VERSION 5.8 ;
BUSBITCHARS "[]" ;
DIVIDERCHAR "/" ;
UNITS
    DATABASE MICRONS 1000 ;
END UNITS

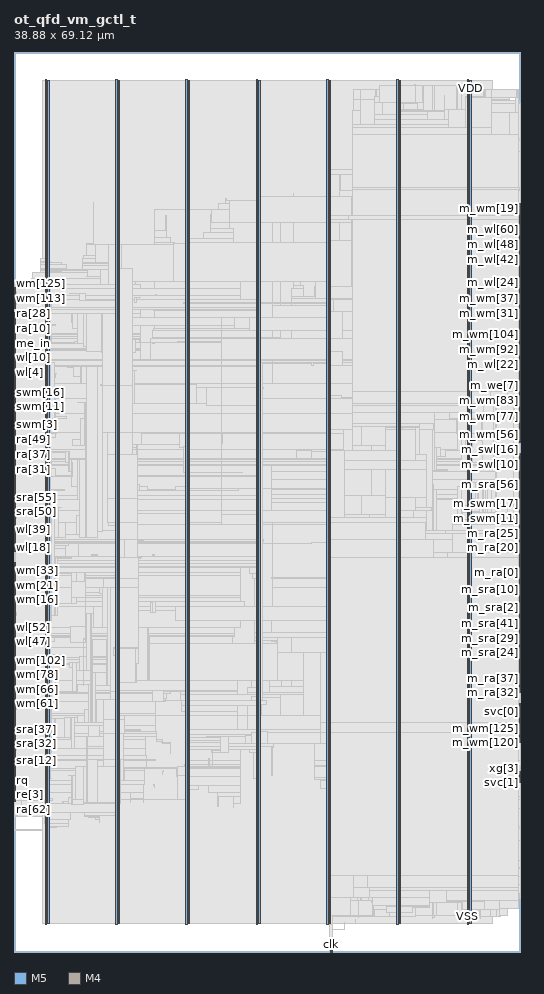
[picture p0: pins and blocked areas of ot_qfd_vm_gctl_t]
MACRO ot_qfd_vm_gctl_t
  FOREIGN ot_qfd_vm_gctl_t 0 0 ;
  CLASS BLOCK ;
  SIZE 38.88 BY 69.12 ;
  PIN clk
    DIRECTION INPUT ;
    USE SIGNAL ;
    PORT
      LAYER M5 ;
        RECT  24.336 0 24.36 0.084 ;
    END
  END clk
  PIN m_ra[0]
    DIRECTION OUTPUT ;
    USE SIGNAL ;
    PORT
      LAYER M4 ;
        RECT  38.796 29.136 38.88 29.16 ;
    END
  END m_ra[0]
  PIN m_ra[10]
    DIRECTION OUTPUT ;
    USE SIGNAL ;
    PORT
      LAYER M4 ;
        RECT  38.796 30.096 38.88 30.12 ;
    END
  END m_ra[10]
  PIN m_ra[11]
    DIRECTION OUTPUT ;
    USE SIGNAL ;
    PORT
      LAYER M4 ;
        RECT  38.796 30.192 38.88 30.216 ;
    END
  END m_ra[11]
  PIN m_ra[12]
    DIRECTION OUTPUT ;
    USE SIGNAL ;
    PORT
      LAYER M4 ;
        RECT  38.796 30.288 38.88 30.312 ;
    END
  END m_ra[12]
  PIN m_ra[13]
    DIRECTION OUTPUT ;
    USE SIGNAL ;
    PORT
      LAYER M4 ;
        RECT  38.796 30.384 38.88 30.408 ;
    END
  END m_ra[13]
  PIN m_ra[14]
    DIRECTION OUTPUT ;
    USE SIGNAL ;
    PORT
      LAYER M4 ;
        RECT  38.796 30.48 38.88 30.504 ;
    END
  END m_ra[14]
  PIN m_ra[15]
    DIRECTION OUTPUT ;
    USE SIGNAL ;
    PORT
      LAYER M4 ;
        RECT  38.796 30.576 38.88 30.6 ;
    END
  END m_ra[15]
  PIN m_ra[16]
    DIRECTION OUTPUT ;
    USE SIGNAL ;
    PORT
      LAYER M4 ;
        RECT  38.796 30.672 38.88 30.696 ;
    END
  END m_ra[16]
  PIN m_ra[17]
    DIRECTION OUTPUT ;
    USE SIGNAL ;
    PORT
      LAYER M4 ;
        RECT  38.796 30.768 38.88 30.792 ;
    END
  END m_ra[17]
  PIN m_ra[18]
    DIRECTION OUTPUT ;
    USE SIGNAL ;
    PORT
      LAYER M4 ;
        RECT  38.796 30.864 38.88 30.888 ;
    END
  END m_ra[18]
  PIN m_ra[19]
    DIRECTION OUTPUT ;
    USE SIGNAL ;
    PORT
      LAYER M4 ;
        RECT  38.796 30.96 38.88 30.984 ;
    END
  END m_ra[19]
  PIN m_ra[1]
    DIRECTION OUTPUT ;
    USE SIGNAL ;
    PORT
      LAYER M4 ;
        RECT  38.796 29.232 38.88 29.256 ;
    END
  END m_ra[1]
  PIN m_ra[20]
    DIRECTION OUTPUT ;
    USE SIGNAL ;
    PORT
      LAYER M4 ;
        RECT  38.796 31.056 38.88 31.08 ;
    END
  END m_ra[20]
  PIN m_ra[21]
    DIRECTION OUTPUT ;
    USE SIGNAL ;
    PORT
      LAYER M4 ;
        RECT  38.796 31.152 38.88 31.176 ;
    END
  END m_ra[21]
  PIN m_ra[22]
    DIRECTION OUTPUT ;
    USE SIGNAL ;
    PORT
      LAYER M4 ;
        RECT  38.796 31.248 38.88 31.272 ;
    END
  END m_ra[22]
  PIN m_ra[23]
    DIRECTION OUTPUT ;
    USE SIGNAL ;
    PORT
      LAYER M4 ;
        RECT  38.796 31.344 38.88 31.368 ;
    END
  END m_ra[23]
  PIN m_ra[24]
    DIRECTION OUTPUT ;
    USE SIGNAL ;
    PORT
      LAYER M4 ;
        RECT  38.796 31.44 38.88 31.464 ;
    END
  END m_ra[24]
  PIN m_ra[25]
    DIRECTION OUTPUT ;
    USE SIGNAL ;
    PORT
      LAYER M4 ;
        RECT  38.796 31.536 38.88 31.56 ;
    END
  END m_ra[25]
  PIN m_ra[26]
    DIRECTION OUTPUT ;
    USE SIGNAL ;
    PORT
      LAYER M4 ;
        RECT  38.796 31.632 38.88 31.656 ;
    END
  END m_ra[26]
  PIN m_ra[27]
    DIRECTION OUTPUT ;
    USE SIGNAL ;
    PORT
      LAYER M4 ;
        RECT  38.796 31.728 38.88 31.752 ;
    END
  END m_ra[27]
  PIN m_ra[28]
    DIRECTION OUTPUT ;
    USE SIGNAL ;
    PORT
      LAYER M4 ;
        RECT  38.796 31.824 38.88 31.848 ;
    END
  END m_ra[28]
  PIN m_ra[29]
    DIRECTION OUTPUT ;
    USE SIGNAL ;
    PORT
      LAYER M4 ;
        RECT  38.796 31.92 38.88 31.944 ;
    END
  END m_ra[29]
  PIN m_ra[2]
    DIRECTION OUTPUT ;
    USE SIGNAL ;
    PORT
      LAYER M4 ;
        RECT  38.796 29.328 38.88 29.352 ;
    END
  END m_ra[2]
  PIN m_ra[30]
    DIRECTION OUTPUT ;
    USE SIGNAL ;
    PORT
      LAYER M4 ;
        RECT  38.796 32.016 38.88 32.04 ;
    END
  END m_ra[30]
  PIN m_ra[31]
    DIRECTION OUTPUT ;
    USE SIGNAL ;
    PORT
      LAYER M4 ;
        RECT  38.796 32.112 38.88 32.136 ;
    END
  END m_ra[31]
  PIN m_ra[32]
    DIRECTION OUTPUT ;
    USE SIGNAL ;
    PORT
      LAYER M4 ;
        RECT  38.796 19.92 38.88 19.944 ;
    END
  END m_ra[32]
  PIN m_ra[33]
    DIRECTION OUTPUT ;
    USE SIGNAL ;
    PORT
      LAYER M4 ;
        RECT  38.796 20.016 38.88 20.04 ;
    END
  END m_ra[33]
  PIN m_ra[34]
    DIRECTION OUTPUT ;
    USE SIGNAL ;
    PORT
      LAYER M4 ;
        RECT  38.796 20.112 38.88 20.136 ;
    END
  END m_ra[34]
  PIN m_ra[35]
    DIRECTION OUTPUT ;
    USE SIGNAL ;
    PORT
      LAYER M4 ;
        RECT  38.796 20.208 38.88 20.232 ;
    END
  END m_ra[35]
  PIN m_ra[36]
    DIRECTION OUTPUT ;
    USE SIGNAL ;
    PORT
      LAYER M4 ;
        RECT  38.796 20.304 38.88 20.328 ;
    END
  END m_ra[36]
  PIN m_ra[37]
    DIRECTION OUTPUT ;
    USE SIGNAL ;
    PORT
      LAYER M4 ;
        RECT  38.796 20.4 38.88 20.424 ;
    END
  END m_ra[37]
  PIN m_ra[38]
    DIRECTION OUTPUT ;
    USE SIGNAL ;
    PORT
      LAYER M4 ;
        RECT  38.796 20.496 38.88 20.52 ;
    END
  END m_ra[38]
  PIN m_ra[39]
    DIRECTION OUTPUT ;
    USE SIGNAL ;
    PORT
      LAYER M4 ;
        RECT  38.796 20.592 38.88 20.616 ;
    END
  END m_ra[39]
  PIN m_ra[3]
    DIRECTION OUTPUT ;
    USE SIGNAL ;
    PORT
      LAYER M4 ;
        RECT  38.796 29.424 38.88 29.448 ;
    END
  END m_ra[3]
  PIN m_ra[40]
    DIRECTION OUTPUT ;
    USE SIGNAL ;
    PORT
      LAYER M4 ;
        RECT  38.796 20.688 38.88 20.712 ;
    END
  END m_ra[40]
  PIN m_ra[41]
    DIRECTION OUTPUT ;
    USE SIGNAL ;
    PORT
      LAYER M4 ;
        RECT  38.796 20.784 38.88 20.808 ;
    END
  END m_ra[41]
  PIN m_ra[42]
    DIRECTION OUTPUT ;
    USE SIGNAL ;
    PORT
      LAYER M4 ;
        RECT  38.796 20.88 38.88 20.904 ;
    END
  END m_ra[42]
  PIN m_ra[43]
    DIRECTION OUTPUT ;
    USE SIGNAL ;
    PORT
      LAYER M4 ;
        RECT  38.796 20.976 38.88 21 ;
    END
  END m_ra[43]
  PIN m_ra[44]
    DIRECTION OUTPUT ;
    USE SIGNAL ;
    PORT
      LAYER M4 ;
        RECT  38.796 21.072 38.88 21.096 ;
    END
  END m_ra[44]
  PIN m_ra[45]
    DIRECTION OUTPUT ;
    USE SIGNAL ;
    PORT
      LAYER M4 ;
        RECT  38.796 21.168 38.88 21.192 ;
    END
  END m_ra[45]
  PIN m_ra[46]
    DIRECTION OUTPUT ;
    USE SIGNAL ;
    PORT
      LAYER M4 ;
        RECT  38.796 21.264 38.88 21.288 ;
    END
  END m_ra[46]
  PIN m_ra[47]
    DIRECTION OUTPUT ;
    USE SIGNAL ;
    PORT
      LAYER M4 ;
        RECT  38.796 21.36 38.88 21.384 ;
    END
  END m_ra[47]
  PIN m_ra[48]
    DIRECTION OUTPUT ;
    USE SIGNAL ;
    PORT
      LAYER M4 ;
        RECT  38.796 21.456 38.88 21.48 ;
    END
  END m_ra[48]
  PIN m_ra[49]
    DIRECTION OUTPUT ;
    USE SIGNAL ;
    PORT
      LAYER M4 ;
        RECT  38.796 21.552 38.88 21.576 ;
    END
  END m_ra[49]
  PIN m_ra[4]
    DIRECTION OUTPUT ;
    USE SIGNAL ;
    PORT
      LAYER M4 ;
        RECT  38.796 29.52 38.88 29.544 ;
    END
  END m_ra[4]
  PIN m_ra[50]
    DIRECTION OUTPUT ;
    USE SIGNAL ;
    PORT
      LAYER M4 ;
        RECT  38.796 21.648 38.88 21.672 ;
    END
  END m_ra[50]
  PIN m_ra[51]
    DIRECTION OUTPUT ;
    USE SIGNAL ;
    PORT
      LAYER M4 ;
        RECT  38.796 21.744 38.88 21.768 ;
    END
  END m_ra[51]
  PIN m_ra[52]
    DIRECTION OUTPUT ;
    USE SIGNAL ;
    PORT
      LAYER M4 ;
        RECT  38.796 21.84 38.88 21.864 ;
    END
  END m_ra[52]
  PIN m_ra[53]
    DIRECTION OUTPUT ;
    USE SIGNAL ;
    PORT
      LAYER M4 ;
        RECT  38.796 21.936 38.88 21.96 ;
    END
  END m_ra[53]
  PIN m_ra[54]
    DIRECTION OUTPUT ;
    USE SIGNAL ;
    PORT
      LAYER M4 ;
        RECT  38.796 22.032 38.88 22.056 ;
    END
  END m_ra[54]
  PIN m_ra[55]
    DIRECTION OUTPUT ;
    USE SIGNAL ;
    PORT
      LAYER M4 ;
        RECT  38.796 22.128 38.88 22.152 ;
    END
  END m_ra[55]
  PIN m_ra[56]
    DIRECTION OUTPUT ;
    USE SIGNAL ;
    PORT
      LAYER M4 ;
        RECT  38.796 22.224 38.88 22.248 ;
    END
  END m_ra[56]
  PIN m_ra[57]
    DIRECTION OUTPUT ;
    USE SIGNAL ;
    PORT
      LAYER M4 ;
        RECT  38.796 22.32 38.88 22.344 ;
    END
  END m_ra[57]
  PIN m_ra[58]
    DIRECTION OUTPUT ;
    USE SIGNAL ;
    PORT
      LAYER M4 ;
        RECT  38.796 22.416 38.88 22.44 ;
    END
  END m_ra[58]
  PIN m_ra[59]
    DIRECTION OUTPUT ;
    USE SIGNAL ;
    PORT
      LAYER M4 ;
        RECT  38.796 22.512 38.88 22.536 ;
    END
  END m_ra[59]
  PIN m_ra[5]
    DIRECTION OUTPUT ;
    USE SIGNAL ;
    PORT
      LAYER M4 ;
        RECT  38.796 29.616 38.88 29.64 ;
    END
  END m_ra[5]
  PIN m_ra[60]
    DIRECTION OUTPUT ;
    USE SIGNAL ;
    PORT
      LAYER M4 ;
        RECT  38.796 22.608 38.88 22.632 ;
    END
  END m_ra[60]
  PIN m_ra[61]
    DIRECTION OUTPUT ;
    USE SIGNAL ;
    PORT
      LAYER M4 ;
        RECT  38.796 22.704 38.88 22.728 ;
    END
  END m_ra[61]
  PIN m_ra[62]
    DIRECTION OUTPUT ;
    USE SIGNAL ;
    PORT
      LAYER M4 ;
        RECT  38.796 22.8 38.88 22.824 ;
    END
  END m_ra[62]
  PIN m_ra[63]
    DIRECTION OUTPUT ;
    USE SIGNAL ;
    PORT
      LAYER M4 ;
        RECT  38.796 22.896 38.88 22.92 ;
    END
  END m_ra[63]
  PIN m_ra[6]
    DIRECTION OUTPUT ;
    USE SIGNAL ;
    PORT
      LAYER M4 ;
        RECT  38.796 29.712 38.88 29.736 ;
    END
  END m_ra[6]
  PIN m_ra[7]
    DIRECTION OUTPUT ;
    USE SIGNAL ;
    PORT
      LAYER M4 ;
        RECT  38.796 29.808 38.88 29.832 ;
    END
  END m_ra[7]
  PIN m_ra[8]
    DIRECTION OUTPUT ;
    USE SIGNAL ;
    PORT
      LAYER M4 ;
        RECT  38.796 29.904 38.88 29.928 ;
    END
  END m_ra[8]
  PIN m_ra[9]
    DIRECTION OUTPUT ;
    USE SIGNAL ;
    PORT
      LAYER M4 ;
        RECT  38.796 30 38.88 30.024 ;
    END
  END m_ra[9]
  PIN m_re[0]
    DIRECTION OUTPUT ;
    USE SIGNAL ;
    PORT
      LAYER M4 ;
        RECT  38.796 26.064 38.88 26.088 ;
    END
  END m_re[0]
  PIN m_re[1]
    DIRECTION OUTPUT ;
    USE SIGNAL ;
    PORT
      LAYER M4 ;
        RECT  38.796 26.16 38.88 26.184 ;
    END
  END m_re[1]
  PIN m_re[2]
    DIRECTION OUTPUT ;
    USE SIGNAL ;
    PORT
      LAYER M4 ;
        RECT  38.796 26.256 38.88 26.28 ;
    END
  END m_re[2]
  PIN m_re[3]
    DIRECTION OUTPUT ;
    USE SIGNAL ;
    PORT
      LAYER M4 ;
        RECT  38.796 26.352 38.88 26.376 ;
    END
  END m_re[3]
  PIN m_re[4]
    DIRECTION OUTPUT ;
    USE SIGNAL ;
    PORT
      LAYER M4 ;
        RECT  38.796 26.448 38.88 26.472 ;
    END
  END m_re[4]
  PIN m_re[5]
    DIRECTION OUTPUT ;
    USE SIGNAL ;
    PORT
      LAYER M4 ;
        RECT  38.796 26.544 38.88 26.568 ;
    END
  END m_re[5]
  PIN m_re[6]
    DIRECTION OUTPUT ;
    USE SIGNAL ;
    PORT
      LAYER M4 ;
        RECT  38.796 26.64 38.88 26.664 ;
    END
  END m_re[6]
  PIN m_re[7]
    DIRECTION OUTPUT ;
    USE SIGNAL ;
    PORT
      LAYER M4 ;
        RECT  38.796 26.736 38.88 26.76 ;
    END
  END m_re[7]
  PIN m_sra[0]
    DIRECTION OUTPUT ;
    USE SIGNAL ;
    PORT
      LAYER M4 ;
        RECT  38.796 26.832 38.88 26.856 ;
    END
  END m_sra[0]
  PIN m_sra[10]
    DIRECTION OUTPUT ;
    USE SIGNAL ;
    PORT
      LAYER M4 ;
        RECT  38.796 27.792 38.88 27.816 ;
    END
  END m_sra[10]
  PIN m_sra[11]
    DIRECTION OUTPUT ;
    USE SIGNAL ;
    PORT
      LAYER M4 ;
        RECT  38.796 27.888 38.88 27.912 ;
    END
  END m_sra[11]
  PIN m_sra[12]
    DIRECTION OUTPUT ;
    USE SIGNAL ;
    PORT
      LAYER M4 ;
        RECT  38.796 27.984 38.88 28.008 ;
    END
  END m_sra[12]
  PIN m_sra[13]
    DIRECTION OUTPUT ;
    USE SIGNAL ;
    PORT
      LAYER M4 ;
        RECT  38.796 28.08 38.88 28.104 ;
    END
  END m_sra[13]
  PIN m_sra[14]
    DIRECTION OUTPUT ;
    USE SIGNAL ;
    PORT
      LAYER M4 ;
        RECT  38.796 28.176 38.88 28.2 ;
    END
  END m_sra[14]
  PIN m_sra[15]
    DIRECTION OUTPUT ;
    USE SIGNAL ;
    PORT
      LAYER M4 ;
        RECT  38.796 28.272 38.88 28.296 ;
    END
  END m_sra[15]
  PIN m_sra[16]
    DIRECTION OUTPUT ;
    USE SIGNAL ;
    PORT
      LAYER M4 ;
        RECT  38.796 28.368 38.88 28.392 ;
    END
  END m_sra[16]
  PIN m_sra[17]
    DIRECTION OUTPUT ;
    USE SIGNAL ;
    PORT
      LAYER M4 ;
        RECT  38.796 28.464 38.88 28.488 ;
    END
  END m_sra[17]
  PIN m_sra[18]
    DIRECTION OUTPUT ;
    USE SIGNAL ;
    PORT
      LAYER M4 ;
        RECT  38.796 28.56 38.88 28.584 ;
    END
  END m_sra[18]
  PIN m_sra[19]
    DIRECTION OUTPUT ;
    USE SIGNAL ;
    PORT
      LAYER M4 ;
        RECT  38.796 28.656 38.88 28.68 ;
    END
  END m_sra[19]
  PIN m_sra[1]
    DIRECTION OUTPUT ;
    USE SIGNAL ;
    PORT
      LAYER M4 ;
        RECT  38.796 26.928 38.88 26.952 ;
    END
  END m_sra[1]
  PIN m_sra[20]
    DIRECTION OUTPUT ;
    USE SIGNAL ;
    PORT
      LAYER M4 ;
        RECT  38.796 28.752 38.88 28.776 ;
    END
  END m_sra[20]
  PIN m_sra[21]
    DIRECTION OUTPUT ;
    USE SIGNAL ;
    PORT
      LAYER M4 ;
        RECT  38.796 28.848 38.88 28.872 ;
    END
  END m_sra[21]
  PIN m_sra[22]
    DIRECTION OUTPUT ;
    USE SIGNAL ;
    PORT
      LAYER M4 ;
        RECT  38.796 28.944 38.88 28.968 ;
    END
  END m_sra[22]
  PIN m_sra[23]
    DIRECTION OUTPUT ;
    USE SIGNAL ;
    PORT
      LAYER M4 ;
        RECT  38.796 29.04 38.88 29.064 ;
    END
  END m_sra[23]
  PIN m_sra[24]
    DIRECTION OUTPUT ;
    USE SIGNAL ;
    PORT
      LAYER M4 ;
        RECT  38.796 22.992 38.88 23.016 ;
    END
  END m_sra[24]
  PIN m_sra[25]
    DIRECTION OUTPUT ;
    USE SIGNAL ;
    PORT
      LAYER M4 ;
        RECT  38.796 23.088 38.88 23.112 ;
    END
  END m_sra[25]
  PIN m_sra[26]
    DIRECTION OUTPUT ;
    USE SIGNAL ;
    PORT
      LAYER M4 ;
        RECT  38.796 23.184 38.88 23.208 ;
    END
  END m_sra[26]
  PIN m_sra[27]
    DIRECTION OUTPUT ;
    USE SIGNAL ;
    PORT
      LAYER M4 ;
        RECT  38.796 23.28 38.88 23.304 ;
    END
  END m_sra[27]
  PIN m_sra[28]
    DIRECTION OUTPUT ;
    USE SIGNAL ;
    PORT
      LAYER M4 ;
        RECT  38.796 23.376 38.88 23.4 ;
    END
  END m_sra[28]
  PIN m_sra[29]
    DIRECTION OUTPUT ;
    USE SIGNAL ;
    PORT
      LAYER M4 ;
        RECT  38.796 23.472 38.88 23.496 ;
    END
  END m_sra[29]
  PIN m_sra[2]
    DIRECTION OUTPUT ;
    USE SIGNAL ;
    PORT
      LAYER M4 ;
        RECT  38.796 27.024 38.88 27.048 ;
    END
  END m_sra[2]
  PIN m_sra[30]
    DIRECTION OUTPUT ;
    USE SIGNAL ;
    PORT
      LAYER M4 ;
        RECT  38.796 23.568 38.88 23.592 ;
    END
  END m_sra[30]
  PIN m_sra[31]
    DIRECTION OUTPUT ;
    USE SIGNAL ;
    PORT
      LAYER M4 ;
        RECT  38.796 23.664 38.88 23.688 ;
    END
  END m_sra[31]
  PIN m_sra[32]
    DIRECTION OUTPUT ;
    USE SIGNAL ;
    PORT
      LAYER M4 ;
        RECT  38.796 23.76 38.88 23.784 ;
    END
  END m_sra[32]
  PIN m_sra[33]
    DIRECTION OUTPUT ;
    USE SIGNAL ;
    PORT
      LAYER M4 ;
        RECT  38.796 23.856 38.88 23.88 ;
    END
  END m_sra[33]
  PIN m_sra[34]
    DIRECTION OUTPUT ;
    USE SIGNAL ;
    PORT
      LAYER M4 ;
        RECT  38.796 23.952 38.88 23.976 ;
    END
  END m_sra[34]
  PIN m_sra[35]
    DIRECTION OUTPUT ;
    USE SIGNAL ;
    PORT
      LAYER M4 ;
        RECT  38.796 24.048 38.88 24.072 ;
    END
  END m_sra[35]
  PIN m_sra[36]
    DIRECTION OUTPUT ;
    USE SIGNAL ;
    PORT
      LAYER M4 ;
        RECT  38.796 24.144 38.88 24.168 ;
    END
  END m_sra[36]
  PIN m_sra[37]
    DIRECTION OUTPUT ;
    USE SIGNAL ;
    PORT
      LAYER M4 ;
        RECT  38.796 24.24 38.88 24.264 ;
    END
  END m_sra[37]
  PIN m_sra[38]
    DIRECTION OUTPUT ;
    USE SIGNAL ;
    PORT
      LAYER M4 ;
        RECT  38.796 24.336 38.88 24.36 ;
    END
  END m_sra[38]
  PIN m_sra[39]
    DIRECTION OUTPUT ;
    USE SIGNAL ;
    PORT
      LAYER M4 ;
        RECT  38.796 24.432 38.88 24.456 ;
    END
  END m_sra[39]
  PIN m_sra[3]
    DIRECTION OUTPUT ;
    USE SIGNAL ;
    PORT
      LAYER M4 ;
        RECT  38.796 27.12 38.88 27.144 ;
    END
  END m_sra[3]
  PIN m_sra[40]
    DIRECTION OUTPUT ;
    USE SIGNAL ;
    PORT
      LAYER M4 ;
        RECT  38.796 24.528 38.88 24.552 ;
    END
  END m_sra[40]
  PIN m_sra[41]
    DIRECTION OUTPUT ;
    USE SIGNAL ;
    PORT
      LAYER M4 ;
        RECT  38.796 24.624 38.88 24.648 ;
    END
  END m_sra[41]
  PIN m_sra[42]
    DIRECTION OUTPUT ;
    USE SIGNAL ;
    PORT
      LAYER M4 ;
        RECT  38.796 24.72 38.88 24.744 ;
    END
  END m_sra[42]
  PIN m_sra[43]
    DIRECTION OUTPUT ;
    USE SIGNAL ;
    PORT
      LAYER M4 ;
        RECT  38.796 24.816 38.88 24.84 ;
    END
  END m_sra[43]
  PIN m_sra[44]
    DIRECTION OUTPUT ;
    USE SIGNAL ;
    PORT
      LAYER M4 ;
        RECT  38.796 24.912 38.88 24.936 ;
    END
  END m_sra[44]
  PIN m_sra[45]
    DIRECTION OUTPUT ;
    USE SIGNAL ;
    PORT
      LAYER M4 ;
        RECT  38.796 25.008 38.88 25.032 ;
    END
  END m_sra[45]
  PIN m_sra[46]
    DIRECTION OUTPUT ;
    USE SIGNAL ;
    PORT
      LAYER M4 ;
        RECT  38.796 25.104 38.88 25.128 ;
    END
  END m_sra[46]
  PIN m_sra[47]
    DIRECTION OUTPUT ;
    USE SIGNAL ;
    PORT
      LAYER M4 ;
        RECT  38.796 25.2 38.88 25.224 ;
    END
  END m_sra[47]
  PIN m_sra[48]
    DIRECTION OUTPUT ;
    USE SIGNAL ;
    PORT
      LAYER M4 ;
        RECT  38.796 25.296 38.88 25.32 ;
    END
  END m_sra[48]
  PIN m_sra[49]
    DIRECTION OUTPUT ;
    USE SIGNAL ;
    PORT
      LAYER M4 ;
        RECT  38.796 25.392 38.88 25.416 ;
    END
  END m_sra[49]
  PIN m_sra[4]
    DIRECTION OUTPUT ;
    USE SIGNAL ;
    PORT
      LAYER M4 ;
        RECT  38.796 27.216 38.88 27.24 ;
    END
  END m_sra[4]
  PIN m_sra[50]
    DIRECTION OUTPUT ;
    USE SIGNAL ;
    PORT
      LAYER M4 ;
        RECT  38.796 25.488 38.88 25.512 ;
    END
  END m_sra[50]
  PIN m_sra[51]
    DIRECTION OUTPUT ;
    USE SIGNAL ;
    PORT
      LAYER M4 ;
        RECT  38.796 25.584 38.88 25.608 ;
    END
  END m_sra[51]
  PIN m_sra[52]
    DIRECTION OUTPUT ;
    USE SIGNAL ;
    PORT
      LAYER M4 ;
        RECT  38.796 25.68 38.88 25.704 ;
    END
  END m_sra[52]
  PIN m_sra[53]
    DIRECTION OUTPUT ;
    USE SIGNAL ;
    PORT
      LAYER M4 ;
        RECT  38.796 25.776 38.88 25.8 ;
    END
  END m_sra[53]
  PIN m_sra[54]
    DIRECTION OUTPUT ;
    USE SIGNAL ;
    PORT
      LAYER M4 ;
        RECT  38.796 25.872 38.88 25.896 ;
    END
  END m_sra[54]
  PIN m_sra[55]
    DIRECTION OUTPUT ;
    USE SIGNAL ;
    PORT
      LAYER M4 ;
        RECT  38.796 25.968 38.88 25.992 ;
    END
  END m_sra[55]
  PIN m_sra[56]
    DIRECTION OUTPUT ;
    USE SIGNAL ;
    PORT
      LAYER M4 ;
        RECT  38.796 35.28 38.88 35.304 ;
    END
  END m_sra[56]
  PIN m_sra[57]
    DIRECTION OUTPUT ;
    USE SIGNAL ;
    PORT
      LAYER M4 ;
        RECT  38.796 35.376 38.88 35.4 ;
    END
  END m_sra[57]
  PIN m_sra[58]
    DIRECTION OUTPUT ;
    USE SIGNAL ;
    PORT
      LAYER M4 ;
        RECT  38.796 35.472 38.88 35.496 ;
    END
  END m_sra[58]
  PIN m_sra[59]
    DIRECTION OUTPUT ;
    USE SIGNAL ;
    PORT
      LAYER M4 ;
        RECT  38.796 35.568 38.88 35.592 ;
    END
  END m_sra[59]
  PIN m_sra[5]
    DIRECTION OUTPUT ;
    USE SIGNAL ;
    PORT
      LAYER M4 ;
        RECT  38.796 27.312 38.88 27.336 ;
    END
  END m_sra[5]
  PIN m_sra[6]
    DIRECTION OUTPUT ;
    USE SIGNAL ;
    PORT
      LAYER M4 ;
        RECT  38.796 27.408 38.88 27.432 ;
    END
  END m_sra[6]
  PIN m_sra[7]
    DIRECTION OUTPUT ;
    USE SIGNAL ;
    PORT
      LAYER M4 ;
        RECT  38.796 27.504 38.88 27.528 ;
    END
  END m_sra[7]
  PIN m_sra[8]
    DIRECTION OUTPUT ;
    USE SIGNAL ;
    PORT
      LAYER M4 ;
        RECT  38.796 27.6 38.88 27.624 ;
    END
  END m_sra[8]
  PIN m_sra[9]
    DIRECTION OUTPUT ;
    USE SIGNAL ;
    PORT
      LAYER M4 ;
        RECT  38.796 27.696 38.88 27.72 ;
    END
  END m_sra[9]
  PIN m_sre[0]
    DIRECTION OUTPUT ;
    USE SIGNAL ;
    PORT
      LAYER M4 ;
        RECT  38.796 35.664 38.88 35.688 ;
    END
  END m_sre[0]
  PIN m_sre[1]
    DIRECTION OUTPUT ;
    USE SIGNAL ;
    PORT
      LAYER M4 ;
        RECT  38.796 35.76 38.88 35.784 ;
    END
  END m_sre[1]
  PIN m_sre[2]
    DIRECTION OUTPUT ;
    USE SIGNAL ;
    PORT
      LAYER M4 ;
        RECT  38.796 35.856 38.88 35.88 ;
    END
  END m_sre[2]
  PIN m_sre[3]
    DIRECTION OUTPUT ;
    USE SIGNAL ;
    PORT
      LAYER M4 ;
        RECT  38.796 35.952 38.88 35.976 ;
    END
  END m_sre[3]
  PIN m_sre[4]
    DIRECTION OUTPUT ;
    USE SIGNAL ;
    PORT
      LAYER M4 ;
        RECT  38.796 36.048 38.88 36.072 ;
    END
  END m_sre[4]
  PIN m_sre[5]
    DIRECTION OUTPUT ;
    USE SIGNAL ;
    PORT
      LAYER M4 ;
        RECT  38.796 36.144 38.88 36.168 ;
    END
  END m_sre[5]
  PIN m_swe[0]
    DIRECTION OUTPUT ;
    USE SIGNAL ;
    PORT
      LAYER M4 ;
        RECT  38.796 36.24 38.88 36.264 ;
    END
  END m_swe[0]
  PIN m_swe[1]
    DIRECTION OUTPUT ;
    USE SIGNAL ;
    PORT
      LAYER M4 ;
        RECT  38.796 36.336 38.88 36.36 ;
    END
  END m_swe[1]
  PIN m_swl[0]
    DIRECTION OUTPUT ;
    USE SIGNAL ;
    PORT
      LAYER M4 ;
        RECT  38.796 36.432 38.88 36.456 ;
    END
  END m_swl[0]
  PIN m_swl[10]
    DIRECTION OUTPUT ;
    USE SIGNAL ;
    PORT
      LAYER M4 ;
        RECT  38.796 37.392 38.88 37.416 ;
    END
  END m_swl[10]
  PIN m_swl[11]
    DIRECTION OUTPUT ;
    USE SIGNAL ;
    PORT
      LAYER M4 ;
        RECT  38.796 37.488 38.88 37.512 ;
    END
  END m_swl[11]
  PIN m_swl[12]
    DIRECTION OUTPUT ;
    USE SIGNAL ;
    PORT
      LAYER M4 ;
        RECT  38.796 37.584 38.88 37.608 ;
    END
  END m_swl[12]
  PIN m_swl[13]
    DIRECTION OUTPUT ;
    USE SIGNAL ;
    PORT
      LAYER M4 ;
        RECT  38.796 37.68 38.88 37.704 ;
    END
  END m_swl[13]
  PIN m_swl[14]
    DIRECTION OUTPUT ;
    USE SIGNAL ;
    PORT
      LAYER M4 ;
        RECT  38.796 37.776 38.88 37.8 ;
    END
  END m_swl[14]
  PIN m_swl[15]
    DIRECTION OUTPUT ;
    USE SIGNAL ;
    PORT
      LAYER M4 ;
        RECT  38.796 37.872 38.88 37.896 ;
    END
  END m_swl[15]
  PIN m_swl[16]
    DIRECTION OUTPUT ;
    USE SIGNAL ;
    PORT
      LAYER M4 ;
        RECT  38.796 37.968 38.88 37.992 ;
    END
  END m_swl[16]
  PIN m_swl[17]
    DIRECTION OUTPUT ;
    USE SIGNAL ;
    PORT
      LAYER M4 ;
        RECT  38.796 38.064 38.88 38.088 ;
    END
  END m_swl[17]
  PIN m_swl[18]
    DIRECTION OUTPUT ;
    USE SIGNAL ;
    PORT
      LAYER M4 ;
        RECT  38.796 38.16 38.88 38.184 ;
    END
  END m_swl[18]
  PIN m_swl[19]
    DIRECTION OUTPUT ;
    USE SIGNAL ;
    PORT
      LAYER M4 ;
        RECT  38.796 38.256 38.88 38.28 ;
    END
  END m_swl[19]
  PIN m_swl[1]
    DIRECTION OUTPUT ;
    USE SIGNAL ;
    PORT
      LAYER M4 ;
        RECT  38.796 36.528 38.88 36.552 ;
    END
  END m_swl[1]
  PIN m_swl[2]
    DIRECTION OUTPUT ;
    USE SIGNAL ;
    PORT
      LAYER M4 ;
        RECT  38.796 36.624 38.88 36.648 ;
    END
  END m_swl[2]
  PIN m_swl[3]
    DIRECTION OUTPUT ;
    USE SIGNAL ;
    PORT
      LAYER M4 ;
        RECT  38.796 36.72 38.88 36.744 ;
    END
  END m_swl[3]
  PIN m_swl[4]
    DIRECTION OUTPUT ;
    USE SIGNAL ;
    PORT
      LAYER M4 ;
        RECT  38.796 36.816 38.88 36.84 ;
    END
  END m_swl[4]
  PIN m_swl[5]
    DIRECTION OUTPUT ;
    USE SIGNAL ;
    PORT
      LAYER M4 ;
        RECT  38.796 36.912 38.88 36.936 ;
    END
  END m_swl[5]
  PIN m_swl[6]
    DIRECTION OUTPUT ;
    USE SIGNAL ;
    PORT
      LAYER M4 ;
        RECT  38.796 37.008 38.88 37.032 ;
    END
  END m_swl[6]
  PIN m_swl[7]
    DIRECTION OUTPUT ;
    USE SIGNAL ;
    PORT
      LAYER M4 ;
        RECT  38.796 37.104 38.88 37.128 ;
    END
  END m_swl[7]
  PIN m_swl[8]
    DIRECTION OUTPUT ;
    USE SIGNAL ;
    PORT
      LAYER M4 ;
        RECT  38.796 37.2 38.88 37.224 ;
    END
  END m_swl[8]
  PIN m_swl[9]
    DIRECTION OUTPUT ;
    USE SIGNAL ;
    PORT
      LAYER M4 ;
        RECT  38.796 37.296 38.88 37.32 ;
    END
  END m_swl[9]
  PIN m_swm[0]
    DIRECTION OUTPUT ;
    USE SIGNAL ;
    PORT
      LAYER M4 ;
        RECT  38.796 32.208 38.88 32.232 ;
    END
  END m_swm[0]
  PIN m_swm[10]
    DIRECTION OUTPUT ;
    USE SIGNAL ;
    PORT
      LAYER M4 ;
        RECT  38.796 33.168 38.88 33.192 ;
    END
  END m_swm[10]
  PIN m_swm[11]
    DIRECTION OUTPUT ;
    USE SIGNAL ;
    PORT
      LAYER M4 ;
        RECT  38.796 33.264 38.88 33.288 ;
    END
  END m_swm[11]
  PIN m_swm[12]
    DIRECTION OUTPUT ;
    USE SIGNAL ;
    PORT
      LAYER M4 ;
        RECT  38.796 33.36 38.88 33.384 ;
    END
  END m_swm[12]
  PIN m_swm[13]
    DIRECTION OUTPUT ;
    USE SIGNAL ;
    PORT
      LAYER M4 ;
        RECT  38.796 33.456 38.88 33.48 ;
    END
  END m_swm[13]
  PIN m_swm[14]
    DIRECTION OUTPUT ;
    USE SIGNAL ;
    PORT
      LAYER M4 ;
        RECT  38.796 33.552 38.88 33.576 ;
    END
  END m_swm[14]
  PIN m_swm[15]
    DIRECTION OUTPUT ;
    USE SIGNAL ;
    PORT
      LAYER M4 ;
        RECT  38.796 33.648 38.88 33.672 ;
    END
  END m_swm[15]
  PIN m_swm[16]
    DIRECTION OUTPUT ;
    USE SIGNAL ;
    PORT
      LAYER M4 ;
        RECT  38.796 33.744 38.88 33.768 ;
    END
  END m_swm[16]
  PIN m_swm[17]
    DIRECTION OUTPUT ;
    USE SIGNAL ;
    PORT
      LAYER M4 ;
        RECT  38.796 33.84 38.88 33.864 ;
    END
  END m_swm[17]
  PIN m_swm[18]
    DIRECTION OUTPUT ;
    USE SIGNAL ;
    PORT
      LAYER M4 ;
        RECT  38.796 33.936 38.88 33.96 ;
    END
  END m_swm[18]
  PIN m_swm[19]
    DIRECTION OUTPUT ;
    USE SIGNAL ;
    PORT
      LAYER M4 ;
        RECT  38.796 34.032 38.88 34.056 ;
    END
  END m_swm[19]
  PIN m_swm[1]
    DIRECTION OUTPUT ;
    USE SIGNAL ;
    PORT
      LAYER M4 ;
        RECT  38.796 32.304 38.88 32.328 ;
    END
  END m_swm[1]
  PIN m_swm[20]
    DIRECTION OUTPUT ;
    USE SIGNAL ;
    PORT
      LAYER M4 ;
        RECT  38.796 34.128 38.88 34.152 ;
    END
  END m_swm[20]
  PIN m_swm[21]
    DIRECTION OUTPUT ;
    USE SIGNAL ;
    PORT
      LAYER M4 ;
        RECT  38.796 34.224 38.88 34.248 ;
    END
  END m_swm[21]
  PIN m_swm[22]
    DIRECTION OUTPUT ;
    USE SIGNAL ;
    PORT
      LAYER M4 ;
        RECT  38.796 34.32 38.88 34.344 ;
    END
  END m_swm[22]
  PIN m_swm[23]
    DIRECTION OUTPUT ;
    USE SIGNAL ;
    PORT
      LAYER M4 ;
        RECT  38.796 34.416 38.88 34.44 ;
    END
  END m_swm[23]
  PIN m_swm[24]
    DIRECTION OUTPUT ;
    USE SIGNAL ;
    PORT
      LAYER M4 ;
        RECT  38.796 34.512 38.88 34.536 ;
    END
  END m_swm[24]
  PIN m_swm[25]
    DIRECTION OUTPUT ;
    USE SIGNAL ;
    PORT
      LAYER M4 ;
        RECT  38.796 34.608 38.88 34.632 ;
    END
  END m_swm[25]
  PIN m_swm[26]
    DIRECTION OUTPUT ;
    USE SIGNAL ;
    PORT
      LAYER M4 ;
        RECT  38.796 34.704 38.88 34.728 ;
    END
  END m_swm[26]
  PIN m_swm[27]
    DIRECTION OUTPUT ;
    USE SIGNAL ;
    PORT
      LAYER M4 ;
        RECT  38.796 34.8 38.88 34.824 ;
    END
  END m_swm[27]
  PIN m_swm[28]
    DIRECTION OUTPUT ;
    USE SIGNAL ;
    PORT
      LAYER M4 ;
        RECT  38.796 34.896 38.88 34.92 ;
    END
  END m_swm[28]
  PIN m_swm[29]
    DIRECTION OUTPUT ;
    USE SIGNAL ;
    PORT
      LAYER M4 ;
        RECT  38.796 34.992 38.88 35.016 ;
    END
  END m_swm[29]
  PIN m_swm[2]
    DIRECTION OUTPUT ;
    USE SIGNAL ;
    PORT
      LAYER M4 ;
        RECT  38.796 32.4 38.88 32.424 ;
    END
  END m_swm[2]
  PIN m_swm[30]
    DIRECTION OUTPUT ;
    USE SIGNAL ;
    PORT
      LAYER M4 ;
        RECT  38.796 35.088 38.88 35.112 ;
    END
  END m_swm[30]
  PIN m_swm[31]
    DIRECTION OUTPUT ;
    USE SIGNAL ;
    PORT
      LAYER M4 ;
        RECT  38.796 35.184 38.88 35.208 ;
    END
  END m_swm[31]
  PIN m_swm[3]
    DIRECTION OUTPUT ;
    USE SIGNAL ;
    PORT
      LAYER M4 ;
        RECT  38.796 32.496 38.88 32.52 ;
    END
  END m_swm[3]
  PIN m_swm[4]
    DIRECTION OUTPUT ;
    USE SIGNAL ;
    PORT
      LAYER M4 ;
        RECT  38.796 32.592 38.88 32.616 ;
    END
  END m_swm[4]
  PIN m_swm[5]
    DIRECTION OUTPUT ;
    USE SIGNAL ;
    PORT
      LAYER M4 ;
        RECT  38.796 32.688 38.88 32.712 ;
    END
  END m_swm[5]
  PIN m_swm[6]
    DIRECTION OUTPUT ;
    USE SIGNAL ;
    PORT
      LAYER M4 ;
        RECT  38.796 32.784 38.88 32.808 ;
    END
  END m_swm[6]
  PIN m_swm[7]
    DIRECTION OUTPUT ;
    USE SIGNAL ;
    PORT
      LAYER M4 ;
        RECT  38.796 32.88 38.88 32.904 ;
    END
  END m_swm[7]
  PIN m_swm[8]
    DIRECTION OUTPUT ;
    USE SIGNAL ;
    PORT
      LAYER M4 ;
        RECT  38.796 32.976 38.88 33 ;
    END
  END m_swm[8]
  PIN m_swm[9]
    DIRECTION OUTPUT ;
    USE SIGNAL ;
    PORT
      LAYER M4 ;
        RECT  38.796 33.072 38.88 33.096 ;
    END
  END m_swm[9]
  PIN m_we[0]
    DIRECTION OUTPUT ;
    USE SIGNAL ;
    PORT
      LAYER M4 ;
        RECT  38.796 42.192 38.88 42.216 ;
    END
  END m_we[0]
  PIN m_we[1]
    DIRECTION OUTPUT ;
    USE SIGNAL ;
    PORT
      LAYER M4 ;
        RECT  38.796 42.288 38.88 42.312 ;
    END
  END m_we[1]
  PIN m_we[2]
    DIRECTION OUTPUT ;
    USE SIGNAL ;
    PORT
      LAYER M4 ;
        RECT  38.796 42.384 38.88 42.408 ;
    END
  END m_we[2]
  PIN m_we[3]
    DIRECTION OUTPUT ;
    USE SIGNAL ;
    PORT
      LAYER M4 ;
        RECT  38.796 42.48 38.88 42.504 ;
    END
  END m_we[3]
  PIN m_we[4]
    DIRECTION OUTPUT ;
    USE SIGNAL ;
    PORT
      LAYER M4 ;
        RECT  38.796 42.576 38.88 42.6 ;
    END
  END m_we[4]
  PIN m_we[5]
    DIRECTION OUTPUT ;
    USE SIGNAL ;
    PORT
      LAYER M4 ;
        RECT  38.796 42.672 38.88 42.696 ;
    END
  END m_we[5]
  PIN m_we[6]
    DIRECTION OUTPUT ;
    USE SIGNAL ;
    PORT
      LAYER M4 ;
        RECT  38.796 42.768 38.88 42.792 ;
    END
  END m_we[6]
  PIN m_we[7]
    DIRECTION OUTPUT ;
    USE SIGNAL ;
    PORT
      LAYER M4 ;
        RECT  38.796 42.864 38.88 42.888 ;
    END
  END m_we[7]
  PIN m_wl[0]
    DIRECTION OUTPUT ;
    USE SIGNAL ;
    PORT
      LAYER M4 ;
        RECT  38.796 42.96 38.88 42.984 ;
    END
  END m_wl[0]
  PIN m_wl[10]
    DIRECTION OUTPUT ;
    USE SIGNAL ;
    PORT
      LAYER M4 ;
        RECT  38.796 43.92 38.88 43.944 ;
    END
  END m_wl[10]
  PIN m_wl[11]
    DIRECTION OUTPUT ;
    USE SIGNAL ;
    PORT
      LAYER M4 ;
        RECT  38.796 44.016 38.88 44.04 ;
    END
  END m_wl[11]
  PIN m_wl[12]
    DIRECTION OUTPUT ;
    USE SIGNAL ;
    PORT
      LAYER M4 ;
        RECT  38.796 44.112 38.88 44.136 ;
    END
  END m_wl[12]
  PIN m_wl[13]
    DIRECTION OUTPUT ;
    USE SIGNAL ;
    PORT
      LAYER M4 ;
        RECT  38.796 44.208 38.88 44.232 ;
    END
  END m_wl[13]
  PIN m_wl[14]
    DIRECTION OUTPUT ;
    USE SIGNAL ;
    PORT
      LAYER M4 ;
        RECT  38.796 44.304 38.88 44.328 ;
    END
  END m_wl[14]
  PIN m_wl[15]
    DIRECTION OUTPUT ;
    USE SIGNAL ;
    PORT
      LAYER M4 ;
        RECT  38.796 44.4 38.88 44.424 ;
    END
  END m_wl[15]
  PIN m_wl[16]
    DIRECTION OUTPUT ;
    USE SIGNAL ;
    PORT
      LAYER M4 ;
        RECT  38.796 44.496 38.88 44.52 ;
    END
  END m_wl[16]
  PIN m_wl[17]
    DIRECTION OUTPUT ;
    USE SIGNAL ;
    PORT
      LAYER M4 ;
        RECT  38.796 44.592 38.88 44.616 ;
    END
  END m_wl[17]
  PIN m_wl[18]
    DIRECTION OUTPUT ;
    USE SIGNAL ;
    PORT
      LAYER M4 ;
        RECT  38.796 44.688 38.88 44.712 ;
    END
  END m_wl[18]
  PIN m_wl[19]
    DIRECTION OUTPUT ;
    USE SIGNAL ;
    PORT
      LAYER M4 ;
        RECT  38.796 44.784 38.88 44.808 ;
    END
  END m_wl[19]
  PIN m_wl[1]
    DIRECTION OUTPUT ;
    USE SIGNAL ;
    PORT
      LAYER M4 ;
        RECT  38.796 43.056 38.88 43.08 ;
    END
  END m_wl[1]
  PIN m_wl[20]
    DIRECTION OUTPUT ;
    USE SIGNAL ;
    PORT
      LAYER M4 ;
        RECT  38.796 44.88 38.88 44.904 ;
    END
  END m_wl[20]
  PIN m_wl[21]
    DIRECTION OUTPUT ;
    USE SIGNAL ;
    PORT
      LAYER M4 ;
        RECT  38.796 44.976 38.88 45 ;
    END
  END m_wl[21]
  PIN m_wl[22]
    DIRECTION OUTPUT ;
    USE SIGNAL ;
    PORT
      LAYER M4 ;
        RECT  38.796 45.072 38.88 45.096 ;
    END
  END m_wl[22]
  PIN m_wl[23]
    DIRECTION OUTPUT ;
    USE SIGNAL ;
    PORT
      LAYER M4 ;
        RECT  38.796 45.168 38.88 45.192 ;
    END
  END m_wl[23]
  PIN m_wl[24]
    DIRECTION OUTPUT ;
    USE SIGNAL ;
    PORT
      LAYER M4 ;
        RECT  38.796 51.408 38.88 51.432 ;
    END
  END m_wl[24]
  PIN m_wl[25]
    DIRECTION OUTPUT ;
    USE SIGNAL ;
    PORT
      LAYER M4 ;
        RECT  38.796 51.504 38.88 51.528 ;
    END
  END m_wl[25]
  PIN m_wl[26]
    DIRECTION OUTPUT ;
    USE SIGNAL ;
    PORT
      LAYER M4 ;
        RECT  38.796 51.6 38.88 51.624 ;
    END
  END m_wl[26]
  PIN m_wl[27]
    DIRECTION OUTPUT ;
    USE SIGNAL ;
    PORT
      LAYER M4 ;
        RECT  38.796 51.696 38.88 51.72 ;
    END
  END m_wl[27]
  PIN m_wl[28]
    DIRECTION OUTPUT ;
    USE SIGNAL ;
    PORT
      LAYER M4 ;
        RECT  38.796 51.792 38.88 51.816 ;
    END
  END m_wl[28]
  PIN m_wl[29]
    DIRECTION OUTPUT ;
    USE SIGNAL ;
    PORT
      LAYER M4 ;
        RECT  38.796 51.888 38.88 51.912 ;
    END
  END m_wl[29]
  PIN m_wl[2]
    DIRECTION OUTPUT ;
    USE SIGNAL ;
    PORT
      LAYER M4 ;
        RECT  38.796 43.152 38.88 43.176 ;
    END
  END m_wl[2]
  PIN m_wl[30]
    DIRECTION OUTPUT ;
    USE SIGNAL ;
    PORT
      LAYER M4 ;
        RECT  38.796 51.984 38.88 52.008 ;
    END
  END m_wl[30]
  PIN m_wl[31]
    DIRECTION OUTPUT ;
    USE SIGNAL ;
    PORT
      LAYER M4 ;
        RECT  38.796 52.08 38.88 52.104 ;
    END
  END m_wl[31]
  PIN m_wl[32]
    DIRECTION OUTPUT ;
    USE SIGNAL ;
    PORT
      LAYER M4 ;
        RECT  38.796 52.176 38.88 52.2 ;
    END
  END m_wl[32]
  PIN m_wl[33]
    DIRECTION OUTPUT ;
    USE SIGNAL ;
    PORT
      LAYER M4 ;
        RECT  38.796 52.272 38.88 52.296 ;
    END
  END m_wl[33]
  PIN m_wl[34]
    DIRECTION OUTPUT ;
    USE SIGNAL ;
    PORT
      LAYER M4 ;
        RECT  38.796 52.368 38.88 52.392 ;
    END
  END m_wl[34]
  PIN m_wl[35]
    DIRECTION OUTPUT ;
    USE SIGNAL ;
    PORT
      LAYER M4 ;
        RECT  38.796 52.464 38.88 52.488 ;
    END
  END m_wl[35]
  PIN m_wl[36]
    DIRECTION OUTPUT ;
    USE SIGNAL ;
    PORT
      LAYER M4 ;
        RECT  38.796 52.56 38.88 52.584 ;
    END
  END m_wl[36]
  PIN m_wl[37]
    DIRECTION OUTPUT ;
    USE SIGNAL ;
    PORT
      LAYER M4 ;
        RECT  38.796 52.656 38.88 52.68 ;
    END
  END m_wl[37]
  PIN m_wl[38]
    DIRECTION OUTPUT ;
    USE SIGNAL ;
    PORT
      LAYER M4 ;
        RECT  38.796 52.752 38.88 52.776 ;
    END
  END m_wl[38]
  PIN m_wl[39]
    DIRECTION OUTPUT ;
    USE SIGNAL ;
    PORT
      LAYER M4 ;
        RECT  38.796 52.848 38.88 52.872 ;
    END
  END m_wl[39]
  PIN m_wl[3]
    DIRECTION OUTPUT ;
    USE SIGNAL ;
    PORT
      LAYER M4 ;
        RECT  38.796 43.248 38.88 43.272 ;
    END
  END m_wl[3]
  PIN m_wl[40]
    DIRECTION OUTPUT ;
    USE SIGNAL ;
    PORT
      LAYER M4 ;
        RECT  38.796 52.944 38.88 52.968 ;
    END
  END m_wl[40]
  PIN m_wl[41]
    DIRECTION OUTPUT ;
    USE SIGNAL ;
    PORT
      LAYER M4 ;
        RECT  38.796 53.04 38.88 53.064 ;
    END
  END m_wl[41]
  PIN m_wl[42]
    DIRECTION OUTPUT ;
    USE SIGNAL ;
    PORT
      LAYER M4 ;
        RECT  38.796 53.136 38.88 53.16 ;
    END
  END m_wl[42]
  PIN m_wl[43]
    DIRECTION OUTPUT ;
    USE SIGNAL ;
    PORT
      LAYER M4 ;
        RECT  38.796 53.232 38.88 53.256 ;
    END
  END m_wl[43]
  PIN m_wl[44]
    DIRECTION OUTPUT ;
    USE SIGNAL ;
    PORT
      LAYER M4 ;
        RECT  38.796 53.328 38.88 53.352 ;
    END
  END m_wl[44]
  PIN m_wl[45]
    DIRECTION OUTPUT ;
    USE SIGNAL ;
    PORT
      LAYER M4 ;
        RECT  38.796 53.424 38.88 53.448 ;
    END
  END m_wl[45]
  PIN m_wl[46]
    DIRECTION OUTPUT ;
    USE SIGNAL ;
    PORT
      LAYER M4 ;
        RECT  38.796 53.52 38.88 53.544 ;
    END
  END m_wl[46]
  PIN m_wl[47]
    DIRECTION OUTPUT ;
    USE SIGNAL ;
    PORT
      LAYER M4 ;
        RECT  38.796 53.616 38.88 53.64 ;
    END
  END m_wl[47]
  PIN m_wl[48]
    DIRECTION OUTPUT ;
    USE SIGNAL ;
    PORT
      LAYER M4 ;
        RECT  38.796 53.712 38.88 53.736 ;
    END
  END m_wl[48]
  PIN m_wl[49]
    DIRECTION OUTPUT ;
    USE SIGNAL ;
    PORT
      LAYER M4 ;
        RECT  38.796 53.808 38.88 53.832 ;
    END
  END m_wl[49]
  PIN m_wl[4]
    DIRECTION OUTPUT ;
    USE SIGNAL ;
    PORT
      LAYER M4 ;
        RECT  38.796 43.344 38.88 43.368 ;
    END
  END m_wl[4]
  PIN m_wl[50]
    DIRECTION OUTPUT ;
    USE SIGNAL ;
    PORT
      LAYER M4 ;
        RECT  38.796 53.904 38.88 53.928 ;
    END
  END m_wl[50]
  PIN m_wl[51]
    DIRECTION OUTPUT ;
    USE SIGNAL ;
    PORT
      LAYER M4 ;
        RECT  38.796 54 38.88 54.024 ;
    END
  END m_wl[51]
  PIN m_wl[52]
    DIRECTION OUTPUT ;
    USE SIGNAL ;
    PORT
      LAYER M4 ;
        RECT  38.796 54.096 38.88 54.12 ;
    END
  END m_wl[52]
  PIN m_wl[53]
    DIRECTION OUTPUT ;
    USE SIGNAL ;
    PORT
      LAYER M4 ;
        RECT  38.796 54.192 38.88 54.216 ;
    END
  END m_wl[53]
  PIN m_wl[54]
    DIRECTION OUTPUT ;
    USE SIGNAL ;
    PORT
      LAYER M4 ;
        RECT  38.796 54.288 38.88 54.312 ;
    END
  END m_wl[54]
  PIN m_wl[55]
    DIRECTION OUTPUT ;
    USE SIGNAL ;
    PORT
      LAYER M4 ;
        RECT  38.796 54.384 38.88 54.408 ;
    END
  END m_wl[55]
  PIN m_wl[56]
    DIRECTION OUTPUT ;
    USE SIGNAL ;
    PORT
      LAYER M4 ;
        RECT  38.796 54.48 38.88 54.504 ;
    END
  END m_wl[56]
  PIN m_wl[57]
    DIRECTION OUTPUT ;
    USE SIGNAL ;
    PORT
      LAYER M4 ;
        RECT  38.796 54.576 38.88 54.6 ;
    END
  END m_wl[57]
  PIN m_wl[58]
    DIRECTION OUTPUT ;
    USE SIGNAL ;
    PORT
      LAYER M4 ;
        RECT  38.796 54.672 38.88 54.696 ;
    END
  END m_wl[58]
  PIN m_wl[59]
    DIRECTION OUTPUT ;
    USE SIGNAL ;
    PORT
      LAYER M4 ;
        RECT  38.796 54.768 38.88 54.792 ;
    END
  END m_wl[59]
  PIN m_wl[5]
    DIRECTION OUTPUT ;
    USE SIGNAL ;
    PORT
      LAYER M4 ;
        RECT  38.796 43.44 38.88 43.464 ;
    END
  END m_wl[5]
  PIN m_wl[60]
    DIRECTION OUTPUT ;
    USE SIGNAL ;
    PORT
      LAYER M4 ;
        RECT  38.796 54.864 38.88 54.888 ;
    END
  END m_wl[60]
  PIN m_wl[61]
    DIRECTION OUTPUT ;
    USE SIGNAL ;
    PORT
      LAYER M4 ;
        RECT  38.796 54.96 38.88 54.984 ;
    END
  END m_wl[61]
  PIN m_wl[62]
    DIRECTION OUTPUT ;
    USE SIGNAL ;
    PORT
      LAYER M4 ;
        RECT  38.796 55.056 38.88 55.08 ;
    END
  END m_wl[62]
  PIN m_wl[63]
    DIRECTION OUTPUT ;
    USE SIGNAL ;
    PORT
      LAYER M4 ;
        RECT  38.796 55.152 38.88 55.176 ;
    END
  END m_wl[63]
  PIN m_wl[6]
    DIRECTION OUTPUT ;
    USE SIGNAL ;
    PORT
      LAYER M4 ;
        RECT  38.796 43.536 38.88 43.56 ;
    END
  END m_wl[6]
  PIN m_wl[7]
    DIRECTION OUTPUT ;
    USE SIGNAL ;
    PORT
      LAYER M4 ;
        RECT  38.796 43.632 38.88 43.656 ;
    END
  END m_wl[7]
  PIN m_wl[8]
    DIRECTION OUTPUT ;
    USE SIGNAL ;
    PORT
      LAYER M4 ;
        RECT  38.796 43.728 38.88 43.752 ;
    END
  END m_wl[8]
  PIN m_wl[9]
    DIRECTION OUTPUT ;
    USE SIGNAL ;
    PORT
      LAYER M4 ;
        RECT  38.796 43.824 38.88 43.848 ;
    END
  END m_wl[9]
  PIN m_wm[0]
    DIRECTION OUTPUT ;
    USE SIGNAL ;
    PORT
      LAYER M4 ;
        RECT  38.796 55.248 38.88 55.272 ;
    END
  END m_wm[0]
  PIN m_wm[100]
    DIRECTION OUTPUT ;
    USE SIGNAL ;
    PORT
      LAYER M4 ;
        RECT  38.796 46.416 38.88 46.44 ;
    END
  END m_wm[100]
  PIN m_wm[101]
    DIRECTION OUTPUT ;
    USE SIGNAL ;
    PORT
      LAYER M4 ;
        RECT  38.796 46.512 38.88 46.536 ;
    END
  END m_wm[101]
  PIN m_wm[102]
    DIRECTION OUTPUT ;
    USE SIGNAL ;
    PORT
      LAYER M4 ;
        RECT  38.796 46.608 38.88 46.632 ;
    END
  END m_wm[102]
  PIN m_wm[103]
    DIRECTION OUTPUT ;
    USE SIGNAL ;
    PORT
      LAYER M4 ;
        RECT  38.796 46.704 38.88 46.728 ;
    END
  END m_wm[103]
  PIN m_wm[104]
    DIRECTION OUTPUT ;
    USE SIGNAL ;
    PORT
      LAYER M4 ;
        RECT  38.796 46.8 38.88 46.824 ;
    END
  END m_wm[104]
  PIN m_wm[105]
    DIRECTION OUTPUT ;
    USE SIGNAL ;
    PORT
      LAYER M4 ;
        RECT  38.796 46.896 38.88 46.92 ;
    END
  END m_wm[105]
  PIN m_wm[106]
    DIRECTION OUTPUT ;
    USE SIGNAL ;
    PORT
      LAYER M4 ;
        RECT  38.796 46.992 38.88 47.016 ;
    END
  END m_wm[106]
  PIN m_wm[107]
    DIRECTION OUTPUT ;
    USE SIGNAL ;
    PORT
      LAYER M4 ;
        RECT  38.796 47.088 38.88 47.112 ;
    END
  END m_wm[107]
  PIN m_wm[108]
    DIRECTION OUTPUT ;
    USE SIGNAL ;
    PORT
      LAYER M4 ;
        RECT  38.796 47.184 38.88 47.208 ;
    END
  END m_wm[108]
  PIN m_wm[109]
    DIRECTION OUTPUT ;
    USE SIGNAL ;
    PORT
      LAYER M4 ;
        RECT  38.796 47.28 38.88 47.304 ;
    END
  END m_wm[109]
  PIN m_wm[10]
    DIRECTION OUTPUT ;
    USE SIGNAL ;
    PORT
      LAYER M4 ;
        RECT  38.796 56.208 38.88 56.232 ;
    END
  END m_wm[10]
  PIN m_wm[110]
    DIRECTION OUTPUT ;
    USE SIGNAL ;
    PORT
      LAYER M4 ;
        RECT  38.796 47.376 38.88 47.4 ;
    END
  END m_wm[110]
  PIN m_wm[111]
    DIRECTION OUTPUT ;
    USE SIGNAL ;
    PORT
      LAYER M4 ;
        RECT  38.796 47.472 38.88 47.496 ;
    END
  END m_wm[111]
  PIN m_wm[112]
    DIRECTION OUTPUT ;
    USE SIGNAL ;
    PORT
      LAYER M4 ;
        RECT  38.796 47.568 38.88 47.592 ;
    END
  END m_wm[112]
  PIN m_wm[113]
    DIRECTION OUTPUT ;
    USE SIGNAL ;
    PORT
      LAYER M4 ;
        RECT  38.796 47.664 38.88 47.688 ;
    END
  END m_wm[113]
  PIN m_wm[114]
    DIRECTION OUTPUT ;
    USE SIGNAL ;
    PORT
      LAYER M4 ;
        RECT  38.796 47.76 38.88 47.784 ;
    END
  END m_wm[114]
  PIN m_wm[115]
    DIRECTION OUTPUT ;
    USE SIGNAL ;
    PORT
      LAYER M4 ;
        RECT  38.796 47.856 38.88 47.88 ;
    END
  END m_wm[115]
  PIN m_wm[116]
    DIRECTION OUTPUT ;
    USE SIGNAL ;
    PORT
      LAYER M4 ;
        RECT  38.796 47.952 38.88 47.976 ;
    END
  END m_wm[116]
  PIN m_wm[117]
    DIRECTION OUTPUT ;
    USE SIGNAL ;
    PORT
      LAYER M4 ;
        RECT  38.796 48.048 38.88 48.072 ;
    END
  END m_wm[117]
  PIN m_wm[118]
    DIRECTION OUTPUT ;
    USE SIGNAL ;
    PORT
      LAYER M4 ;
        RECT  38.796 48.144 38.88 48.168 ;
    END
  END m_wm[118]
  PIN m_wm[119]
    DIRECTION OUTPUT ;
    USE SIGNAL ;
    PORT
      LAYER M4 ;
        RECT  38.796 48.24 38.88 48.264 ;
    END
  END m_wm[119]
  PIN m_wm[11]
    DIRECTION OUTPUT ;
    USE SIGNAL ;
    PORT
      LAYER M4 ;
        RECT  38.796 56.304 38.88 56.328 ;
    END
  END m_wm[11]
  PIN m_wm[120]
    DIRECTION OUTPUT ;
    USE SIGNAL ;
    PORT
      LAYER M4 ;
        RECT  38.796 16.08 38.88 16.104 ;
    END
  END m_wm[120]
  PIN m_wm[121]
    DIRECTION OUTPUT ;
    USE SIGNAL ;
    PORT
      LAYER M4 ;
        RECT  38.796 16.176 38.88 16.2 ;
    END
  END m_wm[121]
  PIN m_wm[122]
    DIRECTION OUTPUT ;
    USE SIGNAL ;
    PORT
      LAYER M4 ;
        RECT  38.796 16.272 38.88 16.296 ;
    END
  END m_wm[122]
  PIN m_wm[123]
    DIRECTION OUTPUT ;
    USE SIGNAL ;
    PORT
      LAYER M4 ;
        RECT  38.796 16.368 38.88 16.392 ;
    END
  END m_wm[123]
  PIN m_wm[124]
    DIRECTION OUTPUT ;
    USE SIGNAL ;
    PORT
      LAYER M4 ;
        RECT  38.796 16.464 38.88 16.488 ;
    END
  END m_wm[124]
  PIN m_wm[125]
    DIRECTION OUTPUT ;
    USE SIGNAL ;
    PORT
      LAYER M4 ;
        RECT  38.796 16.56 38.88 16.584 ;
    END
  END m_wm[125]
  PIN m_wm[126]
    DIRECTION OUTPUT ;
    USE SIGNAL ;
    PORT
      LAYER M4 ;
        RECT  38.796 16.656 38.88 16.68 ;
    END
  END m_wm[126]
  PIN m_wm[127]
    DIRECTION OUTPUT ;
    USE SIGNAL ;
    PORT
      LAYER M4 ;
        RECT  38.796 16.752 38.88 16.776 ;
    END
  END m_wm[127]
  PIN m_wm[12]
    DIRECTION OUTPUT ;
    USE SIGNAL ;
    PORT
      LAYER M4 ;
        RECT  38.796 56.4 38.88 56.424 ;
    END
  END m_wm[12]
  PIN m_wm[13]
    DIRECTION OUTPUT ;
    USE SIGNAL ;
    PORT
      LAYER M4 ;
        RECT  38.796 56.496 38.88 56.52 ;
    END
  END m_wm[13]
  PIN m_wm[14]
    DIRECTION OUTPUT ;
    USE SIGNAL ;
    PORT
      LAYER M4 ;
        RECT  38.796 56.592 38.88 56.616 ;
    END
  END m_wm[14]
  PIN m_wm[15]
    DIRECTION OUTPUT ;
    USE SIGNAL ;
    PORT
      LAYER M4 ;
        RECT  38.796 56.688 38.88 56.712 ;
    END
  END m_wm[15]
  PIN m_wm[16]
    DIRECTION OUTPUT ;
    USE SIGNAL ;
    PORT
      LAYER M4 ;
        RECT  38.796 56.784 38.88 56.808 ;
    END
  END m_wm[16]
  PIN m_wm[17]
    DIRECTION OUTPUT ;
    USE SIGNAL ;
    PORT
      LAYER M4 ;
        RECT  38.796 56.88 38.88 56.904 ;
    END
  END m_wm[17]
  PIN m_wm[18]
    DIRECTION OUTPUT ;
    USE SIGNAL ;
    PORT
      LAYER M4 ;
        RECT  38.796 56.976 38.88 57 ;
    END
  END m_wm[18]
  PIN m_wm[19]
    DIRECTION OUTPUT ;
    USE SIGNAL ;
    PORT
      LAYER M4 ;
        RECT  38.796 57.072 38.88 57.096 ;
    END
  END m_wm[19]
  PIN m_wm[1]
    DIRECTION OUTPUT ;
    USE SIGNAL ;
    PORT
      LAYER M4 ;
        RECT  38.796 55.344 38.88 55.368 ;
    END
  END m_wm[1]
  PIN m_wm[20]
    DIRECTION OUTPUT ;
    USE SIGNAL ;
    PORT
      LAYER M4 ;
        RECT  38.796 57.168 38.88 57.192 ;
    END
  END m_wm[20]
  PIN m_wm[21]
    DIRECTION OUTPUT ;
    USE SIGNAL ;
    PORT
      LAYER M4 ;
        RECT  38.796 57.264 38.88 57.288 ;
    END
  END m_wm[21]
  PIN m_wm[22]
    DIRECTION OUTPUT ;
    USE SIGNAL ;
    PORT
      LAYER M4 ;
        RECT  38.796 57.36 38.88 57.384 ;
    END
  END m_wm[22]
  PIN m_wm[23]
    DIRECTION OUTPUT ;
    USE SIGNAL ;
    PORT
      LAYER M4 ;
        RECT  38.796 57.456 38.88 57.48 ;
    END
  END m_wm[23]
  PIN m_wm[24]
    DIRECTION OUTPUT ;
    USE SIGNAL ;
    PORT
      LAYER M4 ;
        RECT  38.796 48.336 38.88 48.36 ;
    END
  END m_wm[24]
  PIN m_wm[25]
    DIRECTION OUTPUT ;
    USE SIGNAL ;
    PORT
      LAYER M4 ;
        RECT  38.796 48.432 38.88 48.456 ;
    END
  END m_wm[25]
  PIN m_wm[26]
    DIRECTION OUTPUT ;
    USE SIGNAL ;
    PORT
      LAYER M4 ;
        RECT  38.796 48.528 38.88 48.552 ;
    END
  END m_wm[26]
  PIN m_wm[27]
    DIRECTION OUTPUT ;
    USE SIGNAL ;
    PORT
      LAYER M4 ;
        RECT  38.796 48.624 38.88 48.648 ;
    END
  END m_wm[27]
  PIN m_wm[28]
    DIRECTION OUTPUT ;
    USE SIGNAL ;
    PORT
      LAYER M4 ;
        RECT  38.796 48.72 38.88 48.744 ;
    END
  END m_wm[28]
  PIN m_wm[29]
    DIRECTION OUTPUT ;
    USE SIGNAL ;
    PORT
      LAYER M4 ;
        RECT  38.796 48.816 38.88 48.84 ;
    END
  END m_wm[29]
  PIN m_wm[2]
    DIRECTION OUTPUT ;
    USE SIGNAL ;
    PORT
      LAYER M4 ;
        RECT  38.796 55.44 38.88 55.464 ;
    END
  END m_wm[2]
  PIN m_wm[30]
    DIRECTION OUTPUT ;
    USE SIGNAL ;
    PORT
      LAYER M4 ;
        RECT  38.796 48.912 38.88 48.936 ;
    END
  END m_wm[30]
  PIN m_wm[31]
    DIRECTION OUTPUT ;
    USE SIGNAL ;
    PORT
      LAYER M4 ;
        RECT  38.796 49.008 38.88 49.032 ;
    END
  END m_wm[31]
  PIN m_wm[32]
    DIRECTION OUTPUT ;
    USE SIGNAL ;
    PORT
      LAYER M4 ;
        RECT  38.796 49.104 38.88 49.128 ;
    END
  END m_wm[32]
  PIN m_wm[33]
    DIRECTION OUTPUT ;
    USE SIGNAL ;
    PORT
      LAYER M4 ;
        RECT  38.796 49.2 38.88 49.224 ;
    END
  END m_wm[33]
  PIN m_wm[34]
    DIRECTION OUTPUT ;
    USE SIGNAL ;
    PORT
      LAYER M4 ;
        RECT  38.796 49.296 38.88 49.32 ;
    END
  END m_wm[34]
  PIN m_wm[35]
    DIRECTION OUTPUT ;
    USE SIGNAL ;
    PORT
      LAYER M4 ;
        RECT  38.796 49.392 38.88 49.416 ;
    END
  END m_wm[35]
  PIN m_wm[36]
    DIRECTION OUTPUT ;
    USE SIGNAL ;
    PORT
      LAYER M4 ;
        RECT  38.796 49.488 38.88 49.512 ;
    END
  END m_wm[36]
  PIN m_wm[37]
    DIRECTION OUTPUT ;
    USE SIGNAL ;
    PORT
      LAYER M4 ;
        RECT  38.796 49.584 38.88 49.608 ;
    END
  END m_wm[37]
  PIN m_wm[38]
    DIRECTION OUTPUT ;
    USE SIGNAL ;
    PORT
      LAYER M4 ;
        RECT  38.796 49.68 38.88 49.704 ;
    END
  END m_wm[38]
  PIN m_wm[39]
    DIRECTION OUTPUT ;
    USE SIGNAL ;
    PORT
      LAYER M4 ;
        RECT  38.796 49.776 38.88 49.8 ;
    END
  END m_wm[39]
  PIN m_wm[3]
    DIRECTION OUTPUT ;
    USE SIGNAL ;
    PORT
      LAYER M4 ;
        RECT  38.796 55.536 38.88 55.56 ;
    END
  END m_wm[3]
  PIN m_wm[40]
    DIRECTION OUTPUT ;
    USE SIGNAL ;
    PORT
      LAYER M4 ;
        RECT  38.796 49.872 38.88 49.896 ;
    END
  END m_wm[40]
  PIN m_wm[41]
    DIRECTION OUTPUT ;
    USE SIGNAL ;
    PORT
      LAYER M4 ;
        RECT  38.796 49.968 38.88 49.992 ;
    END
  END m_wm[41]
  PIN m_wm[42]
    DIRECTION OUTPUT ;
    USE SIGNAL ;
    PORT
      LAYER M4 ;
        RECT  38.796 50.064 38.88 50.088 ;
    END
  END m_wm[42]
  PIN m_wm[43]
    DIRECTION OUTPUT ;
    USE SIGNAL ;
    PORT
      LAYER M4 ;
        RECT  38.796 50.16 38.88 50.184 ;
    END
  END m_wm[43]
  PIN m_wm[44]
    DIRECTION OUTPUT ;
    USE SIGNAL ;
    PORT
      LAYER M4 ;
        RECT  38.796 50.256 38.88 50.28 ;
    END
  END m_wm[44]
  PIN m_wm[45]
    DIRECTION OUTPUT ;
    USE SIGNAL ;
    PORT
      LAYER M4 ;
        RECT  38.796 50.352 38.88 50.376 ;
    END
  END m_wm[45]
  PIN m_wm[46]
    DIRECTION OUTPUT ;
    USE SIGNAL ;
    PORT
      LAYER M4 ;
        RECT  38.796 50.448 38.88 50.472 ;
    END
  END m_wm[46]
  PIN m_wm[47]
    DIRECTION OUTPUT ;
    USE SIGNAL ;
    PORT
      LAYER M4 ;
        RECT  38.796 50.544 38.88 50.568 ;
    END
  END m_wm[47]
  PIN m_wm[48]
    DIRECTION OUTPUT ;
    USE SIGNAL ;
    PORT
      LAYER M4 ;
        RECT  38.796 50.64 38.88 50.664 ;
    END
  END m_wm[48]
  PIN m_wm[49]
    DIRECTION OUTPUT ;
    USE SIGNAL ;
    PORT
      LAYER M4 ;
        RECT  38.796 50.736 38.88 50.76 ;
    END
  END m_wm[49]
  PIN m_wm[4]
    DIRECTION OUTPUT ;
    USE SIGNAL ;
    PORT
      LAYER M4 ;
        RECT  38.796 55.632 38.88 55.656 ;
    END
  END m_wm[4]
  PIN m_wm[50]
    DIRECTION OUTPUT ;
    USE SIGNAL ;
    PORT
      LAYER M4 ;
        RECT  38.796 50.832 38.88 50.856 ;
    END
  END m_wm[50]
  PIN m_wm[51]
    DIRECTION OUTPUT ;
    USE SIGNAL ;
    PORT
      LAYER M4 ;
        RECT  38.796 50.928 38.88 50.952 ;
    END
  END m_wm[51]
  PIN m_wm[52]
    DIRECTION OUTPUT ;
    USE SIGNAL ;
    PORT
      LAYER M4 ;
        RECT  38.796 51.024 38.88 51.048 ;
    END
  END m_wm[52]
  PIN m_wm[53]
    DIRECTION OUTPUT ;
    USE SIGNAL ;
    PORT
      LAYER M4 ;
        RECT  38.796 51.12 38.88 51.144 ;
    END
  END m_wm[53]
  PIN m_wm[54]
    DIRECTION OUTPUT ;
    USE SIGNAL ;
    PORT
      LAYER M4 ;
        RECT  38.796 51.216 38.88 51.24 ;
    END
  END m_wm[54]
  PIN m_wm[55]
    DIRECTION OUTPUT ;
    USE SIGNAL ;
    PORT
      LAYER M4 ;
        RECT  38.796 51.312 38.88 51.336 ;
    END
  END m_wm[55]
  PIN m_wm[56]
    DIRECTION OUTPUT ;
    USE SIGNAL ;
    PORT
      LAYER M4 ;
        RECT  38.796 39.12 38.88 39.144 ;
    END
  END m_wm[56]
  PIN m_wm[57]
    DIRECTION OUTPUT ;
    USE SIGNAL ;
    PORT
      LAYER M4 ;
        RECT  38.796 39.216 38.88 39.24 ;
    END
  END m_wm[57]
  PIN m_wm[58]
    DIRECTION OUTPUT ;
    USE SIGNAL ;
    PORT
      LAYER M4 ;
        RECT  38.796 39.312 38.88 39.336 ;
    END
  END m_wm[58]
  PIN m_wm[59]
    DIRECTION OUTPUT ;
    USE SIGNAL ;
    PORT
      LAYER M4 ;
        RECT  38.796 39.408 38.88 39.432 ;
    END
  END m_wm[59]
  PIN m_wm[5]
    DIRECTION OUTPUT ;
    USE SIGNAL ;
    PORT
      LAYER M4 ;
        RECT  38.796 55.728 38.88 55.752 ;
    END
  END m_wm[5]
  PIN m_wm[60]
    DIRECTION OUTPUT ;
    USE SIGNAL ;
    PORT
      LAYER M4 ;
        RECT  38.796 39.504 38.88 39.528 ;
    END
  END m_wm[60]
  PIN m_wm[61]
    DIRECTION OUTPUT ;
    USE SIGNAL ;
    PORT
      LAYER M4 ;
        RECT  38.796 39.6 38.88 39.624 ;
    END
  END m_wm[61]
  PIN m_wm[62]
    DIRECTION OUTPUT ;
    USE SIGNAL ;
    PORT
      LAYER M4 ;
        RECT  38.796 39.696 38.88 39.72 ;
    END
  END m_wm[62]
  PIN m_wm[63]
    DIRECTION OUTPUT ;
    USE SIGNAL ;
    PORT
      LAYER M4 ;
        RECT  38.796 39.792 38.88 39.816 ;
    END
  END m_wm[63]
  PIN m_wm[64]
    DIRECTION OUTPUT ;
    USE SIGNAL ;
    PORT
      LAYER M4 ;
        RECT  38.796 39.888 38.88 39.912 ;
    END
  END m_wm[64]
  PIN m_wm[65]
    DIRECTION OUTPUT ;
    USE SIGNAL ;
    PORT
      LAYER M4 ;
        RECT  38.796 39.984 38.88 40.008 ;
    END
  END m_wm[65]
  PIN m_wm[66]
    DIRECTION OUTPUT ;
    USE SIGNAL ;
    PORT
      LAYER M4 ;
        RECT  38.796 40.08 38.88 40.104 ;
    END
  END m_wm[66]
  PIN m_wm[67]
    DIRECTION OUTPUT ;
    USE SIGNAL ;
    PORT
      LAYER M4 ;
        RECT  38.796 40.176 38.88 40.2 ;
    END
  END m_wm[67]
  PIN m_wm[68]
    DIRECTION OUTPUT ;
    USE SIGNAL ;
    PORT
      LAYER M4 ;
        RECT  38.796 40.272 38.88 40.296 ;
    END
  END m_wm[68]
  PIN m_wm[69]
    DIRECTION OUTPUT ;
    USE SIGNAL ;
    PORT
      LAYER M4 ;
        RECT  38.796 40.368 38.88 40.392 ;
    END
  END m_wm[69]
  PIN m_wm[6]
    DIRECTION OUTPUT ;
    USE SIGNAL ;
    PORT
      LAYER M4 ;
        RECT  38.796 55.824 38.88 55.848 ;
    END
  END m_wm[6]
  PIN m_wm[70]
    DIRECTION OUTPUT ;
    USE SIGNAL ;
    PORT
      LAYER M4 ;
        RECT  38.796 40.464 38.88 40.488 ;
    END
  END m_wm[70]
  PIN m_wm[71]
    DIRECTION OUTPUT ;
    USE SIGNAL ;
    PORT
      LAYER M4 ;
        RECT  38.796 40.56 38.88 40.584 ;
    END
  END m_wm[71]
  PIN m_wm[72]
    DIRECTION OUTPUT ;
    USE SIGNAL ;
    PORT
      LAYER M4 ;
        RECT  38.796 40.656 38.88 40.68 ;
    END
  END m_wm[72]
  PIN m_wm[73]
    DIRECTION OUTPUT ;
    USE SIGNAL ;
    PORT
      LAYER M4 ;
        RECT  38.796 40.752 38.88 40.776 ;
    END
  END m_wm[73]
  PIN m_wm[74]
    DIRECTION OUTPUT ;
    USE SIGNAL ;
    PORT
      LAYER M4 ;
        RECT  38.796 40.848 38.88 40.872 ;
    END
  END m_wm[74]
  PIN m_wm[75]
    DIRECTION OUTPUT ;
    USE SIGNAL ;
    PORT
      LAYER M4 ;
        RECT  38.796 40.944 38.88 40.968 ;
    END
  END m_wm[75]
  PIN m_wm[76]
    DIRECTION OUTPUT ;
    USE SIGNAL ;
    PORT
      LAYER M4 ;
        RECT  38.796 41.04 38.88 41.064 ;
    END
  END m_wm[76]
  PIN m_wm[77]
    DIRECTION OUTPUT ;
    USE SIGNAL ;
    PORT
      LAYER M4 ;
        RECT  38.796 41.136 38.88 41.16 ;
    END
  END m_wm[77]
  PIN m_wm[78]
    DIRECTION OUTPUT ;
    USE SIGNAL ;
    PORT
      LAYER M4 ;
        RECT  38.796 41.232 38.88 41.256 ;
    END
  END m_wm[78]
  PIN m_wm[79]
    DIRECTION OUTPUT ;
    USE SIGNAL ;
    PORT
      LAYER M4 ;
        RECT  38.796 41.328 38.88 41.352 ;
    END
  END m_wm[79]
  PIN m_wm[7]
    DIRECTION OUTPUT ;
    USE SIGNAL ;
    PORT
      LAYER M4 ;
        RECT  38.796 55.92 38.88 55.944 ;
    END
  END m_wm[7]
  PIN m_wm[80]
    DIRECTION OUTPUT ;
    USE SIGNAL ;
    PORT
      LAYER M4 ;
        RECT  38.796 41.424 38.88 41.448 ;
    END
  END m_wm[80]
  PIN m_wm[81]
    DIRECTION OUTPUT ;
    USE SIGNAL ;
    PORT
      LAYER M4 ;
        RECT  38.796 41.52 38.88 41.544 ;
    END
  END m_wm[81]
  PIN m_wm[82]
    DIRECTION OUTPUT ;
    USE SIGNAL ;
    PORT
      LAYER M4 ;
        RECT  38.796 41.616 38.88 41.64 ;
    END
  END m_wm[82]
  PIN m_wm[83]
    DIRECTION OUTPUT ;
    USE SIGNAL ;
    PORT
      LAYER M4 ;
        RECT  38.796 41.712 38.88 41.736 ;
    END
  END m_wm[83]
  PIN m_wm[84]
    DIRECTION OUTPUT ;
    USE SIGNAL ;
    PORT
      LAYER M4 ;
        RECT  38.796 41.808 38.88 41.832 ;
    END
  END m_wm[84]
  PIN m_wm[85]
    DIRECTION OUTPUT ;
    USE SIGNAL ;
    PORT
      LAYER M4 ;
        RECT  38.796 41.904 38.88 41.928 ;
    END
  END m_wm[85]
  PIN m_wm[86]
    DIRECTION OUTPUT ;
    USE SIGNAL ;
    PORT
      LAYER M4 ;
        RECT  38.796 42 38.88 42.024 ;
    END
  END m_wm[86]
  PIN m_wm[87]
    DIRECTION OUTPUT ;
    USE SIGNAL ;
    PORT
      LAYER M4 ;
        RECT  38.796 42.096 38.88 42.12 ;
    END
  END m_wm[87]
  PIN m_wm[88]
    DIRECTION OUTPUT ;
    USE SIGNAL ;
    PORT
      LAYER M4 ;
        RECT  38.796 45.264 38.88 45.288 ;
    END
  END m_wm[88]
  PIN m_wm[89]
    DIRECTION OUTPUT ;
    USE SIGNAL ;
    PORT
      LAYER M4 ;
        RECT  38.796 45.36 38.88 45.384 ;
    END
  END m_wm[89]
  PIN m_wm[8]
    DIRECTION OUTPUT ;
    USE SIGNAL ;
    PORT
      LAYER M4 ;
        RECT  38.796 56.016 38.88 56.04 ;
    END
  END m_wm[8]
  PIN m_wm[90]
    DIRECTION OUTPUT ;
    USE SIGNAL ;
    PORT
      LAYER M4 ;
        RECT  38.796 45.456 38.88 45.48 ;
    END
  END m_wm[90]
  PIN m_wm[91]
    DIRECTION OUTPUT ;
    USE SIGNAL ;
    PORT
      LAYER M4 ;
        RECT  38.796 45.552 38.88 45.576 ;
    END
  END m_wm[91]
  PIN m_wm[92]
    DIRECTION OUTPUT ;
    USE SIGNAL ;
    PORT
      LAYER M4 ;
        RECT  38.796 45.648 38.88 45.672 ;
    END
  END m_wm[92]
  PIN m_wm[93]
    DIRECTION OUTPUT ;
    USE SIGNAL ;
    PORT
      LAYER M4 ;
        RECT  38.796 45.744 38.88 45.768 ;
    END
  END m_wm[93]
  PIN m_wm[94]
    DIRECTION OUTPUT ;
    USE SIGNAL ;
    PORT
      LAYER M4 ;
        RECT  38.796 45.84 38.88 45.864 ;
    END
  END m_wm[94]
  PIN m_wm[95]
    DIRECTION OUTPUT ;
    USE SIGNAL ;
    PORT
      LAYER M4 ;
        RECT  38.796 45.936 38.88 45.96 ;
    END
  END m_wm[95]
  PIN m_wm[96]
    DIRECTION OUTPUT ;
    USE SIGNAL ;
    PORT
      LAYER M4 ;
        RECT  38.796 46.032 38.88 46.056 ;
    END
  END m_wm[96]
  PIN m_wm[97]
    DIRECTION OUTPUT ;
    USE SIGNAL ;
    PORT
      LAYER M4 ;
        RECT  38.796 46.128 38.88 46.152 ;
    END
  END m_wm[97]
  PIN m_wm[98]
    DIRECTION OUTPUT ;
    USE SIGNAL ;
    PORT
      LAYER M4 ;
        RECT  38.796 46.224 38.88 46.248 ;
    END
  END m_wm[98]
  PIN m_wm[99]
    DIRECTION OUTPUT ;
    USE SIGNAL ;
    PORT
      LAYER M4 ;
        RECT  38.796 46.32 38.88 46.344 ;
    END
  END m_wm[99]
  PIN m_wm[9]
    DIRECTION OUTPUT ;
    USE SIGNAL ;
    PORT
      LAYER M4 ;
        RECT  38.796 56.112 38.88 56.136 ;
    END
  END m_wm[9]
  PIN me_in
    DIRECTION INPUT ;
    USE SIGNAL ;
    PORT
      LAYER M4 ;
        RECT  0 46.128 0.084 46.152 ;
    END
  END me_in
  PIN ovf
    DIRECTION OUTPUT ;
    USE SIGNAL ;
    PORT
      LAYER M4 ;
        RECT  38.796 16.848 38.88 16.872 ;
    END
  END ovf
  PIN pgw[0]
    DIRECTION OUTPUT ;
    USE SIGNAL ;
    PORT
      LAYER M4 ;
        RECT  38.796 16.944 38.88 16.968 ;
    END
  END pgw[0]
  PIN pgw[1]
    DIRECTION OUTPUT ;
    USE SIGNAL ;
    PORT
      LAYER M4 ;
        RECT  38.796 17.04 38.88 17.064 ;
    END
  END pgw[1]
  PIN pgw[2]
    DIRECTION OUTPUT ;
    USE SIGNAL ;
    PORT
      LAYER M4 ;
        RECT  38.796 17.136 38.88 17.16 ;
    END
  END pgw[2]
  PIN pgw[3]
    DIRECTION OUTPUT ;
    USE SIGNAL ;
    PORT
      LAYER M4 ;
        RECT  38.796 17.232 38.88 17.256 ;
    END
  END pgw[3]
  PIN pgw[4]
    DIRECTION OUTPUT ;
    USE SIGNAL ;
    PORT
      LAYER M4 ;
        RECT  38.796 17.328 38.88 17.352 ;
    END
  END pgw[4]
  PIN pgw[5]
    DIRECTION OUTPUT ;
    USE SIGNAL ;
    PORT
      LAYER M4 ;
        RECT  38.796 17.424 38.88 17.448 ;
    END
  END pgw[5]
  PIN pgw[6]
    DIRECTION OUTPUT ;
    USE SIGNAL ;
    PORT
      LAYER M4 ;
        RECT  38.796 17.52 38.88 17.544 ;
    END
  END pgw[6]
  PIN pgw[7]
    DIRECTION OUTPUT ;
    USE SIGNAL ;
    PORT
      LAYER M4 ;
        RECT  38.796 17.616 38.88 17.64 ;
    END
  END pgw[7]
  PIN pop
    DIRECTION INPUT ;
    USE SIGNAL ;
    PORT
      LAYER M4 ;
        RECT  0 46.224 0.084 46.248 ;
    END
  END pop
  PIN ra[0]
    DIRECTION INPUT ;
    USE SIGNAL ;
    PORT
      LAYER M4 ;
        RECT  0 46.32 0.084 46.344 ;
    END
  END ra[0]
  PIN ra[10]
    DIRECTION INPUT ;
    USE SIGNAL ;
    PORT
      LAYER M4 ;
        RECT  0 47.28 0.084 47.304 ;
    END
  END ra[10]
  PIN ra[11]
    DIRECTION INPUT ;
    USE SIGNAL ;
    PORT
      LAYER M4 ;
        RECT  0 47.376 0.084 47.4 ;
    END
  END ra[11]
  PIN ra[12]
    DIRECTION INPUT ;
    USE SIGNAL ;
    PORT
      LAYER M4 ;
        RECT  0 47.472 0.084 47.496 ;
    END
  END ra[12]
  PIN ra[13]
    DIRECTION INPUT ;
    USE SIGNAL ;
    PORT
      LAYER M4 ;
        RECT  0 47.568 0.084 47.592 ;
    END
  END ra[13]
  PIN ra[14]
    DIRECTION INPUT ;
    USE SIGNAL ;
    PORT
      LAYER M4 ;
        RECT  0 47.664 0.084 47.688 ;
    END
  END ra[14]
  PIN ra[15]
    DIRECTION INPUT ;
    USE SIGNAL ;
    PORT
      LAYER M4 ;
        RECT  0 47.76 0.084 47.784 ;
    END
  END ra[15]
  PIN ra[16]
    DIRECTION INPUT ;
    USE SIGNAL ;
    PORT
      LAYER M4 ;
        RECT  0 47.856 0.084 47.88 ;
    END
  END ra[16]
  PIN ra[17]
    DIRECTION INPUT ;
    USE SIGNAL ;
    PORT
      LAYER M4 ;
        RECT  0 47.952 0.084 47.976 ;
    END
  END ra[17]
  PIN ra[18]
    DIRECTION INPUT ;
    USE SIGNAL ;
    PORT
      LAYER M4 ;
        RECT  0 48.048 0.084 48.072 ;
    END
  END ra[18]
  PIN ra[19]
    DIRECTION INPUT ;
    USE SIGNAL ;
    PORT
      LAYER M4 ;
        RECT  0 48.144 0.084 48.168 ;
    END
  END ra[19]
  PIN ra[1]
    DIRECTION INPUT ;
    USE SIGNAL ;
    PORT
      LAYER M4 ;
        RECT  0 46.416 0.084 46.44 ;
    END
  END ra[1]
  PIN ra[20]
    DIRECTION INPUT ;
    USE SIGNAL ;
    PORT
      LAYER M4 ;
        RECT  0 48.24 0.084 48.264 ;
    END
  END ra[20]
  PIN ra[21]
    DIRECTION INPUT ;
    USE SIGNAL ;
    PORT
      LAYER M4 ;
        RECT  0 48.336 0.084 48.36 ;
    END
  END ra[21]
  PIN ra[22]
    DIRECTION INPUT ;
    USE SIGNAL ;
    PORT
      LAYER M4 ;
        RECT  0 48.432 0.084 48.456 ;
    END
  END ra[22]
  PIN ra[23]
    DIRECTION INPUT ;
    USE SIGNAL ;
    PORT
      LAYER M4 ;
        RECT  0 48.528 0.084 48.552 ;
    END
  END ra[23]
  PIN ra[24]
    DIRECTION INPUT ;
    USE SIGNAL ;
    PORT
      LAYER M4 ;
        RECT  0 48.624 0.084 48.648 ;
    END
  END ra[24]
  PIN ra[25]
    DIRECTION INPUT ;
    USE SIGNAL ;
    PORT
      LAYER M4 ;
        RECT  0 48.72 0.084 48.744 ;
    END
  END ra[25]
  PIN ra[26]
    DIRECTION INPUT ;
    USE SIGNAL ;
    PORT
      LAYER M4 ;
        RECT  0 48.816 0.084 48.84 ;
    END
  END ra[26]
  PIN ra[27]
    DIRECTION INPUT ;
    USE SIGNAL ;
    PORT
      LAYER M4 ;
        RECT  0 48.912 0.084 48.936 ;
    END
  END ra[27]
  PIN ra[28]
    DIRECTION INPUT ;
    USE SIGNAL ;
    PORT
      LAYER M4 ;
        RECT  0 49.008 0.084 49.032 ;
    END
  END ra[28]
  PIN ra[29]
    DIRECTION INPUT ;
    USE SIGNAL ;
    PORT
      LAYER M4 ;
        RECT  0 49.104 0.084 49.128 ;
    END
  END ra[29]
  PIN ra[2]
    DIRECTION INPUT ;
    USE SIGNAL ;
    PORT
      LAYER M4 ;
        RECT  0 46.512 0.084 46.536 ;
    END
  END ra[2]
  PIN ra[30]
    DIRECTION INPUT ;
    USE SIGNAL ;
    PORT
      LAYER M4 ;
        RECT  0 36.912 0.084 36.936 ;
    END
  END ra[30]
  PIN ra[31]
    DIRECTION INPUT ;
    USE SIGNAL ;
    PORT
      LAYER M4 ;
        RECT  0 37.008 0.084 37.032 ;
    END
  END ra[31]
  PIN ra[32]
    DIRECTION INPUT ;
    USE SIGNAL ;
    PORT
      LAYER M4 ;
        RECT  0 37.104 0.084 37.128 ;
    END
  END ra[32]
  PIN ra[33]
    DIRECTION INPUT ;
    USE SIGNAL ;
    PORT
      LAYER M4 ;
        RECT  0 37.2 0.084 37.224 ;
    END
  END ra[33]
  PIN ra[34]
    DIRECTION INPUT ;
    USE SIGNAL ;
    PORT
      LAYER M4 ;
        RECT  0 37.296 0.084 37.32 ;
    END
  END ra[34]
  PIN ra[35]
    DIRECTION INPUT ;
    USE SIGNAL ;
    PORT
      LAYER M4 ;
        RECT  0 37.392 0.084 37.416 ;
    END
  END ra[35]
  PIN ra[36]
    DIRECTION INPUT ;
    USE SIGNAL ;
    PORT
      LAYER M4 ;
        RECT  0 37.488 0.084 37.512 ;
    END
  END ra[36]
  PIN ra[37]
    DIRECTION INPUT ;
    USE SIGNAL ;
    PORT
      LAYER M4 ;
        RECT  0 37.584 0.084 37.608 ;
    END
  END ra[37]
  PIN ra[38]
    DIRECTION INPUT ;
    USE SIGNAL ;
    PORT
      LAYER M4 ;
        RECT  0 37.68 0.084 37.704 ;
    END
  END ra[38]
  PIN ra[39]
    DIRECTION INPUT ;
    USE SIGNAL ;
    PORT
      LAYER M4 ;
        RECT  0 37.776 0.084 37.8 ;
    END
  END ra[39]
  PIN ra[3]
    DIRECTION INPUT ;
    USE SIGNAL ;
    PORT
      LAYER M4 ;
        RECT  0 46.608 0.084 46.632 ;
    END
  END ra[3]
  PIN ra[40]
    DIRECTION INPUT ;
    USE SIGNAL ;
    PORT
      LAYER M4 ;
        RECT  0 37.872 0.084 37.896 ;
    END
  END ra[40]
  PIN ra[41]
    DIRECTION INPUT ;
    USE SIGNAL ;
    PORT
      LAYER M4 ;
        RECT  0 37.968 0.084 37.992 ;
    END
  END ra[41]
  PIN ra[42]
    DIRECTION INPUT ;
    USE SIGNAL ;
    PORT
      LAYER M4 ;
        RECT  0 38.064 0.084 38.088 ;
    END
  END ra[42]
  PIN ra[43]
    DIRECTION INPUT ;
    USE SIGNAL ;
    PORT
      LAYER M4 ;
        RECT  0 38.16 0.084 38.184 ;
    END
  END ra[43]
  PIN ra[44]
    DIRECTION INPUT ;
    USE SIGNAL ;
    PORT
      LAYER M4 ;
        RECT  0 38.256 0.084 38.28 ;
    END
  END ra[44]
  PIN ra[45]
    DIRECTION INPUT ;
    USE SIGNAL ;
    PORT
      LAYER M4 ;
        RECT  0 38.352 0.084 38.376 ;
    END
  END ra[45]
  PIN ra[46]
    DIRECTION INPUT ;
    USE SIGNAL ;
    PORT
      LAYER M4 ;
        RECT  0 38.448 0.084 38.472 ;
    END
  END ra[46]
  PIN ra[47]
    DIRECTION INPUT ;
    USE SIGNAL ;
    PORT
      LAYER M4 ;
        RECT  0 38.544 0.084 38.568 ;
    END
  END ra[47]
  PIN ra[48]
    DIRECTION INPUT ;
    USE SIGNAL ;
    PORT
      LAYER M4 ;
        RECT  0 38.64 0.084 38.664 ;
    END
  END ra[48]
  PIN ra[49]
    DIRECTION INPUT ;
    USE SIGNAL ;
    PORT
      LAYER M4 ;
        RECT  0 38.736 0.084 38.76 ;
    END
  END ra[49]
  PIN ra[4]
    DIRECTION INPUT ;
    USE SIGNAL ;
    PORT
      LAYER M4 ;
        RECT  0 46.704 0.084 46.728 ;
    END
  END ra[4]
  PIN ra[50]
    DIRECTION INPUT ;
    USE SIGNAL ;
    PORT
      LAYER M4 ;
        RECT  0 38.832 0.084 38.856 ;
    END
  END ra[50]
  PIN ra[51]
    DIRECTION INPUT ;
    USE SIGNAL ;
    PORT
      LAYER M4 ;
        RECT  0 38.928 0.084 38.952 ;
    END
  END ra[51]
  PIN ra[52]
    DIRECTION INPUT ;
    USE SIGNAL ;
    PORT
      LAYER M4 ;
        RECT  0 39.024 0.084 39.048 ;
    END
  END ra[52]
  PIN ra[53]
    DIRECTION INPUT ;
    USE SIGNAL ;
    PORT
      LAYER M4 ;
        RECT  0 39.12 0.084 39.144 ;
    END
  END ra[53]
  PIN ra[54]
    DIRECTION INPUT ;
    USE SIGNAL ;
    PORT
      LAYER M4 ;
        RECT  0 39.216 0.084 39.24 ;
    END
  END ra[54]
  PIN ra[55]
    DIRECTION INPUT ;
    USE SIGNAL ;
    PORT
      LAYER M4 ;
        RECT  0 39.312 0.084 39.336 ;
    END
  END ra[55]
  PIN ra[56]
    DIRECTION INPUT ;
    USE SIGNAL ;
    PORT
      LAYER M4 ;
        RECT  0 39.408 0.084 39.432 ;
    END
  END ra[56]
  PIN ra[57]
    DIRECTION INPUT ;
    USE SIGNAL ;
    PORT
      LAYER M4 ;
        RECT  0 39.504 0.084 39.528 ;
    END
  END ra[57]
  PIN ra[58]
    DIRECTION INPUT ;
    USE SIGNAL ;
    PORT
      LAYER M4 ;
        RECT  0 39.6 0.084 39.624 ;
    END
  END ra[58]
  PIN ra[59]
    DIRECTION INPUT ;
    USE SIGNAL ;
    PORT
      LAYER M4 ;
        RECT  0 39.696 0.084 39.72 ;
    END
  END ra[59]
  PIN ra[5]
    DIRECTION INPUT ;
    USE SIGNAL ;
    PORT
      LAYER M4 ;
        RECT  0 46.8 0.084 46.824 ;
    END
  END ra[5]
  PIN ra[60]
    DIRECTION INPUT ;
    USE SIGNAL ;
    PORT
      LAYER M4 ;
        RECT  0 39.792 0.084 39.816 ;
    END
  END ra[60]
  PIN ra[61]
    DIRECTION INPUT ;
    USE SIGNAL ;
    PORT
      LAYER M4 ;
        RECT  0 39.888 0.084 39.912 ;
    END
  END ra[61]
  PIN ra[62]
    DIRECTION INPUT ;
    USE SIGNAL ;
    PORT
      LAYER M4 ;
        RECT  0 11.568 0.084 11.592 ;
    END
  END ra[62]
  PIN ra[63]
    DIRECTION INPUT ;
    USE SIGNAL ;
    PORT
      LAYER M4 ;
        RECT  0 11.664 0.084 11.688 ;
    END
  END ra[63]
  PIN ra[6]
    DIRECTION INPUT ;
    USE SIGNAL ;
    PORT
      LAYER M4 ;
        RECT  0 46.896 0.084 46.92 ;
    END
  END ra[6]
  PIN ra[7]
    DIRECTION INPUT ;
    USE SIGNAL ;
    PORT
      LAYER M4 ;
        RECT  0 46.992 0.084 47.016 ;
    END
  END ra[7]
  PIN ra[8]
    DIRECTION INPUT ;
    USE SIGNAL ;
    PORT
      LAYER M4 ;
        RECT  0 47.088 0.084 47.112 ;
    END
  END ra[8]
  PIN ra[9]
    DIRECTION INPUT ;
    USE SIGNAL ;
    PORT
      LAYER M4 ;
        RECT  0 47.184 0.084 47.208 ;
    END
  END ra[9]
  PIN rdc[0]
    DIRECTION OUTPUT ;
    USE SIGNAL ;
    PORT
      LAYER M4 ;
        RECT  38.796 17.712 38.88 17.736 ;
    END
  END rdc[0]
  PIN rdc[1]
    DIRECTION OUTPUT ;
    USE SIGNAL ;
    PORT
      LAYER M4 ;
        RECT  38.796 17.808 38.88 17.832 ;
    END
  END rdc[1]
  PIN rdc[2]
    DIRECTION OUTPUT ;
    USE SIGNAL ;
    PORT
      LAYER M4 ;
        RECT  38.796 17.904 38.88 17.928 ;
    END
  END rdc[2]
  PIN rdc[3]
    DIRECTION OUTPUT ;
    USE SIGNAL ;
    PORT
      LAYER M4 ;
        RECT  38.796 18 38.88 18.024 ;
    END
  END rdc[3]
  PIN rdc[4]
    DIRECTION OUTPUT ;
    USE SIGNAL ;
    PORT
      LAYER M4 ;
        RECT  38.796 18.096 38.88 18.12 ;
    END
  END rdc[4]
  PIN rdc[5]
    DIRECTION OUTPUT ;
    USE SIGNAL ;
    PORT
      LAYER M4 ;
        RECT  38.796 18.192 38.88 18.216 ;
    END
  END rdc[5]
  PIN re[0]
    DIRECTION INPUT ;
    USE SIGNAL ;
    PORT
      LAYER M4 ;
        RECT  0 11.76 0.084 11.784 ;
    END
  END re[0]
  PIN re[1]
    DIRECTION INPUT ;
    USE SIGNAL ;
    PORT
      LAYER M4 ;
        RECT  0 11.856 0.084 11.88 ;
    END
  END re[1]
  PIN re[2]
    DIRECTION INPUT ;
    USE SIGNAL ;
    PORT
      LAYER M4 ;
        RECT  0 11.952 0.084 11.976 ;
    END
  END re[2]
  PIN re[3]
    DIRECTION INPUT ;
    USE SIGNAL ;
    PORT
      LAYER M4 ;
        RECT  0 12.048 0.084 12.072 ;
    END
  END re[3]
  PIN re[4]
    DIRECTION INPUT ;
    USE SIGNAL ;
    PORT
      LAYER M4 ;
        RECT  0 12.144 0.084 12.168 ;
    END
  END re[4]
  PIN re[5]
    DIRECTION INPUT ;
    USE SIGNAL ;
    PORT
      LAYER M4 ;
        RECT  0 12.24 0.084 12.264 ;
    END
  END re[5]
  PIN re[6]
    DIRECTION INPUT ;
    USE SIGNAL ;
    PORT
      LAYER M4 ;
        RECT  0 12.336 0.084 12.36 ;
    END
  END re[6]
  PIN re[7]
    DIRECTION INPUT ;
    USE SIGNAL ;
    PORT
      LAYER M4 ;
        RECT  0 12.432 0.084 12.456 ;
    END
  END re[7]
  PIN rq
    DIRECTION INPUT ;
    USE SIGNAL ;
    PORT
      LAYER M4 ;
        RECT  0 12.528 0.084 12.552 ;
    END
  END rq
  PIN rqb[0]
    DIRECTION INPUT ;
    USE SIGNAL ;
    PORT
      LAYER M4 ;
        RECT  0 12.624 0.084 12.648 ;
    END
  END rqb[0]
  PIN rqb[1]
    DIRECTION INPUT ;
    USE SIGNAL ;
    PORT
      LAYER M4 ;
        RECT  0 12.72 0.084 12.744 ;
    END
  END rqb[1]
  PIN rqb[2]
    DIRECTION INPUT ;
    USE SIGNAL ;
    PORT
      LAYER M4 ;
        RECT  0 12.816 0.084 12.84 ;
    END
  END rqb[2]
  PIN rst_n
    DIRECTION INPUT ;
    USE SIGNAL ;
    PORT
      LAYER M5 ;
        RECT  24.432 0 24.456 0.084 ;
    END
  END rst_n
  PIN rtg[0]
    DIRECTION OUTPUT ;
    USE SIGNAL ;
    PORT
      LAYER M4 ;
        RECT  38.796 18.288 38.88 18.312 ;
    END
  END rtg[0]
  PIN rtg[1]
    DIRECTION OUTPUT ;
    USE SIGNAL ;
    PORT
      LAYER M4 ;
        RECT  38.796 18.384 38.88 18.408 ;
    END
  END rtg[1]
  PIN rtg[2]
    DIRECTION OUTPUT ;
    USE SIGNAL ;
    PORT
      LAYER M4 ;
        RECT  38.796 18.48 38.88 18.504 ;
    END
  END rtg[2]
  PIN rtg[3]
    DIRECTION OUTPUT ;
    USE SIGNAL ;
    PORT
      LAYER M4 ;
        RECT  38.796 18.576 38.88 18.6 ;
    END
  END rtg[3]
  PIN rtg[4]
    DIRECTION OUTPUT ;
    USE SIGNAL ;
    PORT
      LAYER M4 ;
        RECT  38.796 18.672 38.88 18.696 ;
    END
  END rtg[4]
  PIN rtg[5]
    DIRECTION OUTPUT ;
    USE SIGNAL ;
    PORT
      LAYER M4 ;
        RECT  38.796 18.768 38.88 18.792 ;
    END
  END rtg[5]
  PIN rtg[6]
    DIRECTION OUTPUT ;
    USE SIGNAL ;
    PORT
      LAYER M4 ;
        RECT  38.796 18.864 38.88 18.888 ;
    END
  END rtg[6]
  PIN rtg[7]
    DIRECTION OUTPUT ;
    USE SIGNAL ;
    PORT
      LAYER M4 ;
        RECT  38.796 18.96 38.88 18.984 ;
    END
  END rtg[7]
  PIN sra[0]
    DIRECTION INPUT ;
    USE SIGNAL ;
    PORT
      LAYER M4 ;
        RECT  0 12.912 0.084 12.936 ;
    END
  END sra[0]
  PIN sra[10]
    DIRECTION INPUT ;
    USE SIGNAL ;
    PORT
      LAYER M4 ;
        RECT  0 13.872 0.084 13.896 ;
    END
  END sra[10]
  PIN sra[11]
    DIRECTION INPUT ;
    USE SIGNAL ;
    PORT
      LAYER M4 ;
        RECT  0 13.968 0.084 13.992 ;
    END
  END sra[11]
  PIN sra[12]
    DIRECTION INPUT ;
    USE SIGNAL ;
    PORT
      LAYER M4 ;
        RECT  0 14.064 0.084 14.088 ;
    END
  END sra[12]
  PIN sra[13]
    DIRECTION INPUT ;
    USE SIGNAL ;
    PORT
      LAYER M4 ;
        RECT  0 14.16 0.084 14.184 ;
    END
  END sra[13]
  PIN sra[14]
    DIRECTION INPUT ;
    USE SIGNAL ;
    PORT
      LAYER M4 ;
        RECT  0 14.256 0.084 14.28 ;
    END
  END sra[14]
  PIN sra[15]
    DIRECTION INPUT ;
    USE SIGNAL ;
    PORT
      LAYER M4 ;
        RECT  0 14.352 0.084 14.376 ;
    END
  END sra[15]
  PIN sra[16]
    DIRECTION INPUT ;
    USE SIGNAL ;
    PORT
      LAYER M4 ;
        RECT  0 14.448 0.084 14.472 ;
    END
  END sra[16]
  PIN sra[17]
    DIRECTION INPUT ;
    USE SIGNAL ;
    PORT
      LAYER M4 ;
        RECT  0 14.544 0.084 14.568 ;
    END
  END sra[17]
  PIN sra[18]
    DIRECTION INPUT ;
    USE SIGNAL ;
    PORT
      LAYER M4 ;
        RECT  0 14.64 0.084 14.664 ;
    END
  END sra[18]
  PIN sra[19]
    DIRECTION INPUT ;
    USE SIGNAL ;
    PORT
      LAYER M4 ;
        RECT  0 14.736 0.084 14.76 ;
    END
  END sra[19]
  PIN sra[1]
    DIRECTION INPUT ;
    USE SIGNAL ;
    PORT
      LAYER M4 ;
        RECT  0 13.008 0.084 13.032 ;
    END
  END sra[1]
  PIN sra[20]
    DIRECTION INPUT ;
    USE SIGNAL ;
    PORT
      LAYER M4 ;
        RECT  0 14.832 0.084 14.856 ;
    END
  END sra[20]
  PIN sra[21]
    DIRECTION INPUT ;
    USE SIGNAL ;
    PORT
      LAYER M4 ;
        RECT  0 14.928 0.084 14.952 ;
    END
  END sra[21]
  PIN sra[22]
    DIRECTION INPUT ;
    USE SIGNAL ;
    PORT
      LAYER M4 ;
        RECT  0 15.024 0.084 15.048 ;
    END
  END sra[22]
  PIN sra[23]
    DIRECTION INPUT ;
    USE SIGNAL ;
    PORT
      LAYER M4 ;
        RECT  0 15.12 0.084 15.144 ;
    END
  END sra[23]
  PIN sra[24]
    DIRECTION INPUT ;
    USE SIGNAL ;
    PORT
      LAYER M4 ;
        RECT  0 15.216 0.084 15.24 ;
    END
  END sra[24]
  PIN sra[25]
    DIRECTION INPUT ;
    USE SIGNAL ;
    PORT
      LAYER M4 ;
        RECT  0 15.312 0.084 15.336 ;
    END
  END sra[25]
  PIN sra[26]
    DIRECTION INPUT ;
    USE SIGNAL ;
    PORT
      LAYER M4 ;
        RECT  0 15.408 0.084 15.432 ;
    END
  END sra[26]
  PIN sra[27]
    DIRECTION INPUT ;
    USE SIGNAL ;
    PORT
      LAYER M4 ;
        RECT  0 15.504 0.084 15.528 ;
    END
  END sra[27]
  PIN sra[28]
    DIRECTION INPUT ;
    USE SIGNAL ;
    PORT
      LAYER M4 ;
        RECT  0 15.6 0.084 15.624 ;
    END
  END sra[28]
  PIN sra[29]
    DIRECTION INPUT ;
    USE SIGNAL ;
    PORT
      LAYER M4 ;
        RECT  0 15.696 0.084 15.72 ;
    END
  END sra[29]
  PIN sra[2]
    DIRECTION INPUT ;
    USE SIGNAL ;
    PORT
      LAYER M4 ;
        RECT  0 13.104 0.084 13.128 ;
    END
  END sra[2]
  PIN sra[30]
    DIRECTION INPUT ;
    USE SIGNAL ;
    PORT
      LAYER M4 ;
        RECT  0 15.792 0.084 15.816 ;
    END
  END sra[30]
  PIN sra[31]
    DIRECTION INPUT ;
    USE SIGNAL ;
    PORT
      LAYER M4 ;
        RECT  0 15.888 0.084 15.912 ;
    END
  END sra[31]
  PIN sra[32]
    DIRECTION INPUT ;
    USE SIGNAL ;
    PORT
      LAYER M4 ;
        RECT  0 15.984 0.084 16.008 ;
    END
  END sra[32]
  PIN sra[33]
    DIRECTION INPUT ;
    USE SIGNAL ;
    PORT
      LAYER M4 ;
        RECT  0 16.08 0.084 16.104 ;
    END
  END sra[33]
  PIN sra[34]
    DIRECTION INPUT ;
    USE SIGNAL ;
    PORT
      LAYER M4 ;
        RECT  0 16.176 0.084 16.2 ;
    END
  END sra[34]
  PIN sra[35]
    DIRECTION INPUT ;
    USE SIGNAL ;
    PORT
      LAYER M4 ;
        RECT  0 16.272 0.084 16.296 ;
    END
  END sra[35]
  PIN sra[36]
    DIRECTION INPUT ;
    USE SIGNAL ;
    PORT
      LAYER M4 ;
        RECT  0 16.368 0.084 16.392 ;
    END
  END sra[36]
  PIN sra[37]
    DIRECTION INPUT ;
    USE SIGNAL ;
    PORT
      LAYER M4 ;
        RECT  0 16.464 0.084 16.488 ;
    END
  END sra[37]
  PIN sra[38]
    DIRECTION INPUT ;
    USE SIGNAL ;
    PORT
      LAYER M4 ;
        RECT  0 16.56 0.084 16.584 ;
    END
  END sra[38]
  PIN sra[39]
    DIRECTION INPUT ;
    USE SIGNAL ;
    PORT
      LAYER M4 ;
        RECT  0 16.656 0.084 16.68 ;
    END
  END sra[39]
  PIN sra[3]
    DIRECTION INPUT ;
    USE SIGNAL ;
    PORT
      LAYER M4 ;
        RECT  0 13.2 0.084 13.224 ;
    END
  END sra[3]
  PIN sra[40]
    DIRECTION INPUT ;
    USE SIGNAL ;
    PORT
      LAYER M4 ;
        RECT  0 16.752 0.084 16.776 ;
    END
  END sra[40]
  PIN sra[41]
    DIRECTION INPUT ;
    USE SIGNAL ;
    PORT
      LAYER M4 ;
        RECT  0 16.848 0.084 16.872 ;
    END
  END sra[41]
  PIN sra[42]
    DIRECTION INPUT ;
    USE SIGNAL ;
    PORT
      LAYER M4 ;
        RECT  0 16.944 0.084 16.968 ;
    END
  END sra[42]
  PIN sra[43]
    DIRECTION INPUT ;
    USE SIGNAL ;
    PORT
      LAYER M4 ;
        RECT  0 17.04 0.084 17.064 ;
    END
  END sra[43]
  PIN sra[44]
    DIRECTION INPUT ;
    USE SIGNAL ;
    PORT
      LAYER M4 ;
        RECT  0 17.136 0.084 17.16 ;
    END
  END sra[44]
  PIN sra[45]
    DIRECTION INPUT ;
    USE SIGNAL ;
    PORT
      LAYER M4 ;
        RECT  0 17.232 0.084 17.256 ;
    END
  END sra[45]
  PIN sra[46]
    DIRECTION INPUT ;
    USE SIGNAL ;
    PORT
      LAYER M4 ;
        RECT  0 17.328 0.084 17.352 ;
    END
  END sra[46]
  PIN sra[47]
    DIRECTION INPUT ;
    USE SIGNAL ;
    PORT
      LAYER M4 ;
        RECT  0 17.424 0.084 17.448 ;
    END
  END sra[47]
  PIN sra[48]
    DIRECTION INPUT ;
    USE SIGNAL ;
    PORT
      LAYER M4 ;
        RECT  0 17.52 0.084 17.544 ;
    END
  END sra[48]
  PIN sra[49]
    DIRECTION INPUT ;
    USE SIGNAL ;
    PORT
      LAYER M4 ;
        RECT  0 17.616 0.084 17.64 ;
    END
  END sra[49]
  PIN sra[4]
    DIRECTION INPUT ;
    USE SIGNAL ;
    PORT
      LAYER M4 ;
        RECT  0 13.296 0.084 13.32 ;
    END
  END sra[4]
  PIN sra[50]
    DIRECTION INPUT ;
    USE SIGNAL ;
    PORT
      LAYER M4 ;
        RECT  0 33.84 0.084 33.864 ;
    END
  END sra[50]
  PIN sra[51]
    DIRECTION INPUT ;
    USE SIGNAL ;
    PORT
      LAYER M4 ;
        RECT  0 33.936 0.084 33.96 ;
    END
  END sra[51]
  PIN sra[52]
    DIRECTION INPUT ;
    USE SIGNAL ;
    PORT
      LAYER M4 ;
        RECT  0 34.032 0.084 34.056 ;
    END
  END sra[52]
  PIN sra[53]
    DIRECTION INPUT ;
    USE SIGNAL ;
    PORT
      LAYER M4 ;
        RECT  0 34.128 0.084 34.152 ;
    END
  END sra[53]
  PIN sra[54]
    DIRECTION INPUT ;
    USE SIGNAL ;
    PORT
      LAYER M4 ;
        RECT  0 34.224 0.084 34.248 ;
    END
  END sra[54]
  PIN sra[55]
    DIRECTION INPUT ;
    USE SIGNAL ;
    PORT
      LAYER M4 ;
        RECT  0 34.32 0.084 34.344 ;
    END
  END sra[55]
  PIN sra[56]
    DIRECTION INPUT ;
    USE SIGNAL ;
    PORT
      LAYER M4 ;
        RECT  0 34.416 0.084 34.44 ;
    END
  END sra[56]
  PIN sra[57]
    DIRECTION INPUT ;
    USE SIGNAL ;
    PORT
      LAYER M4 ;
        RECT  0 34.512 0.084 34.536 ;
    END
  END sra[57]
  PIN sra[58]
    DIRECTION INPUT ;
    USE SIGNAL ;
    PORT
      LAYER M4 ;
        RECT  0 34.608 0.084 34.632 ;
    END
  END sra[58]
  PIN sra[59]
    DIRECTION INPUT ;
    USE SIGNAL ;
    PORT
      LAYER M4 ;
        RECT  0 34.704 0.084 34.728 ;
    END
  END sra[59]
  PIN sra[5]
    DIRECTION INPUT ;
    USE SIGNAL ;
    PORT
      LAYER M4 ;
        RECT  0 13.392 0.084 13.416 ;
    END
  END sra[5]
  PIN sra[6]
    DIRECTION INPUT ;
    USE SIGNAL ;
    PORT
      LAYER M4 ;
        RECT  0 13.488 0.084 13.512 ;
    END
  END sra[6]
  PIN sra[7]
    DIRECTION INPUT ;
    USE SIGNAL ;
    PORT
      LAYER M4 ;
        RECT  0 13.584 0.084 13.608 ;
    END
  END sra[7]
  PIN sra[8]
    DIRECTION INPUT ;
    USE SIGNAL ;
    PORT
      LAYER M4 ;
        RECT  0 13.68 0.084 13.704 ;
    END
  END sra[8]
  PIN sra[9]
    DIRECTION INPUT ;
    USE SIGNAL ;
    PORT
      LAYER M4 ;
        RECT  0 13.776 0.084 13.8 ;
    END
  END sra[9]
  PIN sre[0]
    DIRECTION INPUT ;
    USE SIGNAL ;
    PORT
      LAYER M4 ;
        RECT  0 34.8 0.084 34.824 ;
    END
  END sre[0]
  PIN sre[1]
    DIRECTION INPUT ;
    USE SIGNAL ;
    PORT
      LAYER M4 ;
        RECT  0 34.896 0.084 34.92 ;
    END
  END sre[1]
  PIN sre[2]
    DIRECTION INPUT ;
    USE SIGNAL ;
    PORT
      LAYER M4 ;
        RECT  0 34.992 0.084 35.016 ;
    END
  END sre[2]
  PIN sre[3]
    DIRECTION INPUT ;
    USE SIGNAL ;
    PORT
      LAYER M4 ;
        RECT  0 35.088 0.084 35.112 ;
    END
  END sre[3]
  PIN sre[4]
    DIRECTION INPUT ;
    USE SIGNAL ;
    PORT
      LAYER M4 ;
        RECT  0 35.184 0.084 35.208 ;
    END
  END sre[4]
  PIN sre[5]
    DIRECTION INPUT ;
    USE SIGNAL ;
    PORT
      LAYER M4 ;
        RECT  0 35.28 0.084 35.304 ;
    END
  END sre[5]
  PIN sv[0]
    DIRECTION INPUT ;
    USE SIGNAL ;
    PORT
      LAYER M4 ;
        RECT  0 35.376 0.084 35.4 ;
    END
  END sv[0]
  PIN sv[1]
    DIRECTION INPUT ;
    USE SIGNAL ;
    PORT
      LAYER M4 ;
        RECT  0 35.472 0.084 35.496 ;
    END
  END sv[1]
  PIN sv[2]
    DIRECTION INPUT ;
    USE SIGNAL ;
    PORT
      LAYER M4 ;
        RECT  0 35.568 0.084 35.592 ;
    END
  END sv[2]
  PIN svc[0]
    DIRECTION OUTPUT ;
    USE SIGNAL ;
    PORT
      LAYER M4 ;
        RECT  38.796 19.056 38.88 19.08 ;
    END
  END svc[0]
  PIN svc[1]
    DIRECTION OUTPUT ;
    USE SIGNAL ;
    PORT
      LAYER M4 ;
        RECT  38.796 13.008 38.88 13.032 ;
    END
  END svc[1]
  PIN svc[2]
    DIRECTION OUTPUT ;
    USE SIGNAL ;
    PORT
      LAYER M4 ;
        RECT  38.796 13.104 38.88 13.128 ;
    END
  END svc[2]
  PIN swe[0]
    DIRECTION INPUT ;
    USE SIGNAL ;
    PORT
      LAYER M4 ;
        RECT  0 35.664 0.084 35.688 ;
    END
  END swe[0]
  PIN swe[1]
    DIRECTION INPUT ;
    USE SIGNAL ;
    PORT
      LAYER M4 ;
        RECT  0 35.76 0.084 35.784 ;
    END
  END swe[1]
  PIN swl[0]
    DIRECTION INPUT ;
    USE SIGNAL ;
    PORT
      LAYER M4 ;
        RECT  0 35.856 0.084 35.88 ;
    END
  END swl[0]
  PIN swl[10]
    DIRECTION INPUT ;
    USE SIGNAL ;
    PORT
      LAYER M4 ;
        RECT  0 36.816 0.084 36.84 ;
    END
  END swl[10]
  PIN swl[11]
    DIRECTION INPUT ;
    USE SIGNAL ;
    PORT
      LAYER M4 ;
        RECT  0 39.984 0.084 40.008 ;
    END
  END swl[11]
  PIN swl[12]
    DIRECTION INPUT ;
    USE SIGNAL ;
    PORT
      LAYER M4 ;
        RECT  0 40.08 0.084 40.104 ;
    END
  END swl[12]
  PIN swl[13]
    DIRECTION INPUT ;
    USE SIGNAL ;
    PORT
      LAYER M4 ;
        RECT  0 40.176 0.084 40.2 ;
    END
  END swl[13]
  PIN swl[14]
    DIRECTION INPUT ;
    USE SIGNAL ;
    PORT
      LAYER M4 ;
        RECT  0 40.272 0.084 40.296 ;
    END
  END swl[14]
  PIN swl[15]
    DIRECTION INPUT ;
    USE SIGNAL ;
    PORT
      LAYER M4 ;
        RECT  0 40.368 0.084 40.392 ;
    END
  END swl[15]
  PIN swl[16]
    DIRECTION INPUT ;
    USE SIGNAL ;
    PORT
      LAYER M4 ;
        RECT  0 40.464 0.084 40.488 ;
    END
  END swl[16]
  PIN swl[17]
    DIRECTION INPUT ;
    USE SIGNAL ;
    PORT
      LAYER M4 ;
        RECT  0 40.56 0.084 40.584 ;
    END
  END swl[17]
  PIN swl[18]
    DIRECTION INPUT ;
    USE SIGNAL ;
    PORT
      LAYER M4 ;
        RECT  0 40.656 0.084 40.68 ;
    END
  END swl[18]
  PIN swl[19]
    DIRECTION INPUT ;
    USE SIGNAL ;
    PORT
      LAYER M4 ;
        RECT  0 40.752 0.084 40.776 ;
    END
  END swl[19]
  PIN swl[1]
    DIRECTION INPUT ;
    USE SIGNAL ;
    PORT
      LAYER M4 ;
        RECT  0 35.952 0.084 35.976 ;
    END
  END swl[1]
  PIN swl[2]
    DIRECTION INPUT ;
    USE SIGNAL ;
    PORT
      LAYER M4 ;
        RECT  0 36.048 0.084 36.072 ;
    END
  END swl[2]
  PIN swl[3]
    DIRECTION INPUT ;
    USE SIGNAL ;
    PORT
      LAYER M4 ;
        RECT  0 36.144 0.084 36.168 ;
    END
  END swl[3]
  PIN swl[4]
    DIRECTION INPUT ;
    USE SIGNAL ;
    PORT
      LAYER M4 ;
        RECT  0 36.24 0.084 36.264 ;
    END
  END swl[4]
  PIN swl[5]
    DIRECTION INPUT ;
    USE SIGNAL ;
    PORT
      LAYER M4 ;
        RECT  0 36.336 0.084 36.36 ;
    END
  END swl[5]
  PIN swl[6]
    DIRECTION INPUT ;
    USE SIGNAL ;
    PORT
      LAYER M4 ;
        RECT  0 36.432 0.084 36.456 ;
    END
  END swl[6]
  PIN swl[7]
    DIRECTION INPUT ;
    USE SIGNAL ;
    PORT
      LAYER M4 ;
        RECT  0 36.528 0.084 36.552 ;
    END
  END swl[7]
  PIN swl[8]
    DIRECTION INPUT ;
    USE SIGNAL ;
    PORT
      LAYER M4 ;
        RECT  0 36.624 0.084 36.648 ;
    END
  END swl[8]
  PIN swl[9]
    DIRECTION INPUT ;
    USE SIGNAL ;
    PORT
      LAYER M4 ;
        RECT  0 36.72 0.084 36.744 ;
    END
  END swl[9]
  PIN swm[0]
    DIRECTION INPUT ;
    USE SIGNAL ;
    PORT
      LAYER M4 ;
        RECT  0 40.848 0.084 40.872 ;
    END
  END swm[0]
  PIN swm[10]
    DIRECTION INPUT ;
    USE SIGNAL ;
    PORT
      LAYER M4 ;
        RECT  0 41.808 0.084 41.832 ;
    END
  END swm[10]
  PIN swm[11]
    DIRECTION INPUT ;
    USE SIGNAL ;
    PORT
      LAYER M4 ;
        RECT  0 41.904 0.084 41.928 ;
    END
  END swm[11]
  PIN swm[12]
    DIRECTION INPUT ;
    USE SIGNAL ;
    PORT
      LAYER M4 ;
        RECT  0 42 0.084 42.024 ;
    END
  END swm[12]
  PIN swm[13]
    DIRECTION INPUT ;
    USE SIGNAL ;
    PORT
      LAYER M4 ;
        RECT  0 42.096 0.084 42.12 ;
    END
  END swm[13]
  PIN swm[14]
    DIRECTION INPUT ;
    USE SIGNAL ;
    PORT
      LAYER M4 ;
        RECT  0 42.192 0.084 42.216 ;
    END
  END swm[14]
  PIN swm[15]
    DIRECTION INPUT ;
    USE SIGNAL ;
    PORT
      LAYER M4 ;
        RECT  0 42.288 0.084 42.312 ;
    END
  END swm[15]
  PIN swm[16]
    DIRECTION INPUT ;
    USE SIGNAL ;
    PORT
      LAYER M4 ;
        RECT  0 42.384 0.084 42.408 ;
    END
  END swm[16]
  PIN swm[17]
    DIRECTION INPUT ;
    USE SIGNAL ;
    PORT
      LAYER M4 ;
        RECT  0 42.48 0.084 42.504 ;
    END
  END swm[17]
  PIN swm[18]
    DIRECTION INPUT ;
    USE SIGNAL ;
    PORT
      LAYER M4 ;
        RECT  0 42.576 0.084 42.6 ;
    END
  END swm[18]
  PIN swm[19]
    DIRECTION INPUT ;
    USE SIGNAL ;
    PORT
      LAYER M4 ;
        RECT  0 42.672 0.084 42.696 ;
    END
  END swm[19]
  PIN swm[1]
    DIRECTION INPUT ;
    USE SIGNAL ;
    PORT
      LAYER M4 ;
        RECT  0 40.944 0.084 40.968 ;
    END
  END swm[1]
  PIN swm[20]
    DIRECTION INPUT ;
    USE SIGNAL ;
    PORT
      LAYER M4 ;
        RECT  0 42.768 0.084 42.792 ;
    END
  END swm[20]
  PIN swm[21]
    DIRECTION INPUT ;
    USE SIGNAL ;
    PORT
      LAYER M4 ;
        RECT  0 42.864 0.084 42.888 ;
    END
  END swm[21]
  PIN swm[22]
    DIRECTION INPUT ;
    USE SIGNAL ;
    PORT
      LAYER M4 ;
        RECT  0 42.96 0.084 42.984 ;
    END
  END swm[22]
  PIN swm[23]
    DIRECTION INPUT ;
    USE SIGNAL ;
    PORT
      LAYER M4 ;
        RECT  0 43.056 0.084 43.08 ;
    END
  END swm[23]
  PIN swm[24]
    DIRECTION INPUT ;
    USE SIGNAL ;
    PORT
      LAYER M4 ;
        RECT  0 43.152 0.084 43.176 ;
    END
  END swm[24]
  PIN swm[25]
    DIRECTION INPUT ;
    USE SIGNAL ;
    PORT
      LAYER M4 ;
        RECT  0 43.248 0.084 43.272 ;
    END
  END swm[25]
  PIN swm[26]
    DIRECTION INPUT ;
    USE SIGNAL ;
    PORT
      LAYER M4 ;
        RECT  0 43.344 0.084 43.368 ;
    END
  END swm[26]
  PIN swm[27]
    DIRECTION INPUT ;
    USE SIGNAL ;
    PORT
      LAYER M4 ;
        RECT  0 43.44 0.084 43.464 ;
    END
  END swm[27]
  PIN swm[28]
    DIRECTION INPUT ;
    USE SIGNAL ;
    PORT
      LAYER M4 ;
        RECT  0 43.536 0.084 43.56 ;
    END
  END swm[28]
  PIN swm[29]
    DIRECTION INPUT ;
    USE SIGNAL ;
    PORT
      LAYER M4 ;
        RECT  0 43.632 0.084 43.656 ;
    END
  END swm[29]
  PIN swm[2]
    DIRECTION INPUT ;
    USE SIGNAL ;
    PORT
      LAYER M4 ;
        RECT  0 41.04 0.084 41.064 ;
    END
  END swm[2]
  PIN swm[30]
    DIRECTION INPUT ;
    USE SIGNAL ;
    PORT
      LAYER M4 ;
        RECT  0 43.728 0.084 43.752 ;
    END
  END swm[30]
  PIN swm[31]
    DIRECTION INPUT ;
    USE SIGNAL ;
    PORT
      LAYER M4 ;
        RECT  0 43.824 0.084 43.848 ;
    END
  END swm[31]
  PIN swm[3]
    DIRECTION INPUT ;
    USE SIGNAL ;
    PORT
      LAYER M4 ;
        RECT  0 41.136 0.084 41.16 ;
    END
  END swm[3]
  PIN swm[4]
    DIRECTION INPUT ;
    USE SIGNAL ;
    PORT
      LAYER M4 ;
        RECT  0 41.232 0.084 41.256 ;
    END
  END swm[4]
  PIN swm[5]
    DIRECTION INPUT ;
    USE SIGNAL ;
    PORT
      LAYER M4 ;
        RECT  0 41.328 0.084 41.352 ;
    END
  END swm[5]
  PIN swm[6]
    DIRECTION INPUT ;
    USE SIGNAL ;
    PORT
      LAYER M4 ;
        RECT  0 41.424 0.084 41.448 ;
    END
  END swm[6]
  PIN swm[7]
    DIRECTION INPUT ;
    USE SIGNAL ;
    PORT
      LAYER M4 ;
        RECT  0 41.52 0.084 41.544 ;
    END
  END swm[7]
  PIN swm[8]
    DIRECTION INPUT ;
    USE SIGNAL ;
    PORT
      LAYER M4 ;
        RECT  0 41.616 0.084 41.64 ;
    END
  END swm[8]
  PIN swm[9]
    DIRECTION INPUT ;
    USE SIGNAL ;
    PORT
      LAYER M4 ;
        RECT  0 41.712 0.084 41.736 ;
    END
  END swm[9]
  PIN we[0]
    DIRECTION INPUT ;
    USE SIGNAL ;
    PORT
      LAYER M4 ;
        RECT  0 43.92 0.084 43.944 ;
    END
  END we[0]
  PIN we[1]
    DIRECTION INPUT ;
    USE SIGNAL ;
    PORT
      LAYER M4 ;
        RECT  0 44.016 0.084 44.04 ;
    END
  END we[1]
  PIN we[2]
    DIRECTION INPUT ;
    USE SIGNAL ;
    PORT
      LAYER M4 ;
        RECT  0 44.112 0.084 44.136 ;
    END
  END we[2]
  PIN we[3]
    DIRECTION INPUT ;
    USE SIGNAL ;
    PORT
      LAYER M4 ;
        RECT  0 44.208 0.084 44.232 ;
    END
  END we[3]
  PIN we[4]
    DIRECTION INPUT ;
    USE SIGNAL ;
    PORT
      LAYER M4 ;
        RECT  0 44.304 0.084 44.328 ;
    END
  END we[4]
  PIN we[5]
    DIRECTION INPUT ;
    USE SIGNAL ;
    PORT
      LAYER M4 ;
        RECT  0 44.4 0.084 44.424 ;
    END
  END we[5]
  PIN we[6]
    DIRECTION INPUT ;
    USE SIGNAL ;
    PORT
      LAYER M4 ;
        RECT  0 44.496 0.084 44.52 ;
    END
  END we[6]
  PIN we[7]
    DIRECTION INPUT ;
    USE SIGNAL ;
    PORT
      LAYER M4 ;
        RECT  0 44.592 0.084 44.616 ;
    END
  END we[7]
  PIN wl[0]
    DIRECTION INPUT ;
    USE SIGNAL ;
    PORT
      LAYER M4 ;
        RECT  0 44.688 0.084 44.712 ;
    END
  END wl[0]
  PIN wl[10]
    DIRECTION INPUT ;
    USE SIGNAL ;
    PORT
      LAYER M4 ;
        RECT  0 45.648 0.084 45.672 ;
    END
  END wl[10]
  PIN wl[11]
    DIRECTION INPUT ;
    USE SIGNAL ;
    PORT
      LAYER M4 ;
        RECT  0 45.744 0.084 45.768 ;
    END
  END wl[11]
  PIN wl[12]
    DIRECTION INPUT ;
    USE SIGNAL ;
    PORT
      LAYER M4 ;
        RECT  0 45.84 0.084 45.864 ;
    END
  END wl[12]
  PIN wl[13]
    DIRECTION INPUT ;
    USE SIGNAL ;
    PORT
      LAYER M4 ;
        RECT  0 45.936 0.084 45.96 ;
    END
  END wl[13]
  PIN wl[14]
    DIRECTION INPUT ;
    USE SIGNAL ;
    PORT
      LAYER M4 ;
        RECT  0 46.032 0.084 46.056 ;
    END
  END wl[14]
  PIN wl[15]
    DIRECTION INPUT ;
    USE SIGNAL ;
    PORT
      LAYER M4 ;
        RECT  0 30.768 0.084 30.792 ;
    END
  END wl[15]
  PIN wl[16]
    DIRECTION INPUT ;
    USE SIGNAL ;
    PORT
      LAYER M4 ;
        RECT  0 30.864 0.084 30.888 ;
    END
  END wl[16]
  PIN wl[17]
    DIRECTION INPUT ;
    USE SIGNAL ;
    PORT
      LAYER M4 ;
        RECT  0 30.96 0.084 30.984 ;
    END
  END wl[17]
  PIN wl[18]
    DIRECTION INPUT ;
    USE SIGNAL ;
    PORT
      LAYER M4 ;
        RECT  0 31.056 0.084 31.08 ;
    END
  END wl[18]
  PIN wl[19]
    DIRECTION INPUT ;
    USE SIGNAL ;
    PORT
      LAYER M4 ;
        RECT  0 31.152 0.084 31.176 ;
    END
  END wl[19]
  PIN wl[1]
    DIRECTION INPUT ;
    USE SIGNAL ;
    PORT
      LAYER M4 ;
        RECT  0 44.784 0.084 44.808 ;
    END
  END wl[1]
  PIN wl[20]
    DIRECTION INPUT ;
    USE SIGNAL ;
    PORT
      LAYER M4 ;
        RECT  0 31.248 0.084 31.272 ;
    END
  END wl[20]
  PIN wl[21]
    DIRECTION INPUT ;
    USE SIGNAL ;
    PORT
      LAYER M4 ;
        RECT  0 31.344 0.084 31.368 ;
    END
  END wl[21]
  PIN wl[22]
    DIRECTION INPUT ;
    USE SIGNAL ;
    PORT
      LAYER M4 ;
        RECT  0 31.44 0.084 31.464 ;
    END
  END wl[22]
  PIN wl[23]
    DIRECTION INPUT ;
    USE SIGNAL ;
    PORT
      LAYER M4 ;
        RECT  0 31.536 0.084 31.56 ;
    END
  END wl[23]
  PIN wl[24]
    DIRECTION INPUT ;
    USE SIGNAL ;
    PORT
      LAYER M4 ;
        RECT  0 31.632 0.084 31.656 ;
    END
  END wl[24]
  PIN wl[25]
    DIRECTION INPUT ;
    USE SIGNAL ;
    PORT
      LAYER M4 ;
        RECT  0 31.728 0.084 31.752 ;
    END
  END wl[25]
  PIN wl[26]
    DIRECTION INPUT ;
    USE SIGNAL ;
    PORT
      LAYER M4 ;
        RECT  0 31.824 0.084 31.848 ;
    END
  END wl[26]
  PIN wl[27]
    DIRECTION INPUT ;
    USE SIGNAL ;
    PORT
      LAYER M4 ;
        RECT  0 31.92 0.084 31.944 ;
    END
  END wl[27]
  PIN wl[28]
    DIRECTION INPUT ;
    USE SIGNAL ;
    PORT
      LAYER M4 ;
        RECT  0 32.016 0.084 32.04 ;
    END
  END wl[28]
  PIN wl[29]
    DIRECTION INPUT ;
    USE SIGNAL ;
    PORT
      LAYER M4 ;
        RECT  0 32.112 0.084 32.136 ;
    END
  END wl[29]
  PIN wl[2]
    DIRECTION INPUT ;
    USE SIGNAL ;
    PORT
      LAYER M4 ;
        RECT  0 44.88 0.084 44.904 ;
    END
  END wl[2]
  PIN wl[30]
    DIRECTION INPUT ;
    USE SIGNAL ;
    PORT
      LAYER M4 ;
        RECT  0 32.208 0.084 32.232 ;
    END
  END wl[30]
  PIN wl[31]
    DIRECTION INPUT ;
    USE SIGNAL ;
    PORT
      LAYER M4 ;
        RECT  0 32.304 0.084 32.328 ;
    END
  END wl[31]
  PIN wl[32]
    DIRECTION INPUT ;
    USE SIGNAL ;
    PORT
      LAYER M4 ;
        RECT  0 32.4 0.084 32.424 ;
    END
  END wl[32]
  PIN wl[33]
    DIRECTION INPUT ;
    USE SIGNAL ;
    PORT
      LAYER M4 ;
        RECT  0 32.496 0.084 32.52 ;
    END
  END wl[33]
  PIN wl[34]
    DIRECTION INPUT ;
    USE SIGNAL ;
    PORT
      LAYER M4 ;
        RECT  0 32.592 0.084 32.616 ;
    END
  END wl[34]
  PIN wl[35]
    DIRECTION INPUT ;
    USE SIGNAL ;
    PORT
      LAYER M4 ;
        RECT  0 32.688 0.084 32.712 ;
    END
  END wl[35]
  PIN wl[36]
    DIRECTION INPUT ;
    USE SIGNAL ;
    PORT
      LAYER M4 ;
        RECT  0 32.784 0.084 32.808 ;
    END
  END wl[36]
  PIN wl[37]
    DIRECTION INPUT ;
    USE SIGNAL ;
    PORT
      LAYER M4 ;
        RECT  0 32.88 0.084 32.904 ;
    END
  END wl[37]
  PIN wl[38]
    DIRECTION INPUT ;
    USE SIGNAL ;
    PORT
      LAYER M4 ;
        RECT  0 32.976 0.084 33 ;
    END
  END wl[38]
  PIN wl[39]
    DIRECTION INPUT ;
    USE SIGNAL ;
    PORT
      LAYER M4 ;
        RECT  0 33.072 0.084 33.096 ;
    END
  END wl[39]
  PIN wl[3]
    DIRECTION INPUT ;
    USE SIGNAL ;
    PORT
      LAYER M4 ;
        RECT  0 44.976 0.084 45 ;
    END
  END wl[3]
  PIN wl[40]
    DIRECTION INPUT ;
    USE SIGNAL ;
    PORT
      LAYER M4 ;
        RECT  0 33.168 0.084 33.192 ;
    END
  END wl[40]
  PIN wl[41]
    DIRECTION INPUT ;
    USE SIGNAL ;
    PORT
      LAYER M4 ;
        RECT  0 33.264 0.084 33.288 ;
    END
  END wl[41]
  PIN wl[42]
    DIRECTION INPUT ;
    USE SIGNAL ;
    PORT
      LAYER M4 ;
        RECT  0 33.36 0.084 33.384 ;
    END
  END wl[42]
  PIN wl[43]
    DIRECTION INPUT ;
    USE SIGNAL ;
    PORT
      LAYER M4 ;
        RECT  0 33.456 0.084 33.48 ;
    END
  END wl[43]
  PIN wl[44]
    DIRECTION INPUT ;
    USE SIGNAL ;
    PORT
      LAYER M4 ;
        RECT  0 33.552 0.084 33.576 ;
    END
  END wl[44]
  PIN wl[45]
    DIRECTION INPUT ;
    USE SIGNAL ;
    PORT
      LAYER M4 ;
        RECT  0 33.648 0.084 33.672 ;
    END
  END wl[45]
  PIN wl[46]
    DIRECTION INPUT ;
    USE SIGNAL ;
    PORT
      LAYER M4 ;
        RECT  0 33.744 0.084 33.768 ;
    END
  END wl[46]
  PIN wl[47]
    DIRECTION INPUT ;
    USE SIGNAL ;
    PORT
      LAYER M4 ;
        RECT  0 23.856 0.084 23.88 ;
    END
  END wl[47]
  PIN wl[48]
    DIRECTION INPUT ;
    USE SIGNAL ;
    PORT
      LAYER M4 ;
        RECT  0 23.952 0.084 23.976 ;
    END
  END wl[48]
  PIN wl[49]
    DIRECTION INPUT ;
    USE SIGNAL ;
    PORT
      LAYER M4 ;
        RECT  0 24.048 0.084 24.072 ;
    END
  END wl[49]
  PIN wl[4]
    DIRECTION INPUT ;
    USE SIGNAL ;
    PORT
      LAYER M4 ;
        RECT  0 45.072 0.084 45.096 ;
    END
  END wl[4]
  PIN wl[50]
    DIRECTION INPUT ;
    USE SIGNAL ;
    PORT
      LAYER M4 ;
        RECT  0 24.144 0.084 24.168 ;
    END
  END wl[50]
  PIN wl[51]
    DIRECTION INPUT ;
    USE SIGNAL ;
    PORT
      LAYER M4 ;
        RECT  0 24.24 0.084 24.264 ;
    END
  END wl[51]
  PIN wl[52]
    DIRECTION INPUT ;
    USE SIGNAL ;
    PORT
      LAYER M4 ;
        RECT  0 24.336 0.084 24.36 ;
    END
  END wl[52]
  PIN wl[53]
    DIRECTION INPUT ;
    USE SIGNAL ;
    PORT
      LAYER M4 ;
        RECT  0 24.432 0.084 24.456 ;
    END
  END wl[53]
  PIN wl[54]
    DIRECTION INPUT ;
    USE SIGNAL ;
    PORT
      LAYER M4 ;
        RECT  0 24.528 0.084 24.552 ;
    END
  END wl[54]
  PIN wl[55]
    DIRECTION INPUT ;
    USE SIGNAL ;
    PORT
      LAYER M4 ;
        RECT  0 24.624 0.084 24.648 ;
    END
  END wl[55]
  PIN wl[56]
    DIRECTION INPUT ;
    USE SIGNAL ;
    PORT
      LAYER M4 ;
        RECT  0 24.72 0.084 24.744 ;
    END
  END wl[56]
  PIN wl[57]
    DIRECTION INPUT ;
    USE SIGNAL ;
    PORT
      LAYER M4 ;
        RECT  0 24.816 0.084 24.84 ;
    END
  END wl[57]
  PIN wl[58]
    DIRECTION INPUT ;
    USE SIGNAL ;
    PORT
      LAYER M4 ;
        RECT  0 24.912 0.084 24.936 ;
    END
  END wl[58]
  PIN wl[59]
    DIRECTION INPUT ;
    USE SIGNAL ;
    PORT
      LAYER M4 ;
        RECT  0 25.008 0.084 25.032 ;
    END
  END wl[59]
  PIN wl[5]
    DIRECTION INPUT ;
    USE SIGNAL ;
    PORT
      LAYER M4 ;
        RECT  0 45.168 0.084 45.192 ;
    END
  END wl[5]
  PIN wl[60]
    DIRECTION INPUT ;
    USE SIGNAL ;
    PORT
      LAYER M4 ;
        RECT  0 25.104 0.084 25.128 ;
    END
  END wl[60]
  PIN wl[61]
    DIRECTION INPUT ;
    USE SIGNAL ;
    PORT
      LAYER M4 ;
        RECT  0 25.2 0.084 25.224 ;
    END
  END wl[61]
  PIN wl[62]
    DIRECTION INPUT ;
    USE SIGNAL ;
    PORT
      LAYER M4 ;
        RECT  0 25.296 0.084 25.32 ;
    END
  END wl[62]
  PIN wl[63]
    DIRECTION INPUT ;
    USE SIGNAL ;
    PORT
      LAYER M4 ;
        RECT  0 25.392 0.084 25.416 ;
    END
  END wl[63]
  PIN wl[6]
    DIRECTION INPUT ;
    USE SIGNAL ;
    PORT
      LAYER M4 ;
        RECT  0 45.264 0.084 45.288 ;
    END
  END wl[6]
  PIN wl[7]
    DIRECTION INPUT ;
    USE SIGNAL ;
    PORT
      LAYER M4 ;
        RECT  0 45.36 0.084 45.384 ;
    END
  END wl[7]
  PIN wl[8]
    DIRECTION INPUT ;
    USE SIGNAL ;
    PORT
      LAYER M4 ;
        RECT  0 45.456 0.084 45.48 ;
    END
  END wl[8]
  PIN wl[9]
    DIRECTION INPUT ;
    USE SIGNAL ;
    PORT
      LAYER M4 ;
        RECT  0 45.552 0.084 45.576 ;
    END
  END wl[9]
  PIN wm[0]
    DIRECTION INPUT ;
    USE SIGNAL ;
    PORT
      LAYER M4 ;
        RECT  0 25.488 0.084 25.512 ;
    END
  END wm[0]
  PIN wm[100]
    DIRECTION INPUT ;
    USE SIGNAL ;
    PORT
      LAYER M4 ;
        RECT  0 22.8 0.084 22.824 ;
    END
  END wm[100]
  PIN wm[101]
    DIRECTION INPUT ;
    USE SIGNAL ;
    PORT
      LAYER M4 ;
        RECT  0 22.896 0.084 22.92 ;
    END
  END wm[101]
  PIN wm[102]
    DIRECTION INPUT ;
    USE SIGNAL ;
    PORT
      LAYER M4 ;
        RECT  0 22.992 0.084 23.016 ;
    END
  END wm[102]
  PIN wm[103]
    DIRECTION INPUT ;
    USE SIGNAL ;
    PORT
      LAYER M4 ;
        RECT  0 23.088 0.084 23.112 ;
    END
  END wm[103]
  PIN wm[104]
    DIRECTION INPUT ;
    USE SIGNAL ;
    PORT
      LAYER M4 ;
        RECT  0 23.184 0.084 23.208 ;
    END
  END wm[104]
  PIN wm[105]
    DIRECTION INPUT ;
    USE SIGNAL ;
    PORT
      LAYER M4 ;
        RECT  0 23.28 0.084 23.304 ;
    END
  END wm[105]
  PIN wm[106]
    DIRECTION INPUT ;
    USE SIGNAL ;
    PORT
      LAYER M4 ;
        RECT  0 23.376 0.084 23.4 ;
    END
  END wm[106]
  PIN wm[107]
    DIRECTION INPUT ;
    USE SIGNAL ;
    PORT
      LAYER M4 ;
        RECT  0 23.472 0.084 23.496 ;
    END
  END wm[107]
  PIN wm[108]
    DIRECTION INPUT ;
    USE SIGNAL ;
    PORT
      LAYER M4 ;
        RECT  0 23.568 0.084 23.592 ;
    END
  END wm[108]
  PIN wm[109]
    DIRECTION INPUT ;
    USE SIGNAL ;
    PORT
      LAYER M4 ;
        RECT  0 23.664 0.084 23.688 ;
    END
  END wm[109]
  PIN wm[10]
    DIRECTION INPUT ;
    USE SIGNAL ;
    PORT
      LAYER M4 ;
        RECT  0 26.448 0.084 26.472 ;
    END
  END wm[10]
  PIN wm[110]
    DIRECTION INPUT ;
    USE SIGNAL ;
    PORT
      LAYER M4 ;
        RECT  0 23.76 0.084 23.784 ;
    END
  END wm[110]
  PIN wm[111]
    DIRECTION INPUT ;
    USE SIGNAL ;
    PORT
      LAYER M4 ;
        RECT  0 49.392 0.084 49.416 ;
    END
  END wm[111]
  PIN wm[112]
    DIRECTION INPUT ;
    USE SIGNAL ;
    PORT
      LAYER M4 ;
        RECT  0 49.488 0.084 49.512 ;
    END
  END wm[112]
  PIN wm[113]
    DIRECTION INPUT ;
    USE SIGNAL ;
    PORT
      LAYER M4 ;
        RECT  0 49.584 0.084 49.608 ;
    END
  END wm[113]
  PIN wm[114]
    DIRECTION INPUT ;
    USE SIGNAL ;
    PORT
      LAYER M4 ;
        RECT  0 49.68 0.084 49.704 ;
    END
  END wm[114]
  PIN wm[115]
    DIRECTION INPUT ;
    USE SIGNAL ;
    PORT
      LAYER M4 ;
        RECT  0 49.776 0.084 49.8 ;
    END
  END wm[115]
  PIN wm[116]
    DIRECTION INPUT ;
    USE SIGNAL ;
    PORT
      LAYER M4 ;
        RECT  0 49.872 0.084 49.896 ;
    END
  END wm[116]
  PIN wm[117]
    DIRECTION INPUT ;
    USE SIGNAL ;
    PORT
      LAYER M4 ;
        RECT  0 49.968 0.084 49.992 ;
    END
  END wm[117]
  PIN wm[118]
    DIRECTION INPUT ;
    USE SIGNAL ;
    PORT
      LAYER M4 ;
        RECT  0 50.064 0.084 50.088 ;
    END
  END wm[118]
  PIN wm[119]
    DIRECTION INPUT ;
    USE SIGNAL ;
    PORT
      LAYER M4 ;
        RECT  0 50.16 0.084 50.184 ;
    END
  END wm[119]
  PIN wm[11]
    DIRECTION INPUT ;
    USE SIGNAL ;
    PORT
      LAYER M4 ;
        RECT  0 26.544 0.084 26.568 ;
    END
  END wm[11]
  PIN wm[120]
    DIRECTION INPUT ;
    USE SIGNAL ;
    PORT
      LAYER M4 ;
        RECT  0 50.256 0.084 50.28 ;
    END
  END wm[120]
  PIN wm[121]
    DIRECTION INPUT ;
    USE SIGNAL ;
    PORT
      LAYER M4 ;
        RECT  0 50.352 0.084 50.376 ;
    END
  END wm[121]
  PIN wm[122]
    DIRECTION INPUT ;
    USE SIGNAL ;
    PORT
      LAYER M4 ;
        RECT  0 50.448 0.084 50.472 ;
    END
  END wm[122]
  PIN wm[123]
    DIRECTION INPUT ;
    USE SIGNAL ;
    PORT
      LAYER M4 ;
        RECT  0 50.544 0.084 50.568 ;
    END
  END wm[123]
  PIN wm[124]
    DIRECTION INPUT ;
    USE SIGNAL ;
    PORT
      LAYER M4 ;
        RECT  0 50.64 0.084 50.664 ;
    END
  END wm[124]
  PIN wm[125]
    DIRECTION INPUT ;
    USE SIGNAL ;
    PORT
      LAYER M4 ;
        RECT  0 50.736 0.084 50.76 ;
    END
  END wm[125]
  PIN wm[126]
    DIRECTION INPUT ;
    USE SIGNAL ;
    PORT
      LAYER M4 ;
        RECT  0 50.832 0.084 50.856 ;
    END
  END wm[126]
  PIN wm[127]
    DIRECTION INPUT ;
    USE SIGNAL ;
    PORT
      LAYER M4 ;
        RECT  0 50.928 0.084 50.952 ;
    END
  END wm[127]
  PIN wm[12]
    DIRECTION INPUT ;
    USE SIGNAL ;
    PORT
      LAYER M4 ;
        RECT  0 26.64 0.084 26.664 ;
    END
  END wm[12]
  PIN wm[13]
    DIRECTION INPUT ;
    USE SIGNAL ;
    PORT
      LAYER M4 ;
        RECT  0 26.736 0.084 26.76 ;
    END
  END wm[13]
  PIN wm[14]
    DIRECTION INPUT ;
    USE SIGNAL ;
    PORT
      LAYER M4 ;
        RECT  0 26.832 0.084 26.856 ;
    END
  END wm[14]
  PIN wm[15]
    DIRECTION INPUT ;
    USE SIGNAL ;
    PORT
      LAYER M4 ;
        RECT  0 26.928 0.084 26.952 ;
    END
  END wm[15]
  PIN wm[16]
    DIRECTION INPUT ;
    USE SIGNAL ;
    PORT
      LAYER M4 ;
        RECT  0 27.024 0.084 27.048 ;
    END
  END wm[16]
  PIN wm[17]
    DIRECTION INPUT ;
    USE SIGNAL ;
    PORT
      LAYER M4 ;
        RECT  0 27.12 0.084 27.144 ;
    END
  END wm[17]
  PIN wm[18]
    DIRECTION INPUT ;
    USE SIGNAL ;
    PORT
      LAYER M4 ;
        RECT  0 27.216 0.084 27.24 ;
    END
  END wm[18]
  PIN wm[19]
    DIRECTION INPUT ;
    USE SIGNAL ;
    PORT
      LAYER M4 ;
        RECT  0 27.312 0.084 27.336 ;
    END
  END wm[19]
  PIN wm[1]
    DIRECTION INPUT ;
    USE SIGNAL ;
    PORT
      LAYER M4 ;
        RECT  0 25.584 0.084 25.608 ;
    END
  END wm[1]
  PIN wm[20]
    DIRECTION INPUT ;
    USE SIGNAL ;
    PORT
      LAYER M4 ;
        RECT  0 27.408 0.084 27.432 ;
    END
  END wm[20]
  PIN wm[21]
    DIRECTION INPUT ;
    USE SIGNAL ;
    PORT
      LAYER M4 ;
        RECT  0 27.504 0.084 27.528 ;
    END
  END wm[21]
  PIN wm[22]
    DIRECTION INPUT ;
    USE SIGNAL ;
    PORT
      LAYER M4 ;
        RECT  0 27.6 0.084 27.624 ;
    END
  END wm[22]
  PIN wm[23]
    DIRECTION INPUT ;
    USE SIGNAL ;
    PORT
      LAYER M4 ;
        RECT  0 27.696 0.084 27.72 ;
    END
  END wm[23]
  PIN wm[24]
    DIRECTION INPUT ;
    USE SIGNAL ;
    PORT
      LAYER M4 ;
        RECT  0 27.792 0.084 27.816 ;
    END
  END wm[24]
  PIN wm[25]
    DIRECTION INPUT ;
    USE SIGNAL ;
    PORT
      LAYER M4 ;
        RECT  0 27.888 0.084 27.912 ;
    END
  END wm[25]
  PIN wm[26]
    DIRECTION INPUT ;
    USE SIGNAL ;
    PORT
      LAYER M4 ;
        RECT  0 27.984 0.084 28.008 ;
    END
  END wm[26]
  PIN wm[27]
    DIRECTION INPUT ;
    USE SIGNAL ;
    PORT
      LAYER M4 ;
        RECT  0 28.08 0.084 28.104 ;
    END
  END wm[27]
  PIN wm[28]
    DIRECTION INPUT ;
    USE SIGNAL ;
    PORT
      LAYER M4 ;
        RECT  0 28.176 0.084 28.2 ;
    END
  END wm[28]
  PIN wm[29]
    DIRECTION INPUT ;
    USE SIGNAL ;
    PORT
      LAYER M4 ;
        RECT  0 28.272 0.084 28.296 ;
    END
  END wm[29]
  PIN wm[2]
    DIRECTION INPUT ;
    USE SIGNAL ;
    PORT
      LAYER M4 ;
        RECT  0 25.68 0.084 25.704 ;
    END
  END wm[2]
  PIN wm[30]
    DIRECTION INPUT ;
    USE SIGNAL ;
    PORT
      LAYER M4 ;
        RECT  0 28.368 0.084 28.392 ;
    END
  END wm[30]
  PIN wm[31]
    DIRECTION INPUT ;
    USE SIGNAL ;
    PORT
      LAYER M4 ;
        RECT  0 28.464 0.084 28.488 ;
    END
  END wm[31]
  PIN wm[32]
    DIRECTION INPUT ;
    USE SIGNAL ;
    PORT
      LAYER M4 ;
        RECT  0 28.56 0.084 28.584 ;
    END
  END wm[32]
  PIN wm[33]
    DIRECTION INPUT ;
    USE SIGNAL ;
    PORT
      LAYER M4 ;
        RECT  0 28.656 0.084 28.68 ;
    END
  END wm[33]
  PIN wm[34]
    DIRECTION INPUT ;
    USE SIGNAL ;
    PORT
      LAYER M4 ;
        RECT  0 28.752 0.084 28.776 ;
    END
  END wm[34]
  PIN wm[35]
    DIRECTION INPUT ;
    USE SIGNAL ;
    PORT
      LAYER M4 ;
        RECT  0 28.848 0.084 28.872 ;
    END
  END wm[35]
  PIN wm[36]
    DIRECTION INPUT ;
    USE SIGNAL ;
    PORT
      LAYER M4 ;
        RECT  0 28.944 0.084 28.968 ;
    END
  END wm[36]
  PIN wm[37]
    DIRECTION INPUT ;
    USE SIGNAL ;
    PORT
      LAYER M4 ;
        RECT  0 29.04 0.084 29.064 ;
    END
  END wm[37]
  PIN wm[38]
    DIRECTION INPUT ;
    USE SIGNAL ;
    PORT
      LAYER M4 ;
        RECT  0 29.136 0.084 29.16 ;
    END
  END wm[38]
  PIN wm[39]
    DIRECTION INPUT ;
    USE SIGNAL ;
    PORT
      LAYER M4 ;
        RECT  0 29.232 0.084 29.256 ;
    END
  END wm[39]
  PIN wm[3]
    DIRECTION INPUT ;
    USE SIGNAL ;
    PORT
      LAYER M4 ;
        RECT  0 25.776 0.084 25.8 ;
    END
  END wm[3]
  PIN wm[40]
    DIRECTION INPUT ;
    USE SIGNAL ;
    PORT
      LAYER M4 ;
        RECT  0 29.328 0.084 29.352 ;
    END
  END wm[40]
  PIN wm[41]
    DIRECTION INPUT ;
    USE SIGNAL ;
    PORT
      LAYER M4 ;
        RECT  0 29.424 0.084 29.448 ;
    END
  END wm[41]
  PIN wm[42]
    DIRECTION INPUT ;
    USE SIGNAL ;
    PORT
      LAYER M4 ;
        RECT  0 29.52 0.084 29.544 ;
    END
  END wm[42]
  PIN wm[43]
    DIRECTION INPUT ;
    USE SIGNAL ;
    PORT
      LAYER M4 ;
        RECT  0 29.616 0.084 29.64 ;
    END
  END wm[43]
  PIN wm[44]
    DIRECTION INPUT ;
    USE SIGNAL ;
    PORT
      LAYER M4 ;
        RECT  0 29.712 0.084 29.736 ;
    END
  END wm[44]
  PIN wm[45]
    DIRECTION INPUT ;
    USE SIGNAL ;
    PORT
      LAYER M4 ;
        RECT  0 29.808 0.084 29.832 ;
    END
  END wm[45]
  PIN wm[46]
    DIRECTION INPUT ;
    USE SIGNAL ;
    PORT
      LAYER M4 ;
        RECT  0 29.904 0.084 29.928 ;
    END
  END wm[46]
  PIN wm[47]
    DIRECTION INPUT ;
    USE SIGNAL ;
    PORT
      LAYER M4 ;
        RECT  0 17.712 0.084 17.736 ;
    END
  END wm[47]
  PIN wm[48]
    DIRECTION INPUT ;
    USE SIGNAL ;
    PORT
      LAYER M4 ;
        RECT  0 17.808 0.084 17.832 ;
    END
  END wm[48]
  PIN wm[49]
    DIRECTION INPUT ;
    USE SIGNAL ;
    PORT
      LAYER M4 ;
        RECT  0 17.904 0.084 17.928 ;
    END
  END wm[49]
  PIN wm[4]
    DIRECTION INPUT ;
    USE SIGNAL ;
    PORT
      LAYER M4 ;
        RECT  0 25.872 0.084 25.896 ;
    END
  END wm[4]
  PIN wm[50]
    DIRECTION INPUT ;
    USE SIGNAL ;
    PORT
      LAYER M4 ;
        RECT  0 18 0.084 18.024 ;
    END
  END wm[50]
  PIN wm[51]
    DIRECTION INPUT ;
    USE SIGNAL ;
    PORT
      LAYER M4 ;
        RECT  0 18.096 0.084 18.12 ;
    END
  END wm[51]
  PIN wm[52]
    DIRECTION INPUT ;
    USE SIGNAL ;
    PORT
      LAYER M4 ;
        RECT  0 18.192 0.084 18.216 ;
    END
  END wm[52]
  PIN wm[53]
    DIRECTION INPUT ;
    USE SIGNAL ;
    PORT
      LAYER M4 ;
        RECT  0 18.288 0.084 18.312 ;
    END
  END wm[53]
  PIN wm[54]
    DIRECTION INPUT ;
    USE SIGNAL ;
    PORT
      LAYER M4 ;
        RECT  0 18.384 0.084 18.408 ;
    END
  END wm[54]
  PIN wm[55]
    DIRECTION INPUT ;
    USE SIGNAL ;
    PORT
      LAYER M4 ;
        RECT  0 18.48 0.084 18.504 ;
    END
  END wm[55]
  PIN wm[56]
    DIRECTION INPUT ;
    USE SIGNAL ;
    PORT
      LAYER M4 ;
        RECT  0 18.576 0.084 18.6 ;
    END
  END wm[56]
  PIN wm[57]
    DIRECTION INPUT ;
    USE SIGNAL ;
    PORT
      LAYER M4 ;
        RECT  0 18.672 0.084 18.696 ;
    END
  END wm[57]
  PIN wm[58]
    DIRECTION INPUT ;
    USE SIGNAL ;
    PORT
      LAYER M4 ;
        RECT  0 18.768 0.084 18.792 ;
    END
  END wm[58]
  PIN wm[59]
    DIRECTION INPUT ;
    USE SIGNAL ;
    PORT
      LAYER M4 ;
        RECT  0 18.864 0.084 18.888 ;
    END
  END wm[59]
  PIN wm[5]
    DIRECTION INPUT ;
    USE SIGNAL ;
    PORT
      LAYER M4 ;
        RECT  0 25.968 0.084 25.992 ;
    END
  END wm[5]
  PIN wm[60]
    DIRECTION INPUT ;
    USE SIGNAL ;
    PORT
      LAYER M4 ;
        RECT  0 18.96 0.084 18.984 ;
    END
  END wm[60]
  PIN wm[61]
    DIRECTION INPUT ;
    USE SIGNAL ;
    PORT
      LAYER M4 ;
        RECT  0 19.056 0.084 19.08 ;
    END
  END wm[61]
  PIN wm[62]
    DIRECTION INPUT ;
    USE SIGNAL ;
    PORT
      LAYER M4 ;
        RECT  0 19.152 0.084 19.176 ;
    END
  END wm[62]
  PIN wm[63]
    DIRECTION INPUT ;
    USE SIGNAL ;
    PORT
      LAYER M4 ;
        RECT  0 19.248 0.084 19.272 ;
    END
  END wm[63]
  PIN wm[64]
    DIRECTION INPUT ;
    USE SIGNAL ;
    PORT
      LAYER M4 ;
        RECT  0 19.344 0.084 19.368 ;
    END
  END wm[64]
  PIN wm[65]
    DIRECTION INPUT ;
    USE SIGNAL ;
    PORT
      LAYER M4 ;
        RECT  0 19.44 0.084 19.464 ;
    END
  END wm[65]
  PIN wm[66]
    DIRECTION INPUT ;
    USE SIGNAL ;
    PORT
      LAYER M4 ;
        RECT  0 19.536 0.084 19.56 ;
    END
  END wm[66]
  PIN wm[67]
    DIRECTION INPUT ;
    USE SIGNAL ;
    PORT
      LAYER M4 ;
        RECT  0 19.632 0.084 19.656 ;
    END
  END wm[67]
  PIN wm[68]
    DIRECTION INPUT ;
    USE SIGNAL ;
    PORT
      LAYER M4 ;
        RECT  0 19.728 0.084 19.752 ;
    END
  END wm[68]
  PIN wm[69]
    DIRECTION INPUT ;
    USE SIGNAL ;
    PORT
      LAYER M4 ;
        RECT  0 19.824 0.084 19.848 ;
    END
  END wm[69]
  PIN wm[6]
    DIRECTION INPUT ;
    USE SIGNAL ;
    PORT
      LAYER M4 ;
        RECT  0 26.064 0.084 26.088 ;
    END
  END wm[6]
  PIN wm[70]
    DIRECTION INPUT ;
    USE SIGNAL ;
    PORT
      LAYER M4 ;
        RECT  0 19.92 0.084 19.944 ;
    END
  END wm[70]
  PIN wm[71]
    DIRECTION INPUT ;
    USE SIGNAL ;
    PORT
      LAYER M4 ;
        RECT  0 20.016 0.084 20.04 ;
    END
  END wm[71]
  PIN wm[72]
    DIRECTION INPUT ;
    USE SIGNAL ;
    PORT
      LAYER M4 ;
        RECT  0 20.112 0.084 20.136 ;
    END
  END wm[72]
  PIN wm[73]
    DIRECTION INPUT ;
    USE SIGNAL ;
    PORT
      LAYER M4 ;
        RECT  0 20.208 0.084 20.232 ;
    END
  END wm[73]
  PIN wm[74]
    DIRECTION INPUT ;
    USE SIGNAL ;
    PORT
      LAYER M4 ;
        RECT  0 20.304 0.084 20.328 ;
    END
  END wm[74]
  PIN wm[75]
    DIRECTION INPUT ;
    USE SIGNAL ;
    PORT
      LAYER M4 ;
        RECT  0 20.4 0.084 20.424 ;
    END
  END wm[75]
  PIN wm[76]
    DIRECTION INPUT ;
    USE SIGNAL ;
    PORT
      LAYER M4 ;
        RECT  0 20.496 0.084 20.52 ;
    END
  END wm[76]
  PIN wm[77]
    DIRECTION INPUT ;
    USE SIGNAL ;
    PORT
      LAYER M4 ;
        RECT  0 20.592 0.084 20.616 ;
    END
  END wm[77]
  PIN wm[78]
    DIRECTION INPUT ;
    USE SIGNAL ;
    PORT
      LAYER M4 ;
        RECT  0 20.688 0.084 20.712 ;
    END
  END wm[78]
  PIN wm[79]
    DIRECTION INPUT ;
    USE SIGNAL ;
    PORT
      LAYER M4 ;
        RECT  0 20.784 0.084 20.808 ;
    END
  END wm[79]
  PIN wm[7]
    DIRECTION INPUT ;
    USE SIGNAL ;
    PORT
      LAYER M4 ;
        RECT  0 26.16 0.084 26.184 ;
    END
  END wm[7]
  PIN wm[80]
    DIRECTION INPUT ;
    USE SIGNAL ;
    PORT
      LAYER M4 ;
        RECT  0 20.88 0.084 20.904 ;
    END
  END wm[80]
  PIN wm[81]
    DIRECTION INPUT ;
    USE SIGNAL ;
    PORT
      LAYER M4 ;
        RECT  0 20.976 0.084 21 ;
    END
  END wm[81]
  PIN wm[82]
    DIRECTION INPUT ;
    USE SIGNAL ;
    PORT
      LAYER M4 ;
        RECT  0 21.072 0.084 21.096 ;
    END
  END wm[82]
  PIN wm[83]
    DIRECTION INPUT ;
    USE SIGNAL ;
    PORT
      LAYER M4 ;
        RECT  0 21.168 0.084 21.192 ;
    END
  END wm[83]
  PIN wm[84]
    DIRECTION INPUT ;
    USE SIGNAL ;
    PORT
      LAYER M4 ;
        RECT  0 21.264 0.084 21.288 ;
    END
  END wm[84]
  PIN wm[85]
    DIRECTION INPUT ;
    USE SIGNAL ;
    PORT
      LAYER M4 ;
        RECT  0 21.36 0.084 21.384 ;
    END
  END wm[85]
  PIN wm[86]
    DIRECTION INPUT ;
    USE SIGNAL ;
    PORT
      LAYER M4 ;
        RECT  0 21.456 0.084 21.48 ;
    END
  END wm[86]
  PIN wm[87]
    DIRECTION INPUT ;
    USE SIGNAL ;
    PORT
      LAYER M4 ;
        RECT  0 21.552 0.084 21.576 ;
    END
  END wm[87]
  PIN wm[88]
    DIRECTION INPUT ;
    USE SIGNAL ;
    PORT
      LAYER M4 ;
        RECT  0 21.648 0.084 21.672 ;
    END
  END wm[88]
  PIN wm[89]
    DIRECTION INPUT ;
    USE SIGNAL ;
    PORT
      LAYER M4 ;
        RECT  0 21.744 0.084 21.768 ;
    END
  END wm[89]
  PIN wm[8]
    DIRECTION INPUT ;
    USE SIGNAL ;
    PORT
      LAYER M4 ;
        RECT  0 26.256 0.084 26.28 ;
    END
  END wm[8]
  PIN wm[90]
    DIRECTION INPUT ;
    USE SIGNAL ;
    PORT
      LAYER M4 ;
        RECT  0 21.84 0.084 21.864 ;
    END
  END wm[90]
  PIN wm[91]
    DIRECTION INPUT ;
    USE SIGNAL ;
    PORT
      LAYER M4 ;
        RECT  0 21.936 0.084 21.96 ;
    END
  END wm[91]
  PIN wm[92]
    DIRECTION INPUT ;
    USE SIGNAL ;
    PORT
      LAYER M4 ;
        RECT  0 22.032 0.084 22.056 ;
    END
  END wm[92]
  PIN wm[93]
    DIRECTION INPUT ;
    USE SIGNAL ;
    PORT
      LAYER M4 ;
        RECT  0 22.128 0.084 22.152 ;
    END
  END wm[93]
  PIN wm[94]
    DIRECTION INPUT ;
    USE SIGNAL ;
    PORT
      LAYER M4 ;
        RECT  0 22.224 0.084 22.248 ;
    END
  END wm[94]
  PIN wm[95]
    DIRECTION INPUT ;
    USE SIGNAL ;
    PORT
      LAYER M4 ;
        RECT  0 22.32 0.084 22.344 ;
    END
  END wm[95]
  PIN wm[96]
    DIRECTION INPUT ;
    USE SIGNAL ;
    PORT
      LAYER M4 ;
        RECT  0 22.416 0.084 22.44 ;
    END
  END wm[96]
  PIN wm[97]
    DIRECTION INPUT ;
    USE SIGNAL ;
    PORT
      LAYER M4 ;
        RECT  0 22.512 0.084 22.536 ;
    END
  END wm[97]
  PIN wm[98]
    DIRECTION INPUT ;
    USE SIGNAL ;
    PORT
      LAYER M4 ;
        RECT  0 22.608 0.084 22.632 ;
    END
  END wm[98]
  PIN wm[99]
    DIRECTION INPUT ;
    USE SIGNAL ;
    PORT
      LAYER M4 ;
        RECT  0 22.704 0.084 22.728 ;
    END
  END wm[99]
  PIN wm[9]
    DIRECTION INPUT ;
    USE SIGNAL ;
    PORT
      LAYER M4 ;
        RECT  0 26.352 0.084 26.376 ;
    END
  END wm[9]
  PIN xg[0]
    DIRECTION OUTPUT ;
    USE SIGNAL ;
    PORT
      LAYER M4 ;
        RECT  38.796 13.2 38.88 13.224 ;
    END
  END xg[0]
  PIN xg[1]
    DIRECTION OUTPUT ;
    USE SIGNAL ;
    PORT
      LAYER M4 ;
        RECT  38.796 13.296 38.88 13.32 ;
    END
  END xg[1]
  PIN xg[2]
    DIRECTION OUTPUT ;
    USE SIGNAL ;
    PORT
      LAYER M4 ;
        RECT  38.796 13.392 38.88 13.416 ;
    END
  END xg[2]
  PIN xg[3]
    DIRECTION OUTPUT ;
    USE SIGNAL ;
    PORT
      LAYER M4 ;
        RECT  38.796 13.488 38.88 13.512 ;
    END
  END xg[3]
  PIN xg[4]
    DIRECTION OUTPUT ;
    USE SIGNAL ;
    PORT
      LAYER M4 ;
        RECT  38.796 13.584 38.88 13.608 ;
    END
  END xg[4]
  PIN xg[5]
    DIRECTION OUTPUT ;
    USE SIGNAL ;
    PORT
      LAYER M4 ;
        RECT  38.796 13.68 38.88 13.704 ;
    END
  END xg[5]
  PIN xg[6]
    DIRECTION OUTPUT ;
    USE SIGNAL ;
    PORT
      LAYER M4 ;
        RECT  38.796 13.776 38.88 13.8 ;
    END
  END xg[6]
  PIN xg[7]
    DIRECTION OUTPUT ;
    USE SIGNAL ;
    PORT
      LAYER M4 ;
        RECT  38.796 13.872 38.88 13.896 ;
    END
  END xg[7]
  PIN xv
    DIRECTION INPUT ;
    USE SIGNAL ;
    PORT
      LAYER M4 ;
        RECT  0 51.024 0.084 51.048 ;
    END
  END xv
  PIN VDD
    DIRECTION INOUT ;
    USE POWER ;
    PORT
      LAYER M5 ;
        RECT  34.992 2.151 35.112 66.969 ;
        RECT  29.592 2.151 29.712 66.969 ;
        RECT  24.192 2.151 24.312 66.969 ;
        RECT  18.792 2.151 18.912 66.969 ;
        RECT  13.392 2.151 13.512 66.969 ;
        RECT  7.992 2.151 8.112 66.969 ;
        RECT  2.592 2.151 2.712 66.969 ;
    END
  END VDD
  PIN VSS
    DIRECTION INOUT ;
    USE GROUND ;
    PORT
      LAYER M5 ;
        RECT  34.8 2.137 34.92 66.983 ;
        RECT  29.4 2.137 29.52 66.983 ;
        RECT  24 2.137 24.12 66.983 ;
        RECT  18.6 2.137 18.72 66.983 ;
        RECT  13.2 2.137 13.32 66.983 ;
        RECT  7.8 2.137 7.92 66.983 ;
        RECT  2.4 2.137 2.52 66.983 ;
    END
  END VSS
  # OT_OBS_CLOSED layer=M5 d_um=1.536 added=44
  OBS
    LAYER RVTN ;
     RECT  2.16 2.16 36.72 2.295 ;
     RECT  2.16 2.565 36.72 2.835 ;
     RECT  2.16 3.105 36.72 3.375 ;
     RECT  2.16 3.645 36.72 3.915 ;
     RECT  2.16 4.185 36.72 4.455 ;
     RECT  2.16 4.725 36.72 4.995 ;
     RECT  2.16 5.265 36.72 5.535 ;
     RECT  2.16 5.805 36.72 6.075 ;
     RECT  2.16 6.345 36.72 6.615 ;
     RECT  2.16 6.885 36.72 7.155 ;
     RECT  2.16 7.425 36.72 7.695 ;
     RECT  2.16 7.965 36.72 8.235 ;
     RECT  2.16 8.505 36.72 8.775 ;
     RECT  2.16 9.045 36.72 9.315 ;
     RECT  2.16 9.585 36.72 9.855 ;
     RECT  2.16 10.125 36.72 10.395 ;
     RECT  2.16 10.665 36.72 10.935 ;
     RECT  2.16 11.205 36.72 11.475 ;
     RECT  2.16 11.745 36.72 12.015 ;
     RECT  2.16 12.285 36.72 12.555 ;
     RECT  2.16 12.825 36.72 13.095 ;
     RECT  2.16 13.365 36.72 13.635 ;
     RECT  2.16 13.905 36.72 14.175 ;
     RECT  2.16 14.445 36.72 14.715 ;
     RECT  2.16 14.985 36.72 15.255 ;
     RECT  2.16 15.525 36.72 15.795 ;
     RECT  2.16 16.065 36.72 16.335 ;
     RECT  2.16 16.605 36.72 16.875 ;
     RECT  2.16 17.145 36.72 17.415 ;
     RECT  2.16 17.685 36.72 17.955 ;
     RECT  2.16 18.225 36.72 18.495 ;
     RECT  2.16 18.765 36.72 19.035 ;
     RECT  2.16 19.305 36.72 19.575 ;
     RECT  2.16 19.845 36.72 20.115 ;
     RECT  2.16 20.385 36.72 20.655 ;
     RECT  2.16 20.925 36.72 21.195 ;
     RECT  2.16 21.465 36.72 21.735 ;
     RECT  2.16 22.005 36.72 22.275 ;
     RECT  2.16 22.545 36.72 22.815 ;
     RECT  2.16 23.085 36.72 23.355 ;
     RECT  2.16 23.625 36.72 23.895 ;
     RECT  2.16 24.165 36.72 24.435 ;
     RECT  2.16 24.705 36.72 24.975 ;
     RECT  2.16 25.245 36.72 25.515 ;
     RECT  2.16 25.785 36.72 26.055 ;
     RECT  2.16 26.325 36.72 26.595 ;
     RECT  2.16 26.865 36.72 27.135 ;
     RECT  2.16 27.405 36.72 27.675 ;
     RECT  2.16 27.945 36.72 28.215 ;
     RECT  2.16 28.485 36.72 28.755 ;
     RECT  2.16 29.025 36.72 29.295 ;
     RECT  2.16 29.565 36.72 29.835 ;
     RECT  2.16 30.105 36.72 30.375 ;
     RECT  2.16 30.645 36.72 30.915 ;
     RECT  2.16 31.185 36.72 31.455 ;
     RECT  2.16 31.725 36.72 31.995 ;
     RECT  2.16 32.265 36.72 32.535 ;
     RECT  2.16 32.805 36.72 33.075 ;
     RECT  2.16 33.345 36.72 33.615 ;
     RECT  2.16 33.885 36.72 34.155 ;
     RECT  2.16 34.425 36.72 34.695 ;
     RECT  2.16 34.965 36.72 35.235 ;
     RECT  2.16 35.505 36.72 35.775 ;
     RECT  2.16 36.045 36.72 36.315 ;
     RECT  2.16 36.585 36.72 36.855 ;
     RECT  2.16 37.125 36.72 37.395 ;
     RECT  2.16 37.665 36.72 37.935 ;
     RECT  2.16 38.205 36.72 38.475 ;
     RECT  2.16 38.745 36.72 39.015 ;
     RECT  2.16 39.285 36.72 39.555 ;
     RECT  2.16 39.825 36.72 40.095 ;
     RECT  2.16 40.365 36.72 40.635 ;
     RECT  2.16 40.905 36.72 41.175 ;
     RECT  2.16 41.445 36.72 41.715 ;
     RECT  2.16 41.985 36.72 42.255 ;
     RECT  2.16 42.525 36.72 42.795 ;
     RECT  2.16 43.065 36.72 43.335 ;
     RECT  2.16 43.605 36.72 43.875 ;
     RECT  2.16 44.145 36.72 44.415 ;
     RECT  2.16 44.685 36.72 44.955 ;
     RECT  2.16 45.225 36.72 45.495 ;
     RECT  2.16 45.765 36.72 46.035 ;
     RECT  2.16 46.305 36.72 46.575 ;
     RECT  2.16 46.845 36.72 47.115 ;
     RECT  2.16 47.385 36.72 47.655 ;
     RECT  2.16 47.925 36.72 48.195 ;
     RECT  2.16 48.465 36.72 48.735 ;
     RECT  2.16 49.005 36.72 49.275 ;
     RECT  2.16 49.545 36.72 49.815 ;
     RECT  2.16 50.085 36.72 50.355 ;
     RECT  2.16 50.625 36.72 50.895 ;
     RECT  2.16 51.165 36.72 51.435 ;
     RECT  2.16 51.705 36.72 51.975 ;
     RECT  2.16 52.245 36.72 52.515 ;
     RECT  2.16 52.785 36.72 53.055 ;
     RECT  2.16 53.325 36.72 53.595 ;
     RECT  2.16 53.865 36.72 54.135 ;
     RECT  2.16 54.405 36.72 54.675 ;
     RECT  2.16 54.945 36.72 55.215 ;
     RECT  2.16 55.485 36.72 55.755 ;
     RECT  2.16 56.025 36.72 56.295 ;
     RECT  2.16 56.565 36.72 56.835 ;
     RECT  2.16 57.105 36.72 57.375 ;
     RECT  2.16 57.645 36.72 57.915 ;
     RECT  2.16 58.185 36.72 58.455 ;
     RECT  2.16 58.725 36.72 58.995 ;
     RECT  2.16 59.265 36.72 59.535 ;
     RECT  2.16 59.805 36.72 60.075 ;
     RECT  2.16 60.345 36.72 60.615 ;
     RECT  2.16 60.885 36.72 61.155 ;
     RECT  2.16 61.425 36.72 61.695 ;
     RECT  2.16 61.965 36.72 62.235 ;
     RECT  2.16 62.505 36.72 62.775 ;
     RECT  2.16 63.045 36.72 63.315 ;
     RECT  2.16 63.585 36.72 63.855 ;
     RECT  2.16 64.125 36.72 64.395 ;
     RECT  2.16 64.665 36.72 64.935 ;
     RECT  2.16 65.205 36.72 65.475 ;
     RECT  2.16 65.745 36.72 66.015 ;
     RECT  2.16 66.285 36.72 66.555 ;
     RECT  2.16 66.825 36.72 66.96 ;
    LAYER RVTP ;
     RECT  2.16 2.295 36.72 2.565 ;
     RECT  2.16 2.835 36.72 3.105 ;
     RECT  2.16 3.375 36.72 3.645 ;
     RECT  2.16 3.915 36.72 4.185 ;
     RECT  2.16 4.455 36.72 4.725 ;
     RECT  2.16 4.995 36.72 5.265 ;
     RECT  2.16 5.535 36.72 5.805 ;
     RECT  2.16 6.075 36.72 6.345 ;
     RECT  2.16 6.615 36.72 6.885 ;
     RECT  2.16 7.155 36.72 7.425 ;
     RECT  2.16 7.695 36.72 7.965 ;
     RECT  2.16 8.235 36.72 8.505 ;
     RECT  2.16 8.775 36.72 9.045 ;
     RECT  2.16 9.315 36.72 9.585 ;
     RECT  2.16 9.855 36.72 10.125 ;
     RECT  2.16 10.395 36.72 10.665 ;
     RECT  2.16 10.935 36.72 11.205 ;
     RECT  2.16 11.475 36.72 11.745 ;
     RECT  2.16 12.015 36.72 12.285 ;
     RECT  2.16 12.555 36.72 12.825 ;
     RECT  2.16 13.095 36.72 13.365 ;
     RECT  2.16 13.635 36.72 13.905 ;
     RECT  2.16 14.175 36.72 14.445 ;
     RECT  2.16 14.715 36.72 14.985 ;
     RECT  2.16 15.255 36.72 15.525 ;
     RECT  2.16 15.795 36.72 16.065 ;
     RECT  2.16 16.335 36.72 16.605 ;
     RECT  2.16 16.875 36.72 17.145 ;
     RECT  2.16 17.415 36.72 17.685 ;
     RECT  2.16 17.955 36.72 18.225 ;
     RECT  2.16 18.495 36.72 18.765 ;
     RECT  2.16 19.035 36.72 19.305 ;
     RECT  2.16 19.575 36.72 19.845 ;
     RECT  2.16 20.115 36.72 20.385 ;
     RECT  2.16 20.655 36.72 20.925 ;
     RECT  2.16 21.195 36.72 21.465 ;
     RECT  2.16 21.735 36.72 22.005 ;
     RECT  2.16 22.275 36.72 22.545 ;
     RECT  2.16 22.815 36.72 23.085 ;
     RECT  2.16 23.355 36.72 23.625 ;
     RECT  2.16 23.895 36.72 24.165 ;
     RECT  2.16 24.435 36.72 24.705 ;
     RECT  2.16 24.975 36.72 25.245 ;
     RECT  2.16 25.515 36.72 25.785 ;
     RECT  2.16 26.055 36.72 26.325 ;
     RECT  2.16 26.595 36.72 26.865 ;
     RECT  2.16 27.135 36.72 27.405 ;
     RECT  2.16 27.675 36.72 27.945 ;
     RECT  2.16 28.215 36.72 28.485 ;
     RECT  2.16 28.755 36.72 29.025 ;
     RECT  2.16 29.295 36.72 29.565 ;
     RECT  2.16 29.835 36.72 30.105 ;
     RECT  2.16 30.375 36.72 30.645 ;
     RECT  2.16 30.915 36.72 31.185 ;
     RECT  2.16 31.455 36.72 31.725 ;
     RECT  2.16 31.995 36.72 32.265 ;
     RECT  2.16 32.535 36.72 32.805 ;
     RECT  2.16 33.075 36.72 33.345 ;
     RECT  2.16 33.615 36.72 33.885 ;
     RECT  2.16 34.155 36.72 34.425 ;
     RECT  2.16 34.695 36.72 34.965 ;
     RECT  2.16 35.235 36.72 35.505 ;
     RECT  2.16 35.775 36.72 36.045 ;
     RECT  2.16 36.315 36.72 36.585 ;
     RECT  2.16 36.855 36.72 37.125 ;
     RECT  2.16 37.395 36.72 37.665 ;
     RECT  2.16 37.935 36.72 38.205 ;
     RECT  2.16 38.475 36.72 38.745 ;
     RECT  2.16 39.015 36.72 39.285 ;
     RECT  2.16 39.555 36.72 39.825 ;
     RECT  2.16 40.095 36.72 40.365 ;
     RECT  2.16 40.635 36.72 40.905 ;
     RECT  2.16 41.175 36.72 41.445 ;
     RECT  2.16 41.715 36.72 41.985 ;
     RECT  2.16 42.255 36.72 42.525 ;
     RECT  2.16 42.795 36.72 43.065 ;
     RECT  2.16 43.335 36.72 43.605 ;
     RECT  2.16 43.875 36.72 44.145 ;
     RECT  2.16 44.415 36.72 44.685 ;
     RECT  2.16 44.955 36.72 45.225 ;
     RECT  2.16 45.495 36.72 45.765 ;
     RECT  2.16 46.035 36.72 46.305 ;
     RECT  2.16 46.575 36.72 46.845 ;
     RECT  2.16 47.115 36.72 47.385 ;
     RECT  2.16 47.655 36.72 47.925 ;
     RECT  2.16 48.195 36.72 48.465 ;
     RECT  2.16 48.735 36.72 49.005 ;
     RECT  2.16 49.275 36.72 49.545 ;
     RECT  2.16 49.815 36.72 50.085 ;
     RECT  2.16 50.355 36.72 50.625 ;
     RECT  2.16 50.895 36.72 51.165 ;
     RECT  2.16 51.435 36.72 51.705 ;
     RECT  2.16 51.975 36.72 52.245 ;
     RECT  2.16 52.515 36.72 52.785 ;
     RECT  2.16 53.055 36.72 53.325 ;
     RECT  2.16 53.595 36.72 53.865 ;
     RECT  2.16 54.135 36.72 54.405 ;
     RECT  2.16 54.675 36.72 54.945 ;
     RECT  2.16 55.215 36.72 55.485 ;
     RECT  2.16 55.755 36.72 56.025 ;
     RECT  2.16 56.295 36.72 56.565 ;
     RECT  2.16 56.835 36.72 57.105 ;
     RECT  2.16 57.375 36.72 57.645 ;
     RECT  2.16 57.915 36.72 58.185 ;
     RECT  2.16 58.455 36.72 58.725 ;
     RECT  2.16 58.995 36.72 59.265 ;
     RECT  2.16 59.535 36.72 59.805 ;
     RECT  2.16 60.075 36.72 60.345 ;
     RECT  2.16 60.615 36.72 60.885 ;
     RECT  2.16 61.155 36.72 61.425 ;
     RECT  2.16 61.695 36.72 61.965 ;
     RECT  2.16 62.235 36.72 62.505 ;
     RECT  2.16 62.775 36.72 63.045 ;
     RECT  2.16 63.315 36.72 63.585 ;
     RECT  2.16 63.855 36.72 64.125 ;
     RECT  2.16 64.395 36.72 64.665 ;
     RECT  2.16 64.935 36.72 65.205 ;
     RECT  2.16 65.475 36.72 65.745 ;
     RECT  2.16 66.015 36.72 66.285 ;
     RECT  2.16 66.555 36.72 66.825 ;
    LAYER M1 ;
     RECT  2.16 2.151 36.72 66.969 ;
    LAYER M2 ;
     RECT  0.031 12.906 0.103 12.924 ;
     RECT  0.031 30.654 0.103 30.672 ;
     RECT  0.031 42.84 0.103 42.858 ;
     RECT  0.103 10.44 0.139 10.458 ;
     RECT  0.103 32.238 0.139 32.256 ;
     RECT  0.103 33.012 0.139 33.408 ;
     RECT  0.103 34.74 0.139 34.758 ;
     RECT  0.103 35.712 0.139 35.73 ;
     RECT  0.103 42.462 0.139 42.858 ;
     RECT  0.103 12.33 0.167 13.662 ;
     RECT  0.139 10.44 0.175 10.962 ;
     RECT  0.103 14.724 0.175 14.742 ;
     RECT  0.103 15.84 0.175 15.858 ;
     RECT  0.103 17.118 0.175 18.018 ;
     RECT  0.103 18.774 0.175 19.098 ;
     RECT  0.103 30.42 0.175 31.212 ;
     RECT  0.139 32.04 0.175 32.256 ;
     RECT  0.139 33.012 0.175 33.876 ;
     RECT  0.103 36.63 0.175 36.648 ;
     RECT  0.103 37.872 0.175 37.89 ;
     RECT  0.103 40.104 0.175 40.122 ;
     RECT  0.175 14.724 0.211 15.858 ;
     RECT  0.175 17.118 0.211 19.53 ;
     RECT  0.103 20.394 0.211 20.988 ;
     RECT  0.175 30.42 0.211 33.876 ;
     RECT  0.139 34.74 0.211 35.73 ;
     RECT  0.175 40.104 0.211 40.32 ;
     RECT  0.175 10.44 0.247 11.538 ;
     RECT  0.167 12.33 0.247 12.654 ;
     RECT  0.211 14.724 0.247 16.128 ;
     RECT  0.211 17.118 0.247 20.988 ;
     RECT  0.103 49.86 0.347 49.878 ;
     RECT  0.103 22.212 0.463 22.23 ;
     RECT  0.463 22.212 0.499 22.644 ;
     RECT  0.499 22.212 0.535 22.842 ;
     RECT  0.103 25.56 0.535 25.578 ;
     RECT  0.103 26.64 0.535 26.658 ;
     RECT  0.175 36.63 0.535 37.89 ;
     RECT  0.211 40.104 0.535 40.968 ;
     RECT  0.535 39.726 1.147 40.968 ;
     RECT  1.327 51.714 1.435 51.732 ;
     RECT  0.535 47.124 1.723 47.142 ;
     RECT  1.435 51.714 1.723 52.2 ;
     RECT  0.139 42.462 2.011 43.866 ;
     RECT  1.399 45 2.011 45.018 ;
     RECT  1.723 51.516 2.011 52.2 ;
     RECT  0.031 9.36 2.16 9.378 ;
     RECT  0.247 10.44 2.16 12.654 ;
     RECT  0.167 13.644 2.16 13.662 ;
     RECT  0.247 14.724 2.16 20.988 ;
     RECT  0.535 22.086 2.16 22.914 ;
     RECT  0.535 25.488 2.16 25.578 ;
     RECT  0.535 26.64 2.16 27.234 ;
     RECT  0.103 28.458 2.16 28.476 ;
     RECT  0.211 30.42 2.16 35.73 ;
     RECT  0.535 36.63 2.16 38.502 ;
     RECT  1.147 39.636 2.16 40.968 ;
     RECT  2.011 42.462 2.16 45.018 ;
     RECT  1.723 47.124 2.16 47.412 ;
     RECT  1.147 50.4 2.16 50.418 ;
     RECT  2.011 51.516 2.16 52.47 ;
     RECT  2.047 53.262 2.16 53.28 ;
     RECT  2.16 2.151 36.72 66.969 ;
     RECT  36.72 9.324 36.743 25.074 ;
     RECT  36.72 52.866 36.743 53.514 ;
     RECT  36.72 41.076 36.779 41.364 ;
     RECT  36.743 9.324 36.815 23.652 ;
     RECT  36.72 54.306 36.851 57.564 ;
     RECT  36.743 52.866 36.887 53.424 ;
     RECT  36.887 52.866 36.923 52.884 ;
     RECT  36.72 2.808 36.959 2.826 ;
     RECT  36.851 54.306 36.959 57.474 ;
     RECT  36.815 9.324 37.031 13.662 ;
     RECT  36.815 14.526 37.031 23.652 ;
     RECT  36.959 55.566 37.067 57.474 ;
     RECT  37.031 14.526 37.103 16.794 ;
     RECT  37.031 9.324 37.247 13.392 ;
     RECT  36.72 25.866 37.319 26.694 ;
     RECT  37.067 55.566 37.319 56.214 ;
     RECT  36.72 31.734 37.355 31.752 ;
     RECT  36.72 48.906 37.355 49.644 ;
     RECT  36.779 41.076 37.391 41.094 ;
     RECT  37.067 57.006 37.391 57.474 ;
     RECT  36.72 59.04 37.391 66.114 ;
     RECT  36.72 4.086 37.427 8.532 ;
     RECT  36.72 45.666 37.427 45.954 ;
     RECT  37.391 59.04 37.471 65.664 ;
     RECT  37.103 14.526 37.499 15.246 ;
     RECT  36.72 34.74 37.499 39.744 ;
     RECT  37.427 6.201 37.535 8.532 ;
     RECT  37.031 17.586 37.535 23.652 ;
     RECT  37.319 25.956 37.535 26.694 ;
     RECT  37.499 39.456 37.535 39.744 ;
     RECT  37.499 15.066 37.571 15.246 ;
     RECT  37.535 39.726 37.571 39.744 ;
     RECT  36.743 24.48 37.607 25.074 ;
     RECT  36.72 28.386 37.607 29.934 ;
     RECT  36.72 51.336 37.607 51.462 ;
     RECT  37.319 55.566 37.607 55.584 ;
     RECT  37.535 17.586 37.643 22.644 ;
     RECT  37.499 34.74 37.643 38.574 ;
     RECT  37.355 49.626 37.643 49.644 ;
     RECT  37.247 9.324 37.679 12.654 ;
     RECT  37.643 20.088 37.787 22.644 ;
     RECT  37.391 57.006 37.859 57.402 ;
     RECT  37.607 28.386 37.895 28.854 ;
     RECT  37.607 51.336 37.895 51.354 ;
     RECT  37.535 6.246 37.931 8.532 ;
     RECT  37.859 57.006 38.003 57.168 ;
     RECT  37.931 7.164 38.039 8.532 ;
     RECT  37.471 58.626 38.075 65.664 ;
     RECT  37.679 9.324 38.147 11.304 ;
     RECT  38.039 7.164 38.183 7.884 ;
     RECT  38.147 10.332 38.183 11.304 ;
     RECT  37.571 15.156 38.183 15.246 ;
     RECT  37.895 28.386 38.183 28.404 ;
     RECT  37.643 34.74 38.183 38.124 ;
     RECT  37.427 45.774 38.183 45.954 ;
     RECT  36.72 47.286 38.183 47.88 ;
     RECT  37.679 12.096 38.219 12.654 ;
     RECT  37.535 23.634 38.219 23.652 ;
     RECT  38.183 34.74 38.219 35.604 ;
     RECT  36.959 54.306 38.227 54.324 ;
     RECT  37.103 16.146 38.255 16.794 ;
     RECT  38.183 10.332 38.291 11.232 ;
     RECT  37.643 17.586 38.327 19.224 ;
     RECT  38.075 58.626 38.327 65.394 ;
     RECT  38.255 16.146 38.363 16.632 ;
     RECT  37.543 14.256 38.371 14.274 ;
     RECT  38.183 15.156 38.371 15.174 ;
     RECT  38.003 57.15 38.399 57.168 ;
     RECT  37.787 22.626 38.407 22.644 ;
     RECT  36.72 42.426 38.407 42.444 ;
     RECT  36.72 43.416 38.407 44.676 ;
     RECT  38.371 14.256 38.435 15.174 ;
     RECT  38.327 18.036 38.443 19.224 ;
     RECT  37.787 20.088 38.443 21.654 ;
     RECT  38.407 22.626 38.443 22.77 ;
     RECT  37.535 26.676 38.443 26.694 ;
     RECT  38.407 42.426 38.443 44.676 ;
     RECT  38.327 58.626 38.443 62.964 ;
     RECT  37.607 29.61 38.471 29.934 ;
     RECT  38.443 30.726 38.479 30.744 ;
     RECT  38.219 34.74 38.479 34.794 ;
     RECT  38.227 54.306 38.479 54.738 ;
     RECT  38.147 9.324 38.507 9.342 ;
     RECT  38.443 58.581 38.507 62.964 ;
     RECT  38.443 22.626 38.515 22.842 ;
     RECT  38.443 42.426 38.515 45.018 ;
     RECT  38.183 45.774 38.515 45.864 ;
     RECT  38.479 52.992 38.515 53.01 ;
     RECT  38.291 10.332 38.543 10.854 ;
     RECT  38.435 14.256 38.543 14.904 ;
     RECT  38.443 18.036 38.543 21.654 ;
     RECT  37.931 6.246 38.579 6.264 ;
     RECT  38.443 26.676 38.579 26.856 ;
     RECT  38.479 54.306 38.579 55.278 ;
     RECT  38.327 63.864 38.579 65.394 ;
     RECT  38.479 41.526 38.587 41.544 ;
     RECT  38.515 42.426 38.587 45.864 ;
     RECT  38.183 7.596 38.615 7.884 ;
     RECT  38.543 18.036 38.615 18.954 ;
     RECT  38.543 19.926 38.615 21.654 ;
     RECT  38.479 34.2 38.615 34.794 ;
     RECT  38.587 41.526 38.615 45.864 ;
     RECT  38.515 52.992 38.615 53.244 ;
     RECT  38.507 60.741 38.615 62.424 ;
     RECT  38.183 47.358 38.623 47.88 ;
     RECT  38.579 54.531 38.623 55.278 ;
     RECT  37.427 4.086 38.651 5.292 ;
     RECT  38.363 16.272 38.651 16.632 ;
     RECT  38.479 29.268 38.651 29.358 ;
     RECT  38.551 31.77 38.651 31.788 ;
     RECT  38.615 41.526 38.651 45.099 ;
     RECT  38.407 50.211 38.651 50.958 ;
     RECT  38.615 53.064 38.651 53.244 ;
     RECT  38.479 30.114 38.659 30.744 ;
     RECT  38.651 50.211 38.659 50.886 ;
     RECT  38.623 47.358 38.687 48.42 ;
     RECT  38.623 54.531 38.687 55.359 ;
     RECT  38.615 60.741 38.687 61.524 ;
     RECT  38.615 20.862 38.695 21.654 ;
     RECT  38.515 22.626 38.695 22.914 ;
     RECT  37.607 25.056 38.695 25.074 ;
     RECT  38.687 47.736 38.695 48.42 ;
     RECT  38.659 50.13 38.695 50.886 ;
     RECT  38.687 54.801 38.695 55.359 ;
     RECT  38.615 18.036 38.723 18.054 ;
     RECT  38.615 19.926 38.723 19.944 ;
     RECT  38.651 29.268 38.723 29.286 ;
     RECT  38.183 37.404 38.723 38.124 ;
     RECT  38.651 41.526 38.723 42.516 ;
     RECT  38.651 43.416 38.723 45.099 ;
     RECT  38.695 47.736 38.723 48.654 ;
     RECT  38.507 58.581 38.723 59.526 ;
     RECT  38.579 63.864 38.723 63.882 ;
     RECT  38.219 12.096 38.759 12.114 ;
     RECT  38.651 16.272 38.759 16.56 ;
     RECT  38.615 18.81 38.759 18.954 ;
     RECT  38.695 20.862 38.759 22.914 ;
     RECT  38.723 37.836 38.759 38.124 ;
     RECT  38.723 41.796 38.759 42.516 ;
     RECT  38.723 43.65 38.759 45.099 ;
     RECT  38.615 45.846 38.759 45.864 ;
     RECT  38.651 53.064 38.759 53.154 ;
     RECT  38.695 54.801 38.759 55.476 ;
     RECT  38.687 61.362 38.759 61.38 ;
     RECT  38.651 4.086 38.795 4.68 ;
     RECT  38.543 10.836 38.795 10.854 ;
     RECT  38.759 16.461 38.795 16.479 ;
     RECT  38.759 21.546 38.795 22.914 ;
     RECT  38.695 24.372 38.795 25.704 ;
     RECT  38.659 30.114 38.795 30.834 ;
     RECT  38.695 31.806 38.795 31.824 ;
     RECT  38.219 35.586 38.795 35.604 ;
     RECT  38.183 36.396 38.795 36.414 ;
     RECT  38.759 37.836 38.795 37.854 ;
     RECT  38.759 41.796 38.795 42.246 ;
     RECT  38.759 43.731 38.795 44.604 ;
     RECT  38.723 47.934 38.795 48.654 ;
     RECT  38.695 49.518 38.795 50.886 ;
     RECT  38.759 55.341 38.795 55.476 ;
     RECT  38.723 59.346 38.795 59.454 ;
     RECT  38.579 65.106 38.795 65.394 ;
     RECT  38.615 7.866 38.831 7.884 ;
     RECT  38.659 13.176 38.831 13.392 ;
     RECT  38.543 14.256 38.831 14.274 ;
     RECT  38.795 22.824 38.831 22.914 ;
     RECT  38.795 30.582 38.831 30.834 ;
     RECT  38.615 34.506 38.831 34.794 ;
     RECT  38.795 42.156 38.831 42.174 ;
     RECT  38.795 50.751 38.831 50.886 ;
     RECT  38.723 58.581 38.831 58.599 ;
     RECT  38.615 62.406 38.831 62.424 ;
     RECT  38.795 4.086 38.867 4.104 ;
     RECT  38.831 13.176 38.867 13.194 ;
     RECT  38.759 18.846 38.867 18.954 ;
     RECT  38.579 26.676 38.867 26.784 ;
     RECT  38.831 34.506 38.867 34.524 ;
     RECT  38.767 40.95 38.867 40.968 ;
     RECT  38.795 65.106 38.867 65.124 ;
    LAYER M3 ;
     RECT  25.344 1.723 25.362 2.255 ;
     RECT  2.415 2.143 2.505 2.413 ;
     RECT  7.815 2.143 7.905 2.413 ;
     RECT  13.215 2.143 13.305 2.413 ;
     RECT  18.615 2.143 18.705 2.413 ;
     RECT  24.015 2.143 24.105 2.413 ;
     RECT  29.415 2.143 29.505 2.413 ;
     RECT  34.815 2.143 34.905 2.413 ;
     RECT  26.208 2.263 26.226 2.525 ;
     RECT  34.815 2.413 35.097 2.587 ;
     RECT  32.148 2.605 32.166 2.641 ;
     RECT  34.815 2.587 35.802 2.725 ;
     RECT  34.815 2.725 35.91 2.767 ;
     RECT  34.812 2.767 35.91 2.803 ;
     RECT  32.148 2.641 32.31 2.839 ;
     RECT  32.148 2.839 32.49 2.875 ;
     RECT  31.896 2.875 32.706 2.911 ;
     RECT  31.896 2.911 33.174 3.073 ;
     RECT  34.812 2.803 36.09 3.145 ;
     RECT  34.812 3.145 36.126 3.163 ;
     RECT  34.704 3.163 36.126 3.181 ;
     RECT  36.936 2.803 36.954 3.181 ;
     RECT  34.704 3.181 36.954 3.307 ;
     RECT  34.632 3.307 36.954 3.344 ;
     RECT  30.78 2.731 30.798 3.371 ;
     RECT  31.86 3.073 33.174 3.379 ;
     RECT  34.815 3.344 36.954 3.389 ;
     RECT  26.424 2.641 26.442 3.875 ;
     RECT  29.415 2.413 29.697 3.991 ;
     RECT  27.432 3.811 27.45 4.027 ;
     RECT  31.86 3.379 33.21 4.027 ;
     RECT  34.815 3.389 35.097 4.123 ;
     RECT  35.892 3.389 36.954 4.123 ;
     RECT  26.784 4.027 27.45 4.157 ;
     RECT  29.415 3.991 29.862 4.171 ;
     RECT  34.815 4.123 36.954 4.171 ;
     RECT  29.124 4.171 29.934 4.217 ;
     RECT  31.86 4.027 33.894 4.225 ;
     RECT  34.668 4.171 36.954 4.225 ;
     RECT  30.888 3.403 31.122 4.261 ;
     RECT  31.86 4.225 36.954 4.261 ;
     RECT  30.888 4.261 36.954 4.411 ;
     RECT  29.415 4.217 29.79 4.493 ;
     RECT  38.844 4.081 38.862 4.531 ;
     RECT  24.015 2.413 24.297 4.765 ;
     RECT  25.056 3.343 25.074 4.765 ;
     RECT  26.928 4.157 27.45 4.801 ;
     RECT  30.78 4.411 36.954 4.801 ;
     RECT  30.78 4.801 37.566 4.919 ;
     RECT  26.928 4.801 27.486 4.939 ;
     RECT  26.784 4.939 27.486 5.069 ;
     RECT  34.02 4.919 37.566 5.161 ;
     RECT  38.7 4.531 38.862 5.161 ;
     RECT  30.78 4.919 33.21 5.233 ;
     RECT  29.415 4.493 29.754 5.341 ;
     RECT  30.744 5.233 33.21 5.341 ;
     RECT  29.415 5.341 33.21 5.809 ;
     RECT  34.02 5.161 38.862 5.809 ;
     RECT  29.415 5.809 38.862 6.421 ;
     RECT  28.26 6.385 28.278 6.511 ;
     RECT  29.052 6.421 38.862 6.511 ;
     RECT  26.928 5.069 27.486 7.051 ;
     RECT  28.26 6.511 38.862 7.051 ;
     RECT  26.928 7.051 38.862 8.539 ;
     RECT  2.415 2.413 2.697 9.391 ;
     RECT  26.82 8.539 38.862 9.499 ;
     RECT  2.415 9.391 2.754 9.589 ;
     RECT  26.784 9.499 38.862 9.629 ;
     RECT  2.415 9.589 3.294 9.661 ;
     RECT  2.415 9.661 4.158 9.895 ;
     RECT  2.34 9.895 4.158 10.165 ;
     RECT  6.552 9.931 6.57 10.201 ;
     RECT  6.264 10.201 6.57 10.327 ;
     RECT  5.688 10.327 6.57 10.399 ;
     RECT  0.036 9.355 0.054 10.435 ;
     RECT  5.436 10.399 6.57 10.471 ;
     RECT  7.815 2.413 8.097 10.471 ;
     RECT  2.304 10.165 4.302 10.705 ;
     RECT  2.304 10.705 4.482 10.741 ;
     RECT  5.436 10.471 8.097 10.741 ;
     RECT  0.036 10.435 0.126 10.939 ;
     RECT  24.015 4.765 25.074 10.939 ;
     RECT  26.892 9.629 38.862 11.011 ;
     RECT  0.036 10.939 0.162 11.101 ;
     RECT  16.848 11.101 16.866 11.371 ;
     RECT  15.66 11.137 15.678 11.407 ;
     RECT  2.304 10.741 8.097 11.443 ;
     RECT  8.964 11.479 8.982 11.677 ;
     RECT  26.856 11.011 38.862 11.677 ;
     RECT  8.928 11.677 8.982 11.821 ;
     RECT  9.936 11.515 9.954 11.821 ;
     RECT  24.015 10.939 25.614 11.911 ;
     RECT  26.82 11.677 38.862 11.911 ;
     RECT  0.036 11.101 0.558 11.947 ;
     RECT  15.66 11.407 15.714 11.947 ;
     RECT  16.848 11.371 17.37 11.947 ;
     RECT  2.304 11.443 8.19 12.217 ;
     RECT  8.928 11.821 9.954 12.217 ;
     RECT  15.66 11.947 17.37 12.253 ;
     RECT  13.215 2.413 13.497 12.487 ;
     RECT  24.015 11.911 38.862 12.523 ;
     RECT  10.8 12.631 10.818 12.757 ;
     RECT  13.215 12.487 14.202 12.757 ;
     RECT  14.94 12.253 17.37 12.757 ;
     RECT  2.304 12.217 9.954 12.829 ;
     RECT  10.728 12.757 10.818 12.857 ;
     RECT  2.268 12.829 9.954 12.901 ;
     RECT  0.036 11.947 1.17 12.929 ;
     RECT  2.268 12.901 10.026 13.133 ;
     RECT  23.508 12.523 38.862 13.199 ;
     RECT  0.108 12.929 1.17 13.229 ;
     RECT  23.508 13.199 38.826 13.261 ;
     RECT  18.615 2.413 18.897 13.297 ;
     RECT  23.112 13.261 38.826 13.397 ;
     RECT  13.215 12.757 17.37 13.483 ;
     RECT  0.108 13.229 0.162 13.613 ;
     RECT  11.412 13.639 11.43 13.837 ;
     RECT  11.412 13.837 11.502 13.865 ;
     RECT  0.108 13.613 0.126 13.901 ;
     RECT  11.484 13.865 11.502 13.937 ;
     RECT  2.304 13.133 10.026 13.945 ;
     RECT  2.232 13.945 10.026 14.071 ;
     RECT  12.564 13.483 17.37 14.071 ;
     RECT  12.132 14.071 17.37 14.141 ;
     RECT  12.564 14.141 17.37 14.237 ;
     RECT  23.112 13.397 38.754 14.251 ;
     RECT  23.112 14.251 38.826 14.299 ;
     RECT  13.104 14.237 17.37 14.405 ;
     RECT  1.152 13.229 1.17 14.573 ;
     RECT  13.14 14.405 17.37 14.675 ;
     RECT  2.232 14.071 10.17 14.683 ;
     RECT  23.112 14.299 38.862 14.683 ;
     RECT  2.232 14.683 10.854 14.783 ;
     RECT  0.108 14.719 0.126 14.957 ;
     RECT  2.232 14.783 10.17 15.089 ;
     RECT  0.18 15.223 0.198 15.331 ;
     RECT  18.396 13.297 18.897 15.331 ;
     RECT  13.215 14.675 17.37 15.565 ;
     RECT  18.108 15.331 18.897 15.565 ;
     RECT  2.232 15.089 10.098 15.629 ;
     RECT  19.8 13.567 19.818 15.691 ;
     RECT  13.215 15.565 18.897 15.763 ;
     RECT  19.8 15.691 19.962 15.763 ;
     RECT  0.18 15.331 0.558 15.835 ;
     RECT  11.988 15.223 12.006 16.033 ;
     RECT  11.376 16.033 12.006 16.061 ;
     RECT  11.376 16.061 11.394 16.105 ;
     RECT  13.215 15.763 19.962 16.105 ;
     RECT  11.304 16.105 11.394 16.141 ;
     RECT  13.215 16.105 20.142 16.267 ;
     RECT  23.076 14.683 38.862 16.303 ;
     RECT  22.86 16.303 38.862 16.315 ;
     RECT  2.268 15.629 10.098 16.331 ;
     RECT  10.908 16.141 11.394 16.331 ;
     RECT  0.108 15.835 0.558 16.397 ;
     RECT  13.215 16.267 20.25 16.501 ;
     RECT  21.096 16.069 21.114 16.501 ;
     RECT  6.48 16.331 10.098 16.529 ;
     RECT  10.908 16.331 10.962 16.537 ;
     RECT  6.588 16.529 10.098 16.573 ;
     RECT  10.872 16.537 10.962 16.573 ;
     RECT  22.5 16.315 38.862 16.573 ;
     RECT  13.215 16.501 21.114 16.681 ;
     RECT  21.924 16.573 38.862 16.681 ;
     RECT  2.268 16.331 5.742 16.781 ;
     RECT  6.588 16.573 10.962 16.799 ;
     RECT  6.588 16.799 10.926 16.943 ;
     RECT  13.215 16.681 38.862 17.105 ;
     RECT  1.152 16.891 1.17 17.117 ;
     RECT  2.304 16.781 5.742 17.383 ;
     RECT  6.588 16.943 10.854 17.383 ;
     RECT  0.108 16.397 0.306 17.803 ;
     RECT  0.108 17.803 0.342 17.923 ;
     RECT  2.304 17.383 10.854 18.193 ;
     RECT  2.232 18.193 10.854 18.293 ;
     RECT  13.215 17.105 17.154 18.463 ;
     RECT  0.108 17.923 0.558 18.509 ;
     RECT  0.108 18.509 0.522 18.605 ;
     RECT  12.888 18.463 17.154 18.931 ;
     RECT  17.928 17.105 38.862 18.931 ;
     RECT  2.304 18.293 10.854 19.229 ;
     RECT  11.592 19.201 11.61 19.243 ;
     RECT  12.888 18.931 38.862 19.277 ;
     RECT  26.64 19.277 38.862 19.325 ;
     RECT  26.676 19.325 38.862 19.337 ;
     RECT  0.108 18.605 0.486 19.345 ;
     RECT  12.888 19.277 25.722 19.345 ;
     RECT  11.484 19.243 11.61 19.471 ;
     RECT  12.816 19.345 25.722 19.769 ;
     RECT  12.816 19.769 25.686 19.805 ;
     RECT  11.484 19.471 11.682 19.849 ;
     RECT  2.304 19.229 10.674 19.885 ;
     RECT  2.268 19.885 10.674 19.949 ;
     RECT  17.928 19.805 25.614 19.949 ;
     RECT  11.484 19.849 12.006 20.011 ;
     RECT  12.816 19.805 17.154 20.011 ;
     RECT  0.108 19.345 0.558 20.045 ;
     RECT  2.304 19.949 10.674 20.083 ;
     RECT  11.484 20.011 17.154 20.083 ;
     RECT  26.748 19.337 38.862 20.119 ;
     RECT  0.108 20.045 0.486 20.141 ;
     RECT  17.928 19.949 18.897 20.345 ;
     RECT  19.656 19.949 25.614 20.381 ;
     RECT  2.304 20.083 17.154 20.849 ;
     RECT  18.216 20.345 18.897 20.885 ;
     RECT  19.656 20.381 20.538 20.885 ;
     RECT  15.66 20.849 17.154 21.155 ;
     RECT  19.656 20.885 20.502 21.461 ;
     RECT  21.348 20.381 25.614 21.469 ;
     RECT  26.64 20.119 38.862 21.469 ;
     RECT  17.712 21.361 17.73 21.497 ;
     RECT  19.656 21.461 20.214 21.965 ;
     RECT  21.348 21.469 38.862 21.973 ;
     RECT  20.196 21.965 20.214 22.037 ;
     RECT  21.276 21.973 38.862 22.073 ;
     RECT  0.108 20.141 0.342 22.081 ;
     RECT  2.304 20.849 14.886 22.081 ;
     RECT  15.66 21.155 16.794 22.081 ;
     RECT  2.304 22.081 16.794 22.123 ;
     RECT  2.268 22.123 16.794 22.477 ;
     RECT  0.108 22.081 0.558 22.541 ;
     RECT  2.232 22.477 16.794 22.637 ;
     RECT  17.676 22.315 17.694 22.775 ;
     RECT  2.268 22.637 16.794 23.387 ;
     RECT  20.196 23.557 20.214 23.659 ;
     RECT  0.468 22.541 0.558 23.693 ;
     RECT  0.54 23.693 0.558 23.755 ;
     RECT  20.196 23.659 20.25 23.827 ;
     RECT  0.54 23.755 0.666 23.885 ;
     RECT  18.468 20.885 18.897 23.935 ;
     RECT  19.8 23.827 20.25 23.935 ;
     RECT  18.468 23.935 20.25 24.133 ;
     RECT  21.348 22.073 38.862 24.133 ;
     RECT  2.304 23.387 16.794 24.205 ;
     RECT  2.304 24.205 16.902 24.331 ;
     RECT  2.268 24.331 16.902 24.467 ;
     RECT  18.468 24.133 38.862 24.503 ;
     RECT  2.304 24.467 16.902 24.907 ;
     RECT  19.8 24.503 38.862 25.475 ;
     RECT  1.152 24.811 1.17 25.483 ;
     RECT  18.468 24.503 18.897 25.519 ;
     RECT  0.54 25.483 1.17 25.555 ;
     RECT  0.108 25.555 1.17 25.709 ;
     RECT  18.252 25.519 18.897 25.889 ;
     RECT  0.324 25.709 1.17 26.189 ;
     RECT  2.304 24.907 17.37 26.563 ;
     RECT  1.152 26.189 1.17 26.825 ;
     RECT  0.108 26.635 0.126 26.861 ;
     RECT  2.304 26.563 17.694 26.933 ;
     RECT  0.216 26.923 0.234 27.019 ;
     RECT  0.216 27.019 0.378 27.197 ;
     RECT  2.304 26.933 17.37 27.211 ;
     RECT  2.268 27.211 17.37 27.365 ;
     RECT  0.54 27.211 0.558 27.533 ;
     RECT  19.872 25.475 38.862 27.985 ;
     RECT  0.108 28.453 0.126 28.589 ;
     RECT  19.836 27.985 38.862 28.651 ;
     RECT  18.468 25.889 18.897 28.687 ;
     RECT  19.764 28.651 38.862 28.787 ;
     RECT  2.304 27.365 17.37 28.939 ;
     RECT  18.324 28.687 18.897 29.101 ;
     RECT  2.268 28.939 17.37 29.131 ;
     RECT  18.108 29.101 18.897 29.497 ;
     RECT  2.232 29.131 17.37 29.525 ;
     RECT  2.268 29.525 17.37 29.533 ;
     RECT  18.108 29.497 18.918 29.533 ;
     RECT  2.268 29.533 18.918 29.597 ;
     RECT  2.268 29.597 18.897 29.867 ;
     RECT  2.304 29.867 18.897 30.065 ;
     RECT  2.415 30.065 18.897 30.371 ;
     RECT  0.108 29.899 0.126 30.649 ;
     RECT  0.036 30.649 0.126 30.685 ;
     RECT  0.036 30.685 0.198 30.763 ;
     RECT  0.036 30.763 0.234 30.955 ;
     RECT  2.415 30.371 3.978 30.955 ;
     RECT  0.036 30.955 0.306 31.081 ;
     RECT  2.304 30.955 3.978 31.189 ;
     RECT  2.232 31.189 3.978 31.225 ;
     RECT  2.232 31.225 4.194 31.229 ;
     RECT  0.036 31.081 0.522 31.261 ;
     RECT  2.304 31.229 4.194 31.351 ;
     RECT  4.968 30.371 18.897 31.351 ;
     RECT  0.036 31.261 0.558 31.373 ;
     RECT  2.304 31.351 18.897 31.423 ;
     RECT  0.036 31.373 0.522 31.469 ;
     RECT  2.304 31.423 18.954 31.525 ;
     RECT  2.304 31.525 19.062 31.531 ;
     RECT  2.304 31.531 19.134 31.649 ;
     RECT  0.036 31.469 0.27 32.429 ;
     RECT  2.304 31.649 18.897 32.845 ;
     RECT  2.232 32.845 18.954 33.005 ;
     RECT  2.304 33.005 18.954 33.007 ;
     RECT  19.872 28.787 38.862 33.007 ;
     RECT  0.036 32.429 0.198 33.451 ;
     RECT  0.036 33.451 0.342 33.583 ;
     RECT  2.304 33.007 38.862 33.881 ;
     RECT  19.8 33.881 38.862 34.529 ;
     RECT  0.036 33.583 0.558 34.541 ;
     RECT  2.304 33.881 19.026 34.763 ;
     RECT  19.8 34.529 38.826 34.799 ;
     RECT  2.304 34.763 18.954 35.041 ;
     RECT  19.8 34.799 38.754 35.117 ;
     RECT  0.036 34.541 0.234 35.275 ;
     RECT  37.332 35.117 38.754 35.405 ;
     RECT  0.036 35.275 0.558 35.501 ;
     RECT  19.8 35.117 36.594 35.501 ;
     RECT  37.908 35.405 38.754 35.581 ;
     RECT  37.908 35.581 38.79 36.139 ;
     RECT  0.036 35.501 0.162 36.173 ;
     RECT  19.8 35.501 36.486 36.283 ;
     RECT  37.476 36.139 38.79 36.283 ;
     RECT  2.268 35.041 18.954 36.523 ;
     RECT  2.268 36.523 19.026 36.617 ;
     RECT  19.8 36.283 38.79 36.887 ;
     RECT  0.036 36.173 0.126 37.057 ;
     RECT  0.036 37.057 0.234 37.165 ;
     RECT  0.036 37.165 0.486 37.399 ;
     RECT  2.268 36.617 18.954 37.399 ;
     RECT  19.8 36.887 36.522 37.399 ;
     RECT  2.268 37.399 36.522 37.471 ;
     RECT  0.036 37.399 0.522 37.597 ;
     RECT  1.98 37.471 36.522 37.675 ;
     RECT  37.476 36.887 38.79 37.675 ;
     RECT  1.98 37.675 38.79 37.859 ;
     RECT  1.98 37.859 38.754 37.901 ;
     RECT  38.736 37.901 38.754 38.129 ;
     RECT  1.98 37.901 37.638 38.579 ;
     RECT  0.036 37.597 0.558 38.957 ;
     RECT  38.736 39.403 38.754 39.499 ;
     RECT  0.036 38.957 0.342 39.721 ;
     RECT  1.152 39.631 1.17 39.721 ;
     RECT  0.036 39.721 1.17 39.749 ;
     RECT  1.98 38.579 37.566 39.883 ;
     RECT  0.036 39.749 0.558 40.109 ;
     RECT  38.664 39.499 38.754 40.363 ;
     RECT  0.036 40.109 0.342 40.589 ;
     RECT  38.628 40.363 38.754 40.936 ;
     RECT  38.628 40.936 38.79 40.945 ;
     RECT  0.036 40.589 0.234 41.165 ;
     RECT  1.98 39.883 37.89 41.323 ;
     RECT  38.628 40.945 38.862 41.323 ;
     RECT  0.036 41.165 0.162 42.125 ;
     RECT  1.98 41.323 38.862 42.475 ;
     RECT  0.036 42.125 0.126 42.863 ;
     RECT  0.108 42.863 0.126 43.141 ;
     RECT  0.108 43.141 0.558 43.469 ;
     RECT  1.404 42.475 38.862 43.673 ;
     RECT  0.108 43.469 0.162 43.949 ;
     RECT  0.108 43.949 0.126 44.731 ;
     RECT  0.108 44.731 0.162 44.779 ;
     RECT  0.108 44.779 0.342 44.909 ;
     RECT  1.404 43.673 18.897 44.995 ;
     RECT  1.404 44.995 18.954 45.023 ;
     RECT  1.98 45.023 18.954 45.463 ;
     RECT  19.872 43.673 38.862 45.463 ;
     RECT  1.98 45.463 38.862 45.491 ;
     RECT  1.152 45.931 1.17 46.109 ;
     RECT  1.98 45.491 9.738 46.157 ;
     RECT  0.108 44.909 0.126 46.253 ;
     RECT  2.196 46.157 9.738 46.301 ;
     RECT  2.196 46.301 9.702 46.337 ;
     RECT  1.26 46.987 1.278 47.083 ;
     RECT  2.232 46.337 9.702 47.083 ;
     RECT  10.512 45.491 38.862 47.111 ;
     RECT  1.152 47.083 1.278 47.119 ;
     RECT  10.62 47.111 20.502 47.183 ;
     RECT  10.656 47.183 20.502 47.219 ;
     RECT  0.54 47.119 1.278 47.261 ;
     RECT  2.232 47.083 9.738 47.275 ;
     RECT  1.332 47.275 9.738 47.417 ;
     RECT  2.268 47.417 9.738 47.489 ;
     RECT  0.54 47.261 0.558 47.597 ;
     RECT  10.656 47.219 18.897 47.723 ;
     RECT  10.692 47.723 18.897 47.885 ;
     RECT  19.872 47.219 20.502 47.929 ;
     RECT  21.348 47.111 38.862 47.929 ;
     RECT  10.764 47.885 18.897 48.235 ;
     RECT  1.332 47.417 1.35 48.331 ;
     RECT  10.764 48.235 19.026 48.389 ;
     RECT  10.764 48.389 18.954 48.425 ;
     RECT  0.324 48.619 0.342 48.715 ;
     RECT  0.216 48.715 0.342 48.749 ;
     RECT  0.216 48.749 0.234 48.893 ;
     RECT  1.152 48.331 1.35 48.907 ;
     RECT  2.268 47.489 9.702 49.045 ;
     RECT  10.764 48.425 18.897 49.243 ;
     RECT  2.268 49.045 9.738 49.315 ;
     RECT  10.692 49.243 18.897 49.315 ;
     RECT  1.152 48.907 1.458 49.483 ;
     RECT  2.268 49.315 18.897 49.483 ;
     RECT  19.872 47.929 38.862 49.649 ;
     RECT  0.144 49.099 0.162 49.675 ;
     RECT  0.144 49.675 0.342 49.771 ;
     RECT  0.108 49.771 0.342 49.883 ;
     RECT  1.152 49.483 18.897 50.117 ;
     RECT  21.276 49.649 38.862 50.189 ;
     RECT  21.276 50.189 23.166 50.351 ;
     RECT  1.152 50.117 17.37 50.423 ;
     RECT  0.324 49.883 0.342 50.827 ;
     RECT  0.108 50.827 0.342 50.861 ;
     RECT  1.332 50.423 17.37 50.927 ;
     RECT  21.276 50.351 22.266 50.927 ;
     RECT  23.076 50.351 23.166 51.089 ;
     RECT  0.108 50.861 0.126 51.149 ;
     RECT  21.456 50.927 22.266 51.197 ;
     RECT  1.332 50.927 9.738 51.269 ;
     RECT  1.332 51.269 9.306 51.737 ;
     RECT  24.015 50.189 38.862 51.871 ;
     RECT  23.148 51.089 23.166 51.971 ;
     RECT  23.904 51.871 38.862 52.079 ;
     RECT  1.44 51.737 9.306 52.205 ;
     RECT  2.016 52.205 9.306 52.321 ;
     RECT  21.456 51.197 21.978 52.349 ;
     RECT  2.016 52.321 9.63 52.439 ;
     RECT  23.904 52.079 24.297 52.448 ;
     RECT  2.016 52.439 4.05 52.475 ;
     RECT  5.256 52.439 9.63 52.717 ;
     RECT  2.052 52.475 4.05 52.781 ;
     RECT  5.256 52.717 9.666 52.853 ;
     RECT  22.824 52.681 22.842 52.853 ;
     RECT  2.052 52.781 3.654 52.979 ;
     RECT  5.256 52.853 9.162 52.979 ;
     RECT  2.052 52.979 2.79 53.015 ;
     RECT  10.764 50.927 17.37 53.159 ;
     RECT  5.256 52.979 6.282 53.249 ;
     RECT  7.236 52.979 9.162 53.249 ;
     RECT  2.052 53.015 2.697 53.285 ;
     RECT  7.236 53.249 8.622 53.357 ;
     RECT  7.236 53.357 8.586 53.405 ;
     RECT  5.364 53.249 6.282 53.519 ;
     RECT  7.815 53.405 8.586 53.885 ;
     RECT  5.58 53.519 6.282 54.365 ;
     RECT  13.215 53.159 17.37 54.401 ;
     RECT  5.58 54.365 6.102 54.437 ;
     RECT  24.015 52.448 24.297 54.472 ;
     RECT  10.764 53.159 12.33 54.509 ;
     RECT  22.824 54.409 22.842 54.509 ;
     RECT  23.904 54.472 24.297 54.509 ;
     RECT  13.215 54.401 16.83 54.779 ;
     RECT  10.764 54.509 12.006 54.869 ;
     RECT  14.544 54.779 16.83 55.283 ;
     RECT  10.764 54.869 11.682 55.409 ;
     RECT  15.12 55.283 16.83 55.553 ;
     RECT  18.615 50.117 18.897 56.101 ;
     RECT  19.872 49.649 20.502 56.101 ;
     RECT  18.615 56.101 20.502 56.285 ;
     RECT  11.664 55.409 11.682 56.597 ;
     RECT  15.12 55.553 16.542 56.669 ;
     RECT  10.764 55.409 10.782 57.053 ;
     RECT  20.484 56.285 20.502 57.341 ;
     RECT  15.696 56.669 16.542 57.479 ;
     RECT  6.084 54.437 6.102 57.569 ;
     RECT  16.272 57.479 16.542 57.725 ;
     RECT  16.272 57.725 16.29 57.839 ;
     RECT  18.615 56.285 19.422 58.013 ;
     RECT  21.456 52.349 21.474 58.253 ;
     RECT  25.02 52.079 38.862 58.451 ;
     RECT  25.02 58.451 25.074 59.741 ;
     RECT  25.02 59.741 25.038 60.077 ;
     RECT  26.064 58.451 38.862 61.469 ;
     RECT  26.1 61.469 38.862 62.339 ;
     RECT  26.136 62.339 38.862 62.465 ;
     RECT  26.136 62.465 26.226 63.149 ;
     RECT  26.136 63.149 26.154 64.967 ;
     RECT  27.216 62.465 38.862 65.129 ;
     RECT  27.216 65.129 38.79 65.165 ;
     RECT  28.44 65.165 38.79 65.399 ;
     RECT  28.44 65.399 38.07 65.435 ;
     RECT  34.815 65.435 38.07 65.669 ;
     RECT  34.815 65.669 37.386 65.741 ;
     RECT  27.216 65.165 27.558 65.777 ;
     RECT  28.44 65.435 33.966 65.813 ;
     RECT  28.44 65.813 28.458 65.849 ;
     RECT  29.304 65.813 33.966 65.939 ;
     RECT  34.815 65.741 36.594 65.939 ;
     RECT  29.304 65.939 33.462 66.011 ;
     RECT  27.216 65.777 27.234 66.047 ;
     RECT  33.444 66.011 33.462 66.047 ;
     RECT  37.368 65.741 37.386 66.119 ;
     RECT  29.304 66.011 32.526 66.209 ;
     RECT  34.815 65.939 36.486 66.221 ;
     RECT  29.304 66.209 31.95 66.245 ;
     RECT  34.815 66.221 36.342 66.245 ;
     RECT  34.815 66.245 35.226 66.289 ;
     RECT  30.78 66.245 31.95 66.317 ;
     RECT  29.304 66.245 29.697 66.389 ;
     RECT  30.78 66.317 30.87 66.389 ;
     RECT  34.2 66.289 35.226 66.389 ;
     RECT  31.932 66.317 31.95 66.479 ;
     RECT  34.815 66.389 35.226 66.509 ;
     RECT  30.78 66.389 30.798 66.659 ;
     RECT  2.415 53.285 2.697 66.707 ;
     RECT  7.815 53.885 8.097 66.707 ;
     RECT  13.215 54.779 13.497 66.707 ;
     RECT  18.615 58.013 18.897 66.707 ;
     RECT  24.015 54.509 24.297 66.707 ;
     RECT  29.415 66.389 29.697 66.707 ;
     RECT  34.815 66.509 35.097 66.707 ;
     RECT  2.415 66.707 2.505 66.977 ;
     RECT  7.815 66.707 7.905 66.977 ;
     RECT  13.215 66.707 13.305 66.977 ;
     RECT  18.615 66.707 18.705 66.977 ;
     RECT  24.015 66.707 24.105 66.977 ;
     RECT  29.415 66.707 29.505 66.977 ;
     RECT  34.815 66.707 34.905 66.977 ;
    LAYER M4 ;
     RECT  0.06 11.568 0.097 51.048 ;
     RECT  0.097 11.568 0.137 51.144 ;
     RECT  0.137 11.664 2.408 51.144 ;
     RECT  2.408 2.148 2.512 66.972 ;
     RECT  2.512 2.418 2.704 66.702 ;
     RECT  2.704 25.488 2.765 51.144 ;
     RECT  2.704 13.296 2.801 21 ;
     RECT  2.765 40.992 2.801 51.144 ;
     RECT  2.801 14.448 2.837 21 ;
     RECT  2.704 22.32 2.837 24.168 ;
     RECT  2.765 25.488 2.837 39.816 ;
     RECT  2.801 40.992 2.837 50.856 ;
     RECT  2.837 15.312 2.873 21 ;
     RECT  2.837 25.488 2.873 34.152 ;
     RECT  2.837 36.528 2.873 38.472 ;
     RECT  2.837 49.2 2.873 50.376 ;
     RECT  2.801 13.296 2.909 13.32 ;
     RECT  2.837 46.752 2.909 48.168 ;
     RECT  2.873 49.776 2.909 50.376 ;
     RECT  2.704 11.664 2.945 11.784 ;
     RECT  2.909 49.776 2.945 49.8 ;
     RECT  2.873 15.504 3.089 17.928 ;
     RECT  2.873 25.824 3.089 34.152 ;
     RECT  2.837 35.184 3.089 35.496 ;
     RECT  2.837 40.992 3.089 45.288 ;
     RECT  2.837 23.856 3.125 24.168 ;
     RECT  3.089 43.632 3.125 45.288 ;
     RECT  3.089 16.08 3.161 17.928 ;
     RECT  3.089 25.824 3.161 30.264 ;
     RECT  2.873 36.528 3.161 37.128 ;
     RECT  3.125 44.112 3.161 44.424 ;
     RECT  2.873 19.344 3.197 21 ;
     RECT  3.161 37.104 3.197 37.128 ;
     RECT  2.837 39.504 3.197 39.816 ;
     RECT  3.089 40.992 3.197 42.6 ;
     RECT  2.909 48.144 3.197 48.168 ;
     RECT  3.197 39.792 3.233 39.816 ;
     RECT  3.197 42.576 3.233 42.6 ;
     RECT  3.161 44.4 3.269 44.424 ;
     RECT  3.161 29.088 3.305 30.264 ;
     RECT  3.161 25.824 3.377 28.008 ;
     RECT  3.089 31.824 3.413 34.152 ;
     RECT  3.413 34.128 3.629 34.152 ;
     RECT  2.704 52.224 3.629 52.248 ;
     RECT  3.697 11.52 3.769 11.544 ;
     RECT  3.089 35.472 3.845 35.496 ;
     RECT  3.161 16.512 3.913 17.928 ;
     RECT  2.837 22.8 3.953 22.824 ;
     RECT  3.413 31.824 3.953 33 ;
     RECT  2.873 38.4 3.985 38.472 ;
     RECT  3.197 40.992 4.025 41.112 ;
     RECT  4.025 41.088 4.061 41.112 ;
     RECT  3.769 11.376 4.201 11.544 ;
     RECT  3.985 37.584 4.201 38.472 ;
     RECT  4.129 44.88 4.201 44.904 ;
     RECT  4.201 36.912 4.277 38.472 ;
     RECT  3.913 16.512 4.345 18.024 ;
     RECT  3.125 24.144 4.345 24.168 ;
     RECT  3.377 26.784 4.405 28.008 ;
     RECT  3.305 29.088 4.405 29.112 ;
     RECT  4.201 11.376 4.412 11.88 ;
     RECT  4.381 35.76 4.412 35.784 ;
     RECT  4.277 36.912 4.412 37.8 ;
     RECT  4.412 11.328 4.417 11.88 ;
     RECT  3.305 30.24 4.421 30.264 ;
     RECT  4.417 11.328 4.453 12.552 ;
     RECT  4.165 13.536 4.453 13.56 ;
     RECT  4.345 16.368 4.453 18.024 ;
     RECT  4.345 49.008 4.453 49.032 ;
     RECT  4.453 11.328 4.499 13.56 ;
     RECT  3.197 20.016 4.525 20.856 ;
     RECT  4.273 21.84 4.525 22.2 ;
     RECT  4.453 48.336 4.525 49.032 ;
     RECT  4.201 44.88 4.597 44.952 ;
     RECT  2.909 46.752 4.633 46.824 ;
     RECT  4.453 15.6 4.673 18.024 ;
     RECT  4.499 11.376 4.705 13.56 ;
     RECT  3.953 32.064 4.777 33 ;
     RECT  4.405 26.784 4.781 29.112 ;
     RECT  4.525 20.016 4.817 22.2 ;
     RECT  4.673 17.616 4.849 18.024 ;
     RECT  4.525 34.752 4.849 34.776 ;
     RECT  4.412 35.76 4.849 37.8 ;
     RECT  4.633 46.752 4.849 46.872 ;
     RECT  4.525 47.904 4.849 49.032 ;
     RECT  4.817 20.016 4.885 20.568 ;
     RECT  4.849 34.752 4.993 37.8 ;
     RECT  4.777 32.064 5.029 33.528 ;
     RECT  4.993 34.704 5.029 37.8 ;
     RECT  4.817 21.6 5.065 22.2 ;
     RECT  5.029 32.064 5.065 37.8 ;
     RECT  4.237 50.544 5.065 50.568 ;
     RECT  4.525 38.928 5.101 39.336 ;
     RECT  4.597 44.208 5.101 44.952 ;
     RECT  5.101 43.776 5.209 44.952 ;
     RECT  4.849 46.752 5.317 49.032 ;
     RECT  4.705 11.376 5.363 14.28 ;
     RECT  4.849 17.616 5.389 18.168 ;
     RECT  5.101 38.928 5.389 40.968 ;
     RECT  4.885 42.192 5.389 42.216 ;
     RECT  5.389 17.616 5.425 18.408 ;
     RECT  4.781 27.264 5.429 29.112 ;
     RECT  4.345 23.76 5.461 24.984 ;
     RECT  5.065 31.872 5.461 37.8 ;
     RECT  5.389 38.928 5.461 42.216 ;
     RECT  5.065 50.016 5.501 50.568 ;
     RECT  5.429 27.6 5.509 29.112 ;
     RECT  5.065 21.6 5.533 22.728 ;
     RECT  5.461 23.76 5.533 25.992 ;
     RECT  5.461 31.872 5.533 42.216 ;
     RECT  5.209 43.68 5.533 44.952 ;
     RECT  5.363 11.472 5.605 14.28 ;
     RECT  4.673 15.6 5.605 16.536 ;
     RECT  5.317 46.512 5.605 49.032 ;
     RECT  5.605 11.472 5.645 16.536 ;
     RECT  5.605 51.888 5.677 51.912 ;
     RECT  5.425 17.616 5.749 18.648 ;
     RECT  4.885 19.968 5.749 20.568 ;
     RECT  5.749 17.616 5.857 20.568 ;
     RECT  5.533 21.6 5.857 25.992 ;
     RECT  5.857 17.616 5.969 25.992 ;
     RECT  5.969 17.616 6.005 23.976 ;
     RECT  5.969 24.96 6.073 25.992 ;
     RECT  6.005 17.616 6.221 21.432 ;
     RECT  6.221 17.616 6.329 19.368 ;
     RECT  5.965 30.48 6.401 30.504 ;
     RECT  5.533 31.872 6.401 44.952 ;
     RECT  5.645 11.472 6.437 14.808 ;
     RECT  5.509 27.6 6.541 28.728 ;
     RECT  5.677 51.888 6.613 52.44 ;
     RECT  5.605 46.128 6.721 49.032 ;
     RECT  6.401 32.304 6.761 44.952 ;
     RECT  6.721 46.08 6.825 49.032 ;
     RECT  6.073 24.96 6.829 26.52 ;
     RECT  6.541 27.552 6.829 28.728 ;
     RECT  6.825 46.08 7.009 48.696 ;
     RECT  6.221 20.496 7.117 21.432 ;
     RECT  6.005 22.704 7.117 23.976 ;
     RECT  7.117 20.496 7.153 23.976 ;
     RECT  6.829 24.96 7.153 28.728 ;
     RECT  6.613 51.264 7.225 52.44 ;
     RECT  6.253 54.336 7.225 54.36 ;
     RECT  5.645 15.792 7.261 16.536 ;
     RECT  6.329 17.664 7.381 19.368 ;
     RECT  7.153 20.496 7.381 28.728 ;
     RECT  6.437 11.472 7.808 14.28 ;
     RECT  7.261 15.792 7.808 16.68 ;
     RECT  7.381 17.664 7.808 28.728 ;
     RECT  7.045 30.048 7.808 30.072 ;
     RECT  6.761 32.352 7.808 44.712 ;
     RECT  7.009 45.696 7.808 48.696 ;
     RECT  5.501 50.016 7.808 50.136 ;
     RECT  7.225 51.264 7.808 54.36 ;
     RECT  7.808 2.148 7.912 66.972 ;
     RECT  7.912 2.418 8.104 66.702 ;
     RECT  8.104 11.712 8.165 14.808 ;
     RECT  8.104 30.048 8.165 30.312 ;
     RECT  8.104 50.784 8.243 54.36 ;
     RECT  8.104 26.352 8.273 28.536 ;
     RECT  8.104 45.696 8.273 48.696 ;
     RECT  8.104 31.632 8.339 39.336 ;
     RECT  8.339 31.632 8.381 36.648 ;
     RECT  8.339 38.688 8.381 39 ;
     RECT  8.165 13.152 8.417 14.808 ;
     RECT  8.104 16.752 8.453 18.168 ;
     RECT  8.273 27.072 8.453 28.536 ;
     RECT  8.381 32.832 8.453 36.648 ;
     RECT  8.453 16.8 8.483 18.168 ;
     RECT  8.417 13.152 8.489 14.136 ;
     RECT  8.453 32.832 8.525 36.072 ;
     RECT  8.273 46.08 8.531 48.696 ;
     RECT  8.525 32.832 8.597 35.88 ;
     RECT  8.104 21.12 9.029 25.032 ;
     RECT  8.453 28.512 9.065 28.536 ;
     RECT  8.453 27.072 9.173 27.096 ;
     RECT  9.241 50.256 9.277 50.28 ;
     RECT  8.104 42.144 9.281 44.664 ;
     RECT  9.029 21.12 9.308 24.936 ;
     RECT  8.165 30.288 9.349 30.312 ;
     RECT  8.531 46.08 9.353 47.064 ;
     RECT  9.241 26.496 9.385 26.52 ;
     RECT  9.308 20.736 9.395 24.936 ;
     RECT  9.349 30.24 9.421 30.312 ;
     RECT  8.381 31.632 9.421 31.656 ;
     RECT  8.381 38.736 9.421 39 ;
     RECT  8.597 32.832 9.425 34.152 ;
     RECT  9.281 44.64 9.425 44.664 ;
     RECT  9.277 49.92 9.425 50.28 ;
     RECT  9.421 30.24 9.505 31.656 ;
     RECT  9.421 38.208 9.505 39 ;
     RECT  9.353 46.8 9.605 47.064 ;
     RECT  9.505 30.24 9.613 30.36 ;
     RECT  8.597 35.472 9.641 35.88 ;
     RECT  8.483 17.04 9.677 17.064 ;
     RECT  9.613 30.24 9.713 30.312 ;
     RECT  9.425 50.256 9.713 50.28 ;
     RECT  9.713 30.288 9.785 30.312 ;
     RECT  9.505 38.976 9.817 39 ;
     RECT  9.505 31.632 9.929 31.656 ;
     RECT  9.395 20.832 10.253 24.936 ;
     RECT  9.641 35.472 10.289 35.784 ;
     RECT  10.253 20.832 10.325 24.888 ;
     RECT  10.325 20.832 10.397 24.216 ;
     RECT  9.385 26.256 10.465 26.52 ;
     RECT  10.465 26.064 10.501 26.52 ;
     RECT  10.501 26.064 10.645 26.808 ;
     RECT  9.605 46.8 10.645 46.824 ;
     RECT  10.645 30.48 10.793 30.504 ;
     RECT  10.645 46.704 10.793 46.824 ;
     RECT  10.645 26.064 10.829 26.904 ;
     RECT  10.861 50.448 10.973 50.472 ;
     RECT  8.104 19.248 11.513 19.272 ;
     RECT  10.289 35.472 11.869 35.496 ;
     RECT  8.243 51.504 12.229 54.36 ;
     RECT  10.829 26.256 12.373 26.52 ;
     RECT  11.869 35.424 12.409 35.496 ;
     RECT  8.489 14.112 12.517 14.136 ;
     RECT  12.517 13.488 12.553 14.136 ;
     RECT  10.793 46.8 12.553 46.824 ;
     RECT  9.817 38.976 12.697 39.816 ;
     RECT  8.165 11.712 13.208 11.736 ;
     RECT  12.553 13.488 13.208 14.232 ;
     RECT  8.483 18.144 13.208 18.168 ;
     RECT  11.581 19.296 13.208 19.32 ;
     RECT  10.397 20.832 13.208 23.688 ;
     RECT  12.373 25.488 13.208 26.52 ;
     RECT  9.425 32.832 13.208 33.672 ;
     RECT  12.409 35.424 13.208 35.736 ;
     RECT  13.045 36.816 13.208 36.84 ;
     RECT  12.697 38.784 13.208 39.816 ;
     RECT  9.281 42.144 13.208 43.608 ;
     RECT  12.553 46.8 13.208 46.872 ;
     RECT  8.531 48.096 13.208 48.696 ;
     RECT  13.021 49.824 13.208 49.848 ;
     RECT  12.229 51.504 13.208 54.408 ;
     RECT  10.753 57.024 13.208 57.048 ;
     RECT  13.208 2.148 13.312 66.972 ;
     RECT  13.312 2.418 13.504 66.702 ;
     RECT  13.504 42.144 14.033 43.608 ;
     RECT  14.033 42.144 14.821 43.32 ;
     RECT  13.504 14.208 14.929 14.232 ;
     RECT  14.929 14.208 15.041 14.856 ;
     RECT  13.504 57.024 15.145 57.048 ;
     RECT  15.041 14.208 15.251 14.232 ;
     RECT  15.205 15.312 15.865 15.48 ;
     RECT  14.821 16.56 15.865 16.584 ;
     RECT  13.504 32.832 15.925 32.856 ;
     RECT  13.504 39.792 15.925 39.816 ;
     RECT  13.504 48.096 15.925 48.696 ;
     RECT  13.504 46.848 15.971 46.872 ;
     RECT  15.925 39.024 16.012 39.816 ;
     RECT  15.865 15.312 16.481 16.584 ;
     RECT  15.145 56.064 16.513 57.048 ;
     RECT  15.925 48.096 16.909 48.744 ;
     RECT  13.504 35.424 17.273 35.592 ;
     RECT  13.504 36.816 17.561 36.84 ;
     RECT  16.481 16.032 17.809 16.584 ;
     RECT  16.909 47.856 18.097 48.744 ;
     RECT  13.504 19.296 18.205 19.32 ;
     RECT  17.809 16.032 18.277 16.632 ;
     RECT  18.277 16.032 18.608 16.824 ;
     RECT  13.504 18.144 18.608 18.168 ;
     RECT  18.205 19.296 18.608 19.608 ;
     RECT  13.504 20.832 18.608 23.688 ;
     RECT  13.504 25.488 18.608 26.52 ;
     RECT  15.925 32.832 18.608 33.624 ;
     RECT  17.273 35.568 18.608 35.592 ;
     RECT  13.504 37.872 18.608 37.896 ;
     RECT  16.012 39.792 18.608 39.816 ;
     RECT  14.821 42 18.608 43.32 ;
     RECT  18.097 47.712 18.608 48.744 ;
     RECT  13.504 49.824 18.608 49.848 ;
     RECT  13.504 51.504 18.608 54.504 ;
     RECT  16.513 56.064 18.608 57.72 ;
     RECT  18.608 2.148 18.712 66.972 ;
     RECT  18.712 2.418 18.904 66.702 ;
     RECT  18.904 18.144 19.037 19.656 ;
     RECT  18.904 35.568 19.037 36.552 ;
     RECT  18.904 31.344 19.091 31.56 ;
     RECT  18.904 42 19.091 42.024 ;
     RECT  18.904 43.296 19.181 43.32 ;
     RECT  18.904 16.032 19.505 16.92 ;
     RECT  18.904 20.832 20.261 23.688 ;
     RECT  19.037 18.144 20.473 19.512 ;
     RECT  18.904 37.872 21.733 37.896 ;
     RECT  20.473 18.144 22.201 19.8 ;
     RECT  20.261 20.832 22.201 23.016 ;
     RECT  19.091 31.344 22.813 31.368 ;
     RECT  18.904 45.216 22.813 45.24 ;
     RECT  22.669 28.656 22.817 28.68 ;
     RECT  22.813 31.344 22.853 31.464 ;
     RECT  21.733 37.872 22.853 38.52 ;
     RECT  22.813 45.072 22.997 45.24 ;
     RECT  19.505 16.032 23.557 16.872 ;
     RECT  22.201 18.144 23.557 23.016 ;
     RECT  23.461 14.688 24.008 14.712 ;
     RECT  23.557 16.032 24.008 23.016 ;
     RECT  18.904 25.488 24.008 26.52 ;
     RECT  22.853 31.44 24.008 31.464 ;
     RECT  18.904 32.832 24.008 32.856 ;
     RECT  19.037 35.568 24.008 35.592 ;
     RECT  22.853 37.872 24.008 38.424 ;
     RECT  18.904 39.792 24.008 39.816 ;
     RECT  22.997 45.216 24.008 45.24 ;
     RECT  18.904 47.712 24.008 48.744 ;
     RECT  18.904 49.824 24.008 49.848 ;
     RECT  18.904 51.504 24.008 54.504 ;
     RECT  18.904 56.064 24.008 58.008 ;
     RECT  24.008 2.148 24.112 66.972 ;
     RECT  24.112 2.148 24.229 66.702 ;
     RECT  24.229 1.728 24.304 66.702 ;
     RECT  24.229 0.096 24.325 0.12 ;
     RECT  24.325 0.096 24.467 0.312 ;
     RECT  24.304 31.44 24.467 33.336 ;
     RECT  24.304 18.144 25.139 23.016 ;
     RECT  24.304 14.544 25.157 17.016 ;
     RECT  24.304 42.528 25.157 42.744 ;
     RECT  24.304 37.872 25.229 38.424 ;
     RECT  24.304 45.024 25.229 46.104 ;
     RECT  24.304 47.088 25.229 50.088 ;
     RECT  25.229 37.968 25.297 38.424 ;
     RECT  24.304 39.792 25.297 40.104 ;
     RECT  24.304 1.728 25.373 1.752 ;
     RECT  24.304 28.8 25.381 28.824 ;
     RECT  24.304 30.192 25.381 30.216 ;
     RECT  25.381 28.8 25.429 30.216 ;
     RECT  25.381 9.6 25.525 9.624 ;
     RECT  25.525 9.552 25.573 9.624 ;
     RECT  25.429 10.896 25.573 10.92 ;
     RECT  24.467 32.112 25.573 33.336 ;
     RECT  25.573 9.552 25.717 10.92 ;
     RECT  25.157 14.544 25.724 14.808 ;
     RECT  25.724 14.304 25.805 14.808 ;
     RECT  25.805 14.304 25.811 14.328 ;
     RECT  24.304 2.784 25.813 2.808 ;
     RECT  25.573 32.112 25.813 33.816 ;
     RECT  25.717 9.552 25.861 11.304 ;
     RECT  25.429 28.704 25.861 30.216 ;
     RECT  25.861 27.984 25.909 30.216 ;
     RECT  25.157 16.032 25.949 17.016 ;
     RECT  24.304 51.12 25.957 54.648 ;
     RECT  24.304 56.064 25.957 58.008 ;
     RECT  25.813 32.112 26.005 33.96 ;
     RECT  26.005 41.136 26.017 41.16 ;
     RECT  25.157 42.528 26.017 42.552 ;
     RECT  25.297 37.968 26.053 40.104 ;
     RECT  25.229 45.024 26.053 45.24 ;
     RECT  25.949 16.032 26.093 16.968 ;
     RECT  25.909 27.936 26.101 30.216 ;
     RECT  26.101 27.888 26.149 30.216 ;
     RECT  26.005 31.92 26.149 33.96 ;
     RECT  26.053 61.44 26.161 61.464 ;
     RECT  24.304 59.712 26.245 60.072 ;
     RECT  24.304 3.936 26.389 4.968 ;
     RECT  25.229 47.712 26.417 50.088 ;
     RECT  26.417 48.864 26.437 50.088 ;
     RECT  25.957 51.12 26.437 58.008 ;
     RECT  25.861 9.552 26.485 11.544 ;
     RECT  26.149 27.888 26.485 33.96 ;
     RECT  26.053 37.968 26.485 40.152 ;
     RECT  26.017 41.136 26.485 42.552 ;
     RECT  26.485 37.968 26.521 42.552 ;
     RECT  24.304 24.768 26.533 26.52 ;
     RECT  26.485 27.744 26.533 33.96 ;
     RECT  26.197 63.12 26.533 63.144 ;
     RECT  26.389 3.936 26.581 5.88 ;
     RECT  26.005 64.608 26.581 64.632 ;
     RECT  26.053 66.24 26.581 66.264 ;
     RECT  26.437 48.864 26.677 58.008 ;
     RECT  26.245 59.328 26.677 60.072 ;
     RECT  26.053 44.4 26.701 45.24 ;
     RECT  26.581 3.936 26.725 6.024 ;
     RECT  26.701 44.4 26.725 45.672 ;
     RECT  26.533 63.12 26.725 63.24 ;
     RECT  26.485 9.264 26.773 11.544 ;
     RECT  26.677 48.864 26.773 60.072 ;
     RECT  26.533 7.92 26.809 7.944 ;
     RECT  26.773 9.264 26.809 11.736 ;
     RECT  25.139 18.288 26.845 23.016 ;
     RECT  26.521 37.92 27.025 42.552 ;
     RECT  26.725 44.208 27.097 45.672 ;
     RECT  26.845 18.288 27.109 23.304 ;
     RECT  26.533 24.768 27.109 33.96 ;
     RECT  27.097 44.208 27.133 45.816 ;
     RECT  26.093 16.032 27.241 16.824 ;
     RECT  27.109 18.288 27.241 33.96 ;
     RECT  26.725 3.936 27.253 6.552 ;
     RECT  27.133 43.968 27.277 45.816 ;
     RECT  26.161 61.44 27.301 61.752 ;
     RECT  26.725 63.12 27.301 63.528 ;
     RECT  24.304 35.568 27.313 35.592 ;
     RECT  27.277 43.824 27.349 45.816 ;
     RECT  27.025 37.056 27.385 42.552 ;
     RECT  27.349 43.776 27.385 45.816 ;
     RECT  27.313 35.568 27.397 36.024 ;
     RECT  26.809 7.92 27.457 11.736 ;
     RECT  25.513 12.768 27.457 12.792 ;
     RECT  27.385 37.056 27.457 45.816 ;
     RECT  27.457 7.92 27.493 12.792 ;
     RECT  25.813 2.736 27.541 2.808 ;
     RECT  27.253 3.936 27.541 6.696 ;
     RECT  27.529 14.832 27.565 14.856 ;
     RECT  27.241 16.032 27.565 33.96 ;
     RECT  27.541 2.736 27.601 6.696 ;
     RECT  27.493 7.728 27.601 12.792 ;
     RECT  27.601 2.736 27.635 12.792 ;
     RECT  26.417 47.712 27.637 47.88 ;
     RECT  26.773 48.864 27.637 60.408 ;
     RECT  27.301 61.44 27.637 63.528 ;
     RECT  27.637 47.712 27.673 60.408 ;
     RECT  27.635 2.736 27.676 7.992 ;
     RECT  27.637 61.392 27.733 63.528 ;
     RECT  26.581 64.608 27.733 66.264 ;
     RECT  27.673 47.424 27.781 60.408 ;
     RECT  27.397 35.088 27.821 36.024 ;
     RECT  27.781 46.896 27.829 60.408 ;
     RECT  27.733 61.392 27.829 66.264 ;
     RECT  27.635 9.264 27.965 12.792 ;
     RECT  27.829 46.896 28.069 66.264 ;
     RECT  27.457 37.008 28.105 45.816 ;
     RECT  28.069 46.896 28.105 66.552 ;
     RECT  27.821 35.184 28.249 36.024 ;
     RECT  28.105 37.008 28.249 66.552 ;
     RECT  27.565 14.832 28.405 33.96 ;
     RECT  27.676 2.736 28.825 7.944 ;
     RECT  28.405 14.112 28.897 33.96 ;
     RECT  28.249 35.184 28.897 66.552 ;
     RECT  27.965 9.264 28.981 12.552 ;
     RECT  28.981 9.264 29.365 13.128 ;
     RECT  28.897 14.112 29.365 66.552 ;
     RECT  28.825 2.736 29.408 8.28 ;
     RECT  29.365 9.264 29.408 66.552 ;
     RECT  29.408 2.148 29.512 66.972 ;
     RECT  29.512 2.418 29.704 66.702 ;
     RECT  29.704 2.736 30.809 66.552 ;
     RECT  30.809 2.784 32.141 66.552 ;
     RECT  32.141 2.784 32.249 35.928 ;
     RECT  32.141 37.008 32.321 66.552 ;
     RECT  32.249 2.784 32.429 35.496 ;
     RECT  32.321 37.008 32.465 38.76 ;
     RECT  32.465 38.064 32.717 38.76 ;
     RECT  32.717 38.064 33.113 38.568 ;
     RECT  32.465 37.008 33.329 37.032 ;
     RECT  32.321 39.888 34.021 66.552 ;
     RECT  32.429 2.784 34.045 34.776 ;
     RECT  33.113 38.544 34.045 38.568 ;
     RECT  34.021 39.84 34.045 66.552 ;
     RECT  34.045 2.784 34.333 35.736 ;
     RECT  34.045 38.544 34.333 66.552 ;
     RECT  34.333 37.968 34.369 66.552 ;
     RECT  34.333 2.784 34.405 36.072 ;
     RECT  34.405 2.592 34.808 36.072 ;
     RECT  34.369 37.632 34.808 66.552 ;
     RECT  34.808 2.148 34.912 66.972 ;
     RECT  34.912 2.418 35.104 66.702 ;
     RECT  35.104 37.584 35.237 66.504 ;
     RECT  35.104 2.592 35.417 36.072 ;
     RECT  35.417 8.448 35.603 36.072 ;
     RECT  35.603 8.496 35.669 36.072 ;
     RECT  35.417 2.592 35.788 7.416 ;
     RECT  35.788 2.592 35.813 7.224 ;
     RECT  35.669 8.496 35.957 35.88 ;
     RECT  35.237 37.584 35.993 66.216 ;
     RECT  35.957 8.544 36.029 35.88 ;
     RECT  35.993 63.84 36.137 66.216 ;
     RECT  36.137 63.84 36.181 64.44 ;
     RECT  36.029 8.784 36.245 35.88 ;
     RECT  36.137 65.424 36.245 66.216 ;
     RECT  36.181 64.416 36.281 64.44 ;
     RECT  36.245 8.976 36.353 35.88 ;
     RECT  35.813 2.736 36.569 7.224 ;
     RECT  36.353 9.072 36.707 35.88 ;
     RECT  36.245 65.568 36.707 66.216 ;
     RECT  35.993 37.584 36.793 62.856 ;
     RECT  36.707 20.064 36.997 35.88 ;
     RECT  36.793 37.584 36.997 60.456 ;
     RECT  36.707 9.072 37.001 19.08 ;
     RECT  36.569 2.736 37.043 6.312 ;
     RECT  36.997 20.064 37.091 60.456 ;
     RECT  37.001 9.072 37.187 10.344 ;
     RECT  37.043 2.736 37.331 5.592 ;
     RECT  37.331 2.784 37.427 5.592 ;
     RECT  37.001 11.328 37.475 19.08 ;
     RECT  37.091 58.704 37.657 60.456 ;
     RECT  37.475 11.376 37.667 19.08 ;
     RECT  37.667 11.376 37.829 14.952 ;
     RECT  37.427 2.784 37.907 5.112 ;
     RECT  37.187 9.072 38.003 9.096 ;
     RECT  37.829 11.376 38.051 14.808 ;
     RECT  36.793 61.536 38.051 62.856 ;
     RECT  37.187 10.176 38.099 10.344 ;
     RECT  38.041 64.416 38.125 64.44 ;
     RECT  38.099 10.32 38.147 10.344 ;
     RECT  38.051 61.536 38.147 61.608 ;
     RECT  38.051 62.64 38.243 62.856 ;
     RECT  38.051 11.472 38.291 14.808 ;
     RECT  38.291 11.952 38.339 14.808 ;
     RECT  37.091 20.064 38.339 57.672 ;
     RECT  38.243 62.64 38.339 62.664 ;
     RECT  37.667 15.984 38.365 19.08 ;
     RECT  38.339 20.064 38.365 57.48 ;
     RECT  37.657 58.704 38.389 59.88 ;
     RECT  37.907 3.36 38.483 5.112 ;
     RECT  38.389 58.56 38.557 59.88 ;
     RECT  38.483 3.36 38.579 4.488 ;
     RECT  36.707 65.616 38.579 66.216 ;
     RECT  38.339 11.952 38.627 14.328 ;
     RECT  38.557 58.56 38.665 59.304 ;
     RECT  38.579 3.36 38.675 3.864 ;
     RECT  38.579 66.144 38.675 66.216 ;
     RECT  38.627 11.952 38.723 11.976 ;
     RECT  38.365 15.984 38.729 57.48 ;
     RECT  38.653 61.008 38.737 61.032 ;
     RECT  38.675 3.36 38.771 3.384 ;
     RECT  38.675 66.192 38.771 66.216 ;
     RECT  38.665 58.56 38.819 58.68 ;
     RECT  38.819 58.656 38.837 58.68 ;
     RECT  38.627 13.008 38.844 14.328 ;
     RECT  38.729 16.08 38.844 57.48 ;
     RECT  38.844 14.304 38.873 14.328 ;
    LAYER M5 ;
     RECT  24.336 0.016 24.456 0.085 ;
     RECT  24.24 0.085 24.456 2.137 ;
     RECT  2.4 2.137 2.52 2.151 ;
     RECT  7.8 2.137 7.92 2.151 ;
     RECT  13.2 2.137 13.32 2.151 ;
     RECT  18.6 2.137 18.72 2.151 ;
     RECT  29.4 2.137 29.52 2.151 ;
     RECT  34.8 2.137 34.92 2.151 ;
     RECT  34.8 2.151 35.112 2.581 ;
     RECT  34.416 2.581 35.112 2.725 ;
     RECT  24 2.137 24.456 2.773 ;
     RECT  25.824 2.725 25.848 2.773 ;
     RECT  37.296 2.725 37.32 2.773 ;
     RECT  34.416 2.725 35.4 2.821 ;
     RECT  29.4 2.151 29.712 3.013 ;
     RECT  28.608 3.013 29.712 3.061 ;
     RECT  34.416 2.821 35.592 3.253 ;
     RECT  37.296 2.773 37.896 3.349 ;
     RECT  28.608 3.061 30.6 3.493 ;
     RECT  31.872 3.397 31.896 3.493 ;
     RECT  27.552 3.301 27.576 3.589 ;
     RECT  28.608 3.493 31.896 3.589 ;
     RECT  33.216 3.829 33.24 3.877 ;
     RECT  34.416 3.253 36.168 3.877 ;
     RECT  33.216 3.877 36.168 3.925 ;
     RECT  37.296 3.349 38.76 3.925 ;
     RECT  24 2.773 25.848 4.165 ;
     RECT  27.552 3.589 31.896 4.213 ;
     RECT  27.312 4.213 31.896 4.741 ;
     RECT  33.216 3.925 38.76 4.741 ;
     RECT  27.312 4.741 38.76 4.981 ;
     RECT  24 4.165 26.088 5.845 ;
     RECT  27.12 4.981 38.76 5.845 ;
     RECT  4.464 11.317 4.488 11.365 ;
     RECT  13.2 2.151 13.512 11.701 ;
     RECT  4.464 11.365 5.352 11.747 ;
     RECT  4.464 11.747 4.488 11.987 ;
     RECT  12.528 11.701 13.512 13.523 ;
     RECT  7.8 2.151 8.112 14.245 ;
     RECT  6.864 14.245 8.112 14.773 ;
     RECT  15.216 14.197 15.24 15.491 ;
     RECT  0.192 15.493 0.216 15.779 ;
     RECT  6.864 14.773 8.376 16.789 ;
     RECT  24 5.845 38.76 16.837 ;
     RECT  23.568 16.837 38.76 17.651 ;
     RECT  6.864 16.789 8.472 17.891 ;
     RECT  18.6 2.151 18.912 18.997 ;
     RECT  18.6 18.997 19.368 19.331 ;
     RECT  0.144 18.613 0.168 19.379 ;
     RECT  6.864 17.891 8.112 19.379 ;
     RECT  7.392 19.379 8.112 20.003 ;
     RECT  0.192 20.245 0.216 20.435 ;
     RECT  2.4 2.151 2.712 20.821 ;
     RECT  2.4 20.821 2.808 20.963 ;
     RECT  9.36 20.725 9.384 22.165 ;
     RECT  7.8 20.003 8.112 22.741 ;
     RECT  7.68 22.741 8.112 23.317 ;
     RECT  9.36 22.165 9.576 23.317 ;
     RECT  7.68 23.317 9.576 23.411 ;
     RECT  5.328 20.485 5.352 24.037 ;
     RECT  5.328 24.037 5.496 24.083 ;
     RECT  0.144 25.813 0.168 26.099 ;
     RECT  0.24 26.869 0.264 27.155 ;
     RECT  7.8 23.411 9.576 27.973 ;
     RECT  4.416 27.253 4.44 28.451 ;
     RECT  6.864 27.973 9.576 28.691 ;
     RECT  5.472 24.083 5.496 29.123 ;
     RECT  7.8 28.691 9.576 30.275 ;
     RECT  24 17.651 38.76 30.275 ;
     RECT  9.456 30.275 9.576 30.371 ;
     RECT  33.264 30.275 38.76 30.659 ;
     RECT  7.8 30.275 8.472 31.667 ;
     RECT  24 30.275 32.232 31.715 ;
     RECT  33.696 30.659 38.76 32.149 ;
     RECT  33.12 32.149 38.76 32.339 ;
     RECT  7.8 31.667 8.112 32.773 ;
     RECT  33.696 32.339 38.76 32.819 ;
     RECT  33.696 32.819 38.664 33.011 ;
     RECT  7.248 32.773 8.112 33.013 ;
     RECT  9.456 30.371 9.48 33.013 ;
     RECT  24 31.715 31.608 33.013 ;
     RECT  33.696 33.011 37.944 33.203 ;
     RECT  24 33.013 31.656 33.347 ;
     RECT  28.56 33.347 31.656 33.395 ;
     RECT  0.144 33.301 0.168 33.587 ;
     RECT  25.344 33.347 27.336 33.635 ;
     RECT  34.416 33.203 37.896 33.731 ;
     RECT  37.296 33.731 37.896 33.779 ;
     RECT  34.416 33.731 35.736 33.827 ;
     RECT  30.72 33.395 31.656 33.875 ;
     RECT  30.816 33.875 31.656 33.877 ;
     RECT  37.872 33.779 37.896 34.067 ;
     RECT  30.816 33.877 32.088 34.115 ;
     RECT  34.464 33.827 35.736 34.307 ;
     RECT  7.152 33.013 9.48 34.835 ;
     RECT  34.8 34.307 35.4 34.835 ;
     RECT  28.56 33.395 29.712 34.885 ;
     RECT  30.816 34.115 31.656 34.885 ;
     RECT  25.344 33.635 26.712 35.077 ;
     RECT  13.2 13.523 13.512 36.805 ;
     RECT  25.344 35.077 27.432 37.093 ;
     RECT  28.56 34.885 31.656 37.093 ;
     RECT  4.464 36.517 4.488 37.619 ;
     RECT  25.344 37.093 31.656 37.763 ;
     RECT  7.2 34.835 9.48 38.243 ;
     RECT  30.816 37.763 31.656 38.243 ;
     RECT  25.344 37.763 29.712 38.531 ;
     RECT  13.056 36.805 13.512 38.819 ;
     RECT  34.8 34.835 35.112 38.869 ;
     RECT  25.968 38.531 27.432 38.915 ;
     RECT  34.704 38.869 35.112 39.301 ;
     RECT  34.704 39.301 35.88 39.829 ;
     RECT  7.2 38.243 9.096 39.877 ;
     RECT  28.512 38.531 29.712 40.165 ;
     RECT  28.512 40.165 29.832 40.309 ;
     RECT  30.816 38.243 31.176 40.309 ;
     RECT  25.968 38.915 26.712 40.357 ;
     RECT  28.512 40.309 31.176 40.357 ;
     RECT  25.968 40.357 31.176 40.597 ;
     RECT  32.256 40.165 32.28 40.597 ;
     RECT  38.64 40.549 38.664 40.645 ;
     RECT  38.64 40.645 38.76 40.741 ;
     RECT  34.032 39.829 35.88 40.933 ;
     RECT  33.408 40.933 35.88 40.981 ;
     RECT  25.968 40.597 32.28 41.413 ;
     RECT  33.408 40.981 36.072 41.413 ;
     RECT  25.968 41.413 36.072 41.989 ;
     RECT  38.448 40.741 38.76 41.989 ;
     RECT  25.968 41.989 36.168 42.133 ;
     RECT  25.968 42.133 36.6 43.045 ;
     RECT  37.872 41.989 38.76 43.045 ;
     RECT  6.816 39.877 9.096 43.477 ;
     RECT  6.672 43.477 9.096 43.523 ;
     RECT  6.672 43.523 6.792 43.619 ;
     RECT  18.6 19.331 19.08 45.251 ;
     RECT  2.4 20.963 2.712 46.597 ;
     RECT  2.4 46.597 2.808 47.891 ;
     RECT  15.936 33.589 15.96 48.755 ;
     RECT  6.768 43.619 6.792 49.043 ;
     RECT  24 33.347 24.312 49.189 ;
     RECT  0.192 49.717 0.216 49.907 ;
     RECT  24 49.189 24.504 50.099 ;
     RECT  0.144 50.341 0.168 50.723 ;
     RECT  7.8 43.523 9.096 52.499 ;
     RECT  25.968 43.045 38.76 56.245 ;
     RECT  25.68 56.245 38.76 56.531 ;
     RECT  26.016 56.531 38.76 58.549 ;
     RECT  26.016 58.549 38.808 58.691 ;
     RECT  26.016 58.691 38.76 62.819 ;
     RECT  26.016 62.819 36.696 63.347 ;
     RECT  26.016 63.347 33.384 63.539 ;
     RECT  27.696 63.539 33.384 63.923 ;
     RECT  27.696 63.923 31.752 64.355 ;
     RECT  38.064 62.819 38.76 64.451 ;
     RECT  29.4 64.355 31.752 64.547 ;
     RECT  29.4 64.547 31.512 64.595 ;
     RECT  26.016 63.539 26.616 64.643 ;
     RECT  29.4 64.595 31.416 64.691 ;
     RECT  33.024 63.923 33.384 64.691 ;
     RECT  29.4 64.691 29.928 65.171 ;
     RECT  30.96 64.691 31.416 65.219 ;
     RECT  27.696 64.355 28.296 65.267 ;
     RECT  26.064 64.643 26.616 65.459 ;
     RECT  34.704 63.347 36.696 65.603 ;
     RECT  38.544 64.451 38.76 65.651 ;
     RECT  27.696 65.267 28.104 65.699 ;
     RECT  34.704 65.603 36.072 65.699 ;
     RECT  33.024 64.691 33.048 65.747 ;
     RECT  38.64 65.651 38.76 66.179 ;
     RECT  34.8 65.699 36.072 66.227 ;
     RECT  38.736 66.179 38.76 66.227 ;
     RECT  26.064 65.459 26.088 66.275 ;
     RECT  31.392 65.219 31.416 66.515 ;
     RECT  28.08 65.699 28.104 66.563 ;
     RECT  2.4 47.891 2.712 66.969 ;
     RECT  7.8 52.499 8.112 66.969 ;
     RECT  13.2 38.819 13.512 66.969 ;
     RECT  18.6 45.251 18.912 66.969 ;
     RECT  24 50.099 24.312 66.969 ;
     RECT  29.4 65.171 29.712 66.969 ;
     RECT  34.8 66.227 35.112 66.969 ;
     RECT  2.4 66.969 2.52 66.983 ;
     RECT  7.8 66.969 7.92 66.983 ;
     RECT  13.2 66.969 13.32 66.983 ;
     RECT  18.6 66.969 18.72 66.983 ;
     RECT  24 66.969 24.12 66.983 ;
     RECT  29.4 66.969 29.52 66.983 ;
     RECT  34.8 66.969 34.92 66.983 ;
     RECT  24.456 2.725 25.824 2.773 ;
     RECT  36.168 3.253 37.296 3.925 ;
     RECT  27.576 3.301 28.608 3.589 ;
     RECT  30.6 3.397 31.872 3.493 ;
     RECT  31.896 3.829 33.216 4.741 ;
     RECT  33.24 3.829 34.416 3.877 ;
     RECT  26.088 4.165 27.552 4.213 ;
     RECT  26.088 4.213 27.312 4.981 ;
     RECT  26.088 4.981 27.12 5.845 ;
     RECT  8.112 20.725 9.36 23.317 ;
     RECT  4.44 27.253 5.472 28.451 ;
     RECT  5.496 27.973 6.864 28.691 ;
     RECT  8.472 30.275 9.456 31.667 ;
     RECT  32.232 30.275 33.264 30.659 ;
     RECT  32.232 30.659 33.696 31.715 ;
     RECT  8.112 31.667 9.456 33.013 ;
     RECT  31.608 31.715 33.696 32.149 ;
     RECT  31.608 32.149 33.12 32.339 ;
     RECT  31.608 32.339 31.656 33.013 ;
     RECT  24.312 33.347 25.344 38.531 ;
     RECT  27.336 33.347 28.56 33.635 ;
     RECT  29.712 33.395 30.72 33.875 ;
     RECT  26.712 33.635 28.56 35.077 ;
     RECT  29.712 33.875 30.816 34.885 ;
     RECT  27.432 35.077 28.56 37.093 ;
     RECT  29.712 37.763 30.816 40.165 ;
     RECT  27.432 38.531 28.512 38.915 ;
     RECT  26.712 38.915 28.512 40.357 ;
     RECT  29.832 40.165 30.816 40.309 ;
     RECT  31.176 40.165 32.256 40.597 ;
     RECT  32.28 40.933 33.408 41.413 ;
     RECT  36.6 42.133 37.872 43.045 ;
     RECT  6.792 43.523 7.8 49.043 ;
     RECT  24.504 49.189 25.968 50.099 ;
     RECT  24.312 56.245 25.68 56.531 ;
     RECT  36.696 62.819 38.064 64.451 ;
     RECT  33.384 63.347 34.704 64.691 ;
     RECT  26.616 63.539 27.696 65.459 ;
     RECT  31.752 63.923 33.024 64.547 ;
     RECT  28.296 64.355 29.4 65.267 ;
     RECT  31.512 64.547 33.024 64.595 ;
     RECT  29.928 64.691 30.96 65.171 ;
     RECT  29.712 65.171 30.96 65.219 ;
     RECT  28.104 65.267 29.4 66.563 ;
  END
END ot_qfd_vm_gctl_t
END LIBRARY
